VERSION 5.7 ;
BUSBITCHARS "[]" ;
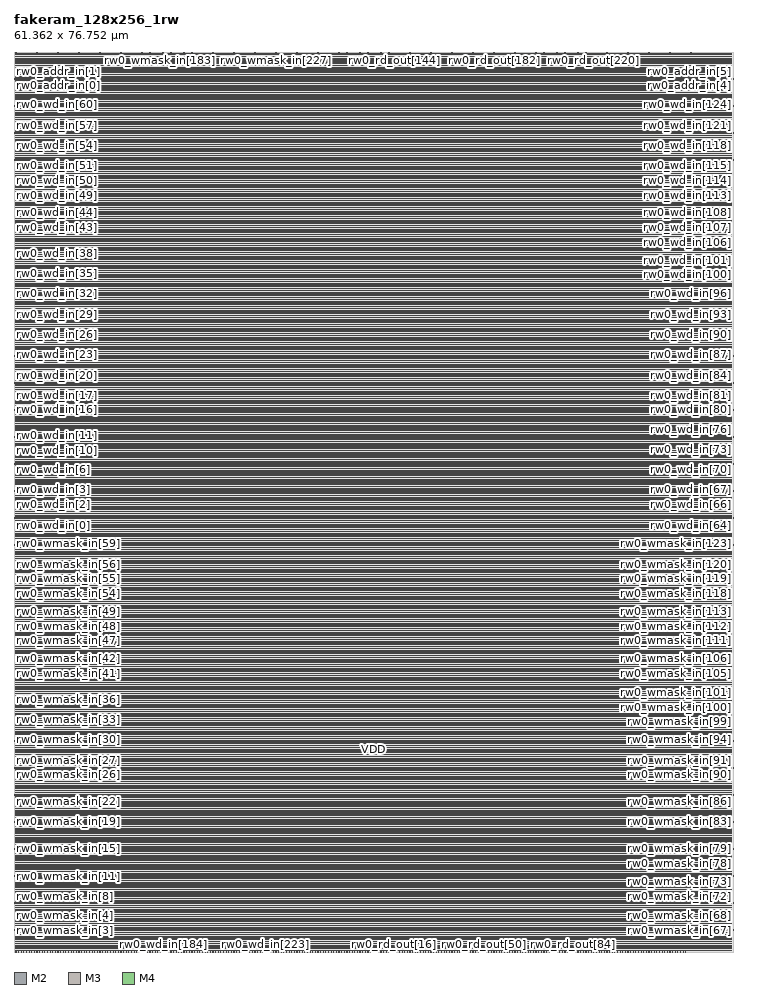
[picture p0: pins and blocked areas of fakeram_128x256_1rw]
MACRO fakeram_128x256_1rw
  FOREIGN fakeram_128x256_1rw 0 0 ;
  SYMMETRY X Y R90 ;
  SIZE 61.362 BY 76.752 ;
  CLASS BLOCK ;
  PIN rw0_wmask_in[0]
    DIRECTION INPUT ;
    USE SIGNAL ;
    SHAPE ABUTMENT ;
    PORT
      LAYER M2 ;
      RECT 0.000 0.138 0.036 0.150 ;
    END
  END rw0_wmask_in[0]
  PIN rw0_wmask_in[1]
    DIRECTION INPUT ;
    USE SIGNAL ;
    SHAPE ABUTMENT ;
    PORT
      LAYER M2 ;
      RECT 0.000 0.714 0.036 0.726 ;
    END
  END rw0_wmask_in[1]
  PIN rw0_wmask_in[2]
    DIRECTION INPUT ;
    USE SIGNAL ;
    SHAPE ABUTMENT ;
    PORT
      LAYER M2 ;
      RECT 0.000 1.290 0.036 1.302 ;
    END
  END rw0_wmask_in[2]
  PIN rw0_wmask_in[3]
    DIRECTION INPUT ;
    USE SIGNAL ;
    SHAPE ABUTMENT ;
    PORT
      LAYER M2 ;
      RECT 0.000 1.866 0.036 1.878 ;
    END
  END rw0_wmask_in[3]
  PIN rw0_wmask_in[4]
    DIRECTION INPUT ;
    USE SIGNAL ;
    SHAPE ABUTMENT ;
    PORT
      LAYER M2 ;
      RECT 0.000 2.442 0.036 2.454 ;
    END
  END rw0_wmask_in[4]
  PIN rw0_wmask_in[5]
    DIRECTION INPUT ;
    USE SIGNAL ;
    SHAPE ABUTMENT ;
    PORT
      LAYER M2 ;
      RECT 0.000 3.018 0.036 3.030 ;
    END
  END rw0_wmask_in[5]
  PIN rw0_wmask_in[6]
    DIRECTION INPUT ;
    USE SIGNAL ;
    SHAPE ABUTMENT ;
    PORT
      LAYER M2 ;
      RECT 0.000 3.594 0.036 3.606 ;
    END
  END rw0_wmask_in[6]
  PIN rw0_wmask_in[7]
    DIRECTION INPUT ;
    USE SIGNAL ;
    SHAPE ABUTMENT ;
    PORT
      LAYER M2 ;
      RECT 0.000 4.170 0.036 4.182 ;
    END
  END rw0_wmask_in[7]
  PIN rw0_wmask_in[8]
    DIRECTION INPUT ;
    USE SIGNAL ;
    SHAPE ABUTMENT ;
    PORT
      LAYER M2 ;
      RECT 0.000 4.746 0.036 4.758 ;
    END
  END rw0_wmask_in[8]
  PIN rw0_wmask_in[9]
    DIRECTION INPUT ;
    USE SIGNAL ;
    SHAPE ABUTMENT ;
    PORT
      LAYER M2 ;
      RECT 0.000 5.322 0.036 5.334 ;
    END
  END rw0_wmask_in[9]
  PIN rw0_wmask_in[10]
    DIRECTION INPUT ;
    USE SIGNAL ;
    SHAPE ABUTMENT ;
    PORT
      LAYER M2 ;
      RECT 0.000 5.898 0.036 5.910 ;
    END
  END rw0_wmask_in[10]
  PIN rw0_wmask_in[11]
    DIRECTION INPUT ;
    USE SIGNAL ;
    SHAPE ABUTMENT ;
    PORT
      LAYER M2 ;
      RECT 0.000 6.474 0.036 6.486 ;
    END
  END rw0_wmask_in[11]
  PIN rw0_wmask_in[12]
    DIRECTION INPUT ;
    USE SIGNAL ;
    SHAPE ABUTMENT ;
    PORT
      LAYER M2 ;
      RECT 0.000 7.050 0.036 7.062 ;
    END
  END rw0_wmask_in[12]
  PIN rw0_wmask_in[13]
    DIRECTION INPUT ;
    USE SIGNAL ;
    SHAPE ABUTMENT ;
    PORT
      LAYER M2 ;
      RECT 0.000 7.626 0.036 7.638 ;
    END
  END rw0_wmask_in[13]
  PIN rw0_wmask_in[14]
    DIRECTION INPUT ;
    USE SIGNAL ;
    SHAPE ABUTMENT ;
    PORT
      LAYER M2 ;
      RECT 0.000 8.202 0.036 8.214 ;
    END
  END rw0_wmask_in[14]
  PIN rw0_wmask_in[15]
    DIRECTION INPUT ;
    USE SIGNAL ;
    SHAPE ABUTMENT ;
    PORT
      LAYER M2 ;
      RECT 0.000 8.778 0.036 8.790 ;
    END
  END rw0_wmask_in[15]
  PIN rw0_wmask_in[16]
    DIRECTION INPUT ;
    USE SIGNAL ;
    SHAPE ABUTMENT ;
    PORT
      LAYER M2 ;
      RECT 0.000 9.354 0.036 9.366 ;
    END
  END rw0_wmask_in[16]
  PIN rw0_wmask_in[17]
    DIRECTION INPUT ;
    USE SIGNAL ;
    SHAPE ABUTMENT ;
    PORT
      LAYER M2 ;
      RECT 0.000 9.930 0.036 9.942 ;
    END
  END rw0_wmask_in[17]
  PIN rw0_wmask_in[18]
    DIRECTION INPUT ;
    USE SIGNAL ;
    SHAPE ABUTMENT ;
    PORT
      LAYER M2 ;
      RECT 0.000 10.506 0.036 10.518 ;
    END
  END rw0_wmask_in[18]
  PIN rw0_wmask_in[19]
    DIRECTION INPUT ;
    USE SIGNAL ;
    SHAPE ABUTMENT ;
    PORT
      LAYER M2 ;
      RECT 0.000 11.082 0.036 11.094 ;
    END
  END rw0_wmask_in[19]
  PIN rw0_wmask_in[20]
    DIRECTION INPUT ;
    USE SIGNAL ;
    SHAPE ABUTMENT ;
    PORT
      LAYER M2 ;
      RECT 0.000 11.658 0.036 11.670 ;
    END
  END rw0_wmask_in[20]
  PIN rw0_wmask_in[21]
    DIRECTION INPUT ;
    USE SIGNAL ;
    SHAPE ABUTMENT ;
    PORT
      LAYER M2 ;
      RECT 0.000 12.234 0.036 12.246 ;
    END
  END rw0_wmask_in[21]
  PIN rw0_wmask_in[22]
    DIRECTION INPUT ;
    USE SIGNAL ;
    SHAPE ABUTMENT ;
    PORT
      LAYER M2 ;
      RECT 0.000 12.810 0.036 12.822 ;
    END
  END rw0_wmask_in[22]
  PIN rw0_wmask_in[23]
    DIRECTION INPUT ;
    USE SIGNAL ;
    SHAPE ABUTMENT ;
    PORT
      LAYER M2 ;
      RECT 0.000 13.386 0.036 13.398 ;
    END
  END rw0_wmask_in[23]
  PIN rw0_wmask_in[24]
    DIRECTION INPUT ;
    USE SIGNAL ;
    SHAPE ABUTMENT ;
    PORT
      LAYER M2 ;
      RECT 0.000 13.962 0.036 13.974 ;
    END
  END rw0_wmask_in[24]
  PIN rw0_wmask_in[25]
    DIRECTION INPUT ;
    USE SIGNAL ;
    SHAPE ABUTMENT ;
    PORT
      LAYER M2 ;
      RECT 0.000 14.538 0.036 14.550 ;
    END
  END rw0_wmask_in[25]
  PIN rw0_wmask_in[26]
    DIRECTION INPUT ;
    USE SIGNAL ;
    SHAPE ABUTMENT ;
    PORT
      LAYER M2 ;
      RECT 0.000 15.114 0.036 15.126 ;
    END
  END rw0_wmask_in[26]
  PIN rw0_wmask_in[27]
    DIRECTION INPUT ;
    USE SIGNAL ;
    SHAPE ABUTMENT ;
    PORT
      LAYER M2 ;
      RECT 0.000 15.690 0.036 15.702 ;
    END
  END rw0_wmask_in[27]
  PIN rw0_wmask_in[28]
    DIRECTION INPUT ;
    USE SIGNAL ;
    SHAPE ABUTMENT ;
    PORT
      LAYER M2 ;
      RECT 0.000 16.266 0.036 16.278 ;
    END
  END rw0_wmask_in[28]
  PIN rw0_wmask_in[29]
    DIRECTION INPUT ;
    USE SIGNAL ;
    SHAPE ABUTMENT ;
    PORT
      LAYER M2 ;
      RECT 0.000 16.842 0.036 16.854 ;
    END
  END rw0_wmask_in[29]
  PIN rw0_wmask_in[30]
    DIRECTION INPUT ;
    USE SIGNAL ;
    SHAPE ABUTMENT ;
    PORT
      LAYER M2 ;
      RECT 0.000 17.418 0.036 17.430 ;
    END
  END rw0_wmask_in[30]
  PIN rw0_wmask_in[31]
    DIRECTION INPUT ;
    USE SIGNAL ;
    SHAPE ABUTMENT ;
    PORT
      LAYER M2 ;
      RECT 0.000 17.994 0.036 18.006 ;
    END
  END rw0_wmask_in[31]
  PIN rw0_wmask_in[32]
    DIRECTION INPUT ;
    USE SIGNAL ;
    SHAPE ABUTMENT ;
    PORT
      LAYER M2 ;
      RECT 0.000 18.570 0.036 18.582 ;
    END
  END rw0_wmask_in[32]
  PIN rw0_wmask_in[33]
    DIRECTION INPUT ;
    USE SIGNAL ;
    SHAPE ABUTMENT ;
    PORT
      LAYER M2 ;
      RECT 0.000 19.146 0.036 19.158 ;
    END
  END rw0_wmask_in[33]
  PIN rw0_wmask_in[34]
    DIRECTION INPUT ;
    USE SIGNAL ;
    SHAPE ABUTMENT ;
    PORT
      LAYER M2 ;
      RECT 0.000 19.722 0.036 19.734 ;
    END
  END rw0_wmask_in[34]
  PIN rw0_wmask_in[35]
    DIRECTION INPUT ;
    USE SIGNAL ;
    SHAPE ABUTMENT ;
    PORT
      LAYER M2 ;
      RECT 0.000 20.298 0.036 20.310 ;
    END
  END rw0_wmask_in[35]
  PIN rw0_wmask_in[36]
    DIRECTION INPUT ;
    USE SIGNAL ;
    SHAPE ABUTMENT ;
    PORT
      LAYER M2 ;
      RECT 0.000 20.874 0.036 20.886 ;
    END
  END rw0_wmask_in[36]
  PIN rw0_wmask_in[37]
    DIRECTION INPUT ;
    USE SIGNAL ;
    SHAPE ABUTMENT ;
    PORT
      LAYER M2 ;
      RECT 0.000 21.450 0.036 21.462 ;
    END
  END rw0_wmask_in[37]
  PIN rw0_wmask_in[38]
    DIRECTION INPUT ;
    USE SIGNAL ;
    SHAPE ABUTMENT ;
    PORT
      LAYER M2 ;
      RECT 0.000 22.026 0.036 22.038 ;
    END
  END rw0_wmask_in[38]
  PIN rw0_wmask_in[39]
    DIRECTION INPUT ;
    USE SIGNAL ;
    SHAPE ABUTMENT ;
    PORT
      LAYER M2 ;
      RECT 0.000 22.602 0.036 22.614 ;
    END
  END rw0_wmask_in[39]
  PIN rw0_wmask_in[40]
    DIRECTION INPUT ;
    USE SIGNAL ;
    SHAPE ABUTMENT ;
    PORT
      LAYER M2 ;
      RECT 0.000 23.178 0.036 23.190 ;
    END
  END rw0_wmask_in[40]
  PIN rw0_wmask_in[41]
    DIRECTION INPUT ;
    USE SIGNAL ;
    SHAPE ABUTMENT ;
    PORT
      LAYER M2 ;
      RECT 0.000 23.754 0.036 23.766 ;
    END
  END rw0_wmask_in[41]
  PIN rw0_wmask_in[42]
    DIRECTION INPUT ;
    USE SIGNAL ;
    SHAPE ABUTMENT ;
    PORT
      LAYER M2 ;
      RECT 0.000 24.330 0.036 24.342 ;
    END
  END rw0_wmask_in[42]
  PIN rw0_wmask_in[43]
    DIRECTION INPUT ;
    USE SIGNAL ;
    SHAPE ABUTMENT ;
    PORT
      LAYER M2 ;
      RECT 0.000 24.906 0.036 24.918 ;
    END
  END rw0_wmask_in[43]
  PIN rw0_wmask_in[44]
    DIRECTION INPUT ;
    USE SIGNAL ;
    SHAPE ABUTMENT ;
    PORT
      LAYER M2 ;
      RECT 0.000 25.482 0.036 25.494 ;
    END
  END rw0_wmask_in[44]
  PIN rw0_wmask_in[45]
    DIRECTION INPUT ;
    USE SIGNAL ;
    SHAPE ABUTMENT ;
    PORT
      LAYER M2 ;
      RECT 0.000 26.058 0.036 26.070 ;
    END
  END rw0_wmask_in[45]
  PIN rw0_wmask_in[46]
    DIRECTION INPUT ;
    USE SIGNAL ;
    SHAPE ABUTMENT ;
    PORT
      LAYER M2 ;
      RECT 0.000 26.634 0.036 26.646 ;
    END
  END rw0_wmask_in[46]
  PIN rw0_wmask_in[47]
    DIRECTION INPUT ;
    USE SIGNAL ;
    SHAPE ABUTMENT ;
    PORT
      LAYER M2 ;
      RECT 0.000 27.210 0.036 27.222 ;
    END
  END rw0_wmask_in[47]
  PIN rw0_wmask_in[48]
    DIRECTION INPUT ;
    USE SIGNAL ;
    SHAPE ABUTMENT ;
    PORT
      LAYER M2 ;
      RECT 0.000 27.786 0.036 27.798 ;
    END
  END rw0_wmask_in[48]
  PIN rw0_wmask_in[49]
    DIRECTION INPUT ;
    USE SIGNAL ;
    SHAPE ABUTMENT ;
    PORT
      LAYER M2 ;
      RECT 0.000 28.362 0.036 28.374 ;
    END
  END rw0_wmask_in[49]
  PIN rw0_wmask_in[50]
    DIRECTION INPUT ;
    USE SIGNAL ;
    SHAPE ABUTMENT ;
    PORT
      LAYER M2 ;
      RECT 0.000 28.938 0.036 28.950 ;
    END
  END rw0_wmask_in[50]
  PIN rw0_wmask_in[51]
    DIRECTION INPUT ;
    USE SIGNAL ;
    SHAPE ABUTMENT ;
    PORT
      LAYER M2 ;
      RECT 0.000 29.514 0.036 29.526 ;
    END
  END rw0_wmask_in[51]
  PIN rw0_wmask_in[52]
    DIRECTION INPUT ;
    USE SIGNAL ;
    SHAPE ABUTMENT ;
    PORT
      LAYER M2 ;
      RECT 0.000 30.090 0.036 30.102 ;
    END
  END rw0_wmask_in[52]
  PIN rw0_wmask_in[53]
    DIRECTION INPUT ;
    USE SIGNAL ;
    SHAPE ABUTMENT ;
    PORT
      LAYER M2 ;
      RECT 0.000 30.666 0.036 30.678 ;
    END
  END rw0_wmask_in[53]
  PIN rw0_wmask_in[54]
    DIRECTION INPUT ;
    USE SIGNAL ;
    SHAPE ABUTMENT ;
    PORT
      LAYER M2 ;
      RECT 0.000 31.242 0.036 31.254 ;
    END
  END rw0_wmask_in[54]
  PIN rw0_wmask_in[55]
    DIRECTION INPUT ;
    USE SIGNAL ;
    SHAPE ABUTMENT ;
    PORT
      LAYER M2 ;
      RECT 0.000 31.818 0.036 31.830 ;
    END
  END rw0_wmask_in[55]
  PIN rw0_wmask_in[56]
    DIRECTION INPUT ;
    USE SIGNAL ;
    SHAPE ABUTMENT ;
    PORT
      LAYER M2 ;
      RECT 0.000 32.394 0.036 32.406 ;
    END
  END rw0_wmask_in[56]
  PIN rw0_wmask_in[57]
    DIRECTION INPUT ;
    USE SIGNAL ;
    SHAPE ABUTMENT ;
    PORT
      LAYER M2 ;
      RECT 0.000 32.970 0.036 32.982 ;
    END
  END rw0_wmask_in[57]
  PIN rw0_wmask_in[58]
    DIRECTION INPUT ;
    USE SIGNAL ;
    SHAPE ABUTMENT ;
    PORT
      LAYER M2 ;
      RECT 0.000 33.546 0.036 33.558 ;
    END
  END rw0_wmask_in[58]
  PIN rw0_wmask_in[59]
    DIRECTION INPUT ;
    USE SIGNAL ;
    SHAPE ABUTMENT ;
    PORT
      LAYER M2 ;
      RECT 0.000 34.122 0.036 34.134 ;
    END
  END rw0_wmask_in[59]
  PIN rw0_wmask_in[60]
    DIRECTION INPUT ;
    USE SIGNAL ;
    SHAPE ABUTMENT ;
    PORT
      LAYER M2 ;
      RECT 0.000 34.698 0.036 34.710 ;
    END
  END rw0_wmask_in[60]
  PIN rw0_wmask_in[61]
    DIRECTION INPUT ;
    USE SIGNAL ;
    SHAPE ABUTMENT ;
    PORT
      LAYER M2 ;
      RECT 0.000 35.274 0.036 35.286 ;
    END
  END rw0_wmask_in[61]
  PIN rw0_wmask_in[62]
    DIRECTION INPUT ;
    USE SIGNAL ;
    SHAPE ABUTMENT ;
    PORT
      LAYER M2 ;
      RECT 0.000 35.850 0.036 35.862 ;
    END
  END rw0_wmask_in[62]
  PIN rw0_wmask_in[63]
    DIRECTION INPUT ;
    USE SIGNAL ;
    SHAPE ABUTMENT ;
    PORT
      LAYER M2 ;
      RECT 0.000 36.426 0.036 36.438 ;
    END
  END rw0_wmask_in[63]
  PIN rw0_wmask_in[64]
    DIRECTION INPUT ;
    USE SIGNAL ;
    SHAPE ABUTMENT ;
    PORT
      LAYER M2 ;
      RECT 61.326 0.138 61.362 0.150 ;
    END
  END rw0_wmask_in[64]
  PIN rw0_wmask_in[65]
    DIRECTION INPUT ;
    USE SIGNAL ;
    SHAPE ABUTMENT ;
    PORT
      LAYER M2 ;
      RECT 61.326 0.714 61.362 0.726 ;
    END
  END rw0_wmask_in[65]
  PIN rw0_wmask_in[66]
    DIRECTION INPUT ;
    USE SIGNAL ;
    SHAPE ABUTMENT ;
    PORT
      LAYER M2 ;
      RECT 61.326 1.290 61.362 1.302 ;
    END
  END rw0_wmask_in[66]
  PIN rw0_wmask_in[67]
    DIRECTION INPUT ;
    USE SIGNAL ;
    SHAPE ABUTMENT ;
    PORT
      LAYER M2 ;
      RECT 61.326 1.866 61.362 1.878 ;
    END
  END rw0_wmask_in[67]
  PIN rw0_wmask_in[68]
    DIRECTION INPUT ;
    USE SIGNAL ;
    SHAPE ABUTMENT ;
    PORT
      LAYER M2 ;
      RECT 61.326 2.442 61.362 2.454 ;
    END
  END rw0_wmask_in[68]
  PIN rw0_wmask_in[69]
    DIRECTION INPUT ;
    USE SIGNAL ;
    SHAPE ABUTMENT ;
    PORT
      LAYER M2 ;
      RECT 61.326 3.018 61.362 3.030 ;
    END
  END rw0_wmask_in[69]
  PIN rw0_wmask_in[70]
    DIRECTION INPUT ;
    USE SIGNAL ;
    SHAPE ABUTMENT ;
    PORT
      LAYER M2 ;
      RECT 61.326 3.594 61.362 3.606 ;
    END
  END rw0_wmask_in[70]
  PIN rw0_wmask_in[71]
    DIRECTION INPUT ;
    USE SIGNAL ;
    SHAPE ABUTMENT ;
    PORT
      LAYER M2 ;
      RECT 61.326 4.170 61.362 4.182 ;
    END
  END rw0_wmask_in[71]
  PIN rw0_wmask_in[72]
    DIRECTION INPUT ;
    USE SIGNAL ;
    SHAPE ABUTMENT ;
    PORT
      LAYER M2 ;
      RECT 61.326 4.746 61.362 4.758 ;
    END
  END rw0_wmask_in[72]
  PIN rw0_wmask_in[73]
    DIRECTION INPUT ;
    USE SIGNAL ;
    SHAPE ABUTMENT ;
    PORT
      LAYER M2 ;
      RECT 61.326 5.322 61.362 5.334 ;
    END
  END rw0_wmask_in[73]
  PIN rw0_wmask_in[74]
    DIRECTION INPUT ;
    USE SIGNAL ;
    SHAPE ABUTMENT ;
    PORT
      LAYER M2 ;
      RECT 61.326 5.898 61.362 5.910 ;
    END
  END rw0_wmask_in[74]
  PIN rw0_wmask_in[75]
    DIRECTION INPUT ;
    USE SIGNAL ;
    SHAPE ABUTMENT ;
    PORT
      LAYER M2 ;
      RECT 61.326 6.474 61.362 6.486 ;
    END
  END rw0_wmask_in[75]
  PIN rw0_wmask_in[76]
    DIRECTION INPUT ;
    USE SIGNAL ;
    SHAPE ABUTMENT ;
    PORT
      LAYER M2 ;
      RECT 61.326 7.050 61.362 7.062 ;
    END
  END rw0_wmask_in[76]
  PIN rw0_wmask_in[77]
    DIRECTION INPUT ;
    USE SIGNAL ;
    SHAPE ABUTMENT ;
    PORT
      LAYER M2 ;
      RECT 61.326 7.626 61.362 7.638 ;
    END
  END rw0_wmask_in[77]
  PIN rw0_wmask_in[78]
    DIRECTION INPUT ;
    USE SIGNAL ;
    SHAPE ABUTMENT ;
    PORT
      LAYER M2 ;
      RECT 61.326 8.202 61.362 8.214 ;
    END
  END rw0_wmask_in[78]
  PIN rw0_wmask_in[79]
    DIRECTION INPUT ;
    USE SIGNAL ;
    SHAPE ABUTMENT ;
    PORT
      LAYER M2 ;
      RECT 61.326 8.778 61.362 8.790 ;
    END
  END rw0_wmask_in[79]
  PIN rw0_wmask_in[80]
    DIRECTION INPUT ;
    USE SIGNAL ;
    SHAPE ABUTMENT ;
    PORT
      LAYER M2 ;
      RECT 61.326 9.354 61.362 9.366 ;
    END
  END rw0_wmask_in[80]
  PIN rw0_wmask_in[81]
    DIRECTION INPUT ;
    USE SIGNAL ;
    SHAPE ABUTMENT ;
    PORT
      LAYER M2 ;
      RECT 61.326 9.930 61.362 9.942 ;
    END
  END rw0_wmask_in[81]
  PIN rw0_wmask_in[82]
    DIRECTION INPUT ;
    USE SIGNAL ;
    SHAPE ABUTMENT ;
    PORT
      LAYER M2 ;
      RECT 61.326 10.506 61.362 10.518 ;
    END
  END rw0_wmask_in[82]
  PIN rw0_wmask_in[83]
    DIRECTION INPUT ;
    USE SIGNAL ;
    SHAPE ABUTMENT ;
    PORT
      LAYER M2 ;
      RECT 61.326 11.082 61.362 11.094 ;
    END
  END rw0_wmask_in[83]
  PIN rw0_wmask_in[84]
    DIRECTION INPUT ;
    USE SIGNAL ;
    SHAPE ABUTMENT ;
    PORT
      LAYER M2 ;
      RECT 61.326 11.658 61.362 11.670 ;
    END
  END rw0_wmask_in[84]
  PIN rw0_wmask_in[85]
    DIRECTION INPUT ;
    USE SIGNAL ;
    SHAPE ABUTMENT ;
    PORT
      LAYER M2 ;
      RECT 61.326 12.234 61.362 12.246 ;
    END
  END rw0_wmask_in[85]
  PIN rw0_wmask_in[86]
    DIRECTION INPUT ;
    USE SIGNAL ;
    SHAPE ABUTMENT ;
    PORT
      LAYER M2 ;
      RECT 61.326 12.810 61.362 12.822 ;
    END
  END rw0_wmask_in[86]
  PIN rw0_wmask_in[87]
    DIRECTION INPUT ;
    USE SIGNAL ;
    SHAPE ABUTMENT ;
    PORT
      LAYER M2 ;
      RECT 61.326 13.386 61.362 13.398 ;
    END
  END rw0_wmask_in[87]
  PIN rw0_wmask_in[88]
    DIRECTION INPUT ;
    USE SIGNAL ;
    SHAPE ABUTMENT ;
    PORT
      LAYER M2 ;
      RECT 61.326 13.962 61.362 13.974 ;
    END
  END rw0_wmask_in[88]
  PIN rw0_wmask_in[89]
    DIRECTION INPUT ;
    USE SIGNAL ;
    SHAPE ABUTMENT ;
    PORT
      LAYER M2 ;
      RECT 61.326 14.538 61.362 14.550 ;
    END
  END rw0_wmask_in[89]
  PIN rw0_wmask_in[90]
    DIRECTION INPUT ;
    USE SIGNAL ;
    SHAPE ABUTMENT ;
    PORT
      LAYER M2 ;
      RECT 61.326 15.114 61.362 15.126 ;
    END
  END rw0_wmask_in[90]
  PIN rw0_wmask_in[91]
    DIRECTION INPUT ;
    USE SIGNAL ;
    SHAPE ABUTMENT ;
    PORT
      LAYER M2 ;
      RECT 61.326 15.690 61.362 15.702 ;
    END
  END rw0_wmask_in[91]
  PIN rw0_wmask_in[92]
    DIRECTION INPUT ;
    USE SIGNAL ;
    SHAPE ABUTMENT ;
    PORT
      LAYER M2 ;
      RECT 61.326 16.266 61.362 16.278 ;
    END
  END rw0_wmask_in[92]
  PIN rw0_wmask_in[93]
    DIRECTION INPUT ;
    USE SIGNAL ;
    SHAPE ABUTMENT ;
    PORT
      LAYER M2 ;
      RECT 61.326 16.842 61.362 16.854 ;
    END
  END rw0_wmask_in[93]
  PIN rw0_wmask_in[94]
    DIRECTION INPUT ;
    USE SIGNAL ;
    SHAPE ABUTMENT ;
    PORT
      LAYER M2 ;
      RECT 61.326 17.418 61.362 17.430 ;
    END
  END rw0_wmask_in[94]
  PIN rw0_wmask_in[95]
    DIRECTION INPUT ;
    USE SIGNAL ;
    SHAPE ABUTMENT ;
    PORT
      LAYER M2 ;
      RECT 61.326 17.994 61.362 18.006 ;
    END
  END rw0_wmask_in[95]
  PIN rw0_wmask_in[96]
    DIRECTION INPUT ;
    USE SIGNAL ;
    SHAPE ABUTMENT ;
    PORT
      LAYER M2 ;
      RECT 61.326 18.570 61.362 18.582 ;
    END
  END rw0_wmask_in[96]
  PIN rw0_wmask_in[97]
    DIRECTION INPUT ;
    USE SIGNAL ;
    SHAPE ABUTMENT ;
    PORT
      LAYER M2 ;
      RECT 61.326 19.146 61.362 19.158 ;
    END
  END rw0_wmask_in[97]
  PIN rw0_wmask_in[98]
    DIRECTION INPUT ;
    USE SIGNAL ;
    SHAPE ABUTMENT ;
    PORT
      LAYER M2 ;
      RECT 61.326 19.722 61.362 19.734 ;
    END
  END rw0_wmask_in[98]
  PIN rw0_wmask_in[99]
    DIRECTION INPUT ;
    USE SIGNAL ;
    SHAPE ABUTMENT ;
    PORT
      LAYER M2 ;
      RECT 61.326 20.298 61.362 20.310 ;
    END
  END rw0_wmask_in[99]
  PIN rw0_wmask_in[100]
    DIRECTION INPUT ;
    USE SIGNAL ;
    SHAPE ABUTMENT ;
    PORT
      LAYER M2 ;
      RECT 61.326 20.874 61.362 20.886 ;
    END
  END rw0_wmask_in[100]
  PIN rw0_wmask_in[101]
    DIRECTION INPUT ;
    USE SIGNAL ;
    SHAPE ABUTMENT ;
    PORT
      LAYER M2 ;
      RECT 61.326 21.450 61.362 21.462 ;
    END
  END rw0_wmask_in[101]
  PIN rw0_wmask_in[102]
    DIRECTION INPUT ;
    USE SIGNAL ;
    SHAPE ABUTMENT ;
    PORT
      LAYER M2 ;
      RECT 61.326 22.026 61.362 22.038 ;
    END
  END rw0_wmask_in[102]
  PIN rw0_wmask_in[103]
    DIRECTION INPUT ;
    USE SIGNAL ;
    SHAPE ABUTMENT ;
    PORT
      LAYER M2 ;
      RECT 61.326 22.602 61.362 22.614 ;
    END
  END rw0_wmask_in[103]
  PIN rw0_wmask_in[104]
    DIRECTION INPUT ;
    USE SIGNAL ;
    SHAPE ABUTMENT ;
    PORT
      LAYER M2 ;
      RECT 61.326 23.178 61.362 23.190 ;
    END
  END rw0_wmask_in[104]
  PIN rw0_wmask_in[105]
    DIRECTION INPUT ;
    USE SIGNAL ;
    SHAPE ABUTMENT ;
    PORT
      LAYER M2 ;
      RECT 61.326 23.754 61.362 23.766 ;
    END
  END rw0_wmask_in[105]
  PIN rw0_wmask_in[106]
    DIRECTION INPUT ;
    USE SIGNAL ;
    SHAPE ABUTMENT ;
    PORT
      LAYER M2 ;
      RECT 61.326 24.330 61.362 24.342 ;
    END
  END rw0_wmask_in[106]
  PIN rw0_wmask_in[107]
    DIRECTION INPUT ;
    USE SIGNAL ;
    SHAPE ABUTMENT ;
    PORT
      LAYER M2 ;
      RECT 61.326 24.906 61.362 24.918 ;
    END
  END rw0_wmask_in[107]
  PIN rw0_wmask_in[108]
    DIRECTION INPUT ;
    USE SIGNAL ;
    SHAPE ABUTMENT ;
    PORT
      LAYER M2 ;
      RECT 61.326 25.482 61.362 25.494 ;
    END
  END rw0_wmask_in[108]
  PIN rw0_wmask_in[109]
    DIRECTION INPUT ;
    USE SIGNAL ;
    SHAPE ABUTMENT ;
    PORT
      LAYER M2 ;
      RECT 61.326 26.058 61.362 26.070 ;
    END
  END rw0_wmask_in[109]
  PIN rw0_wmask_in[110]
    DIRECTION INPUT ;
    USE SIGNAL ;
    SHAPE ABUTMENT ;
    PORT
      LAYER M2 ;
      RECT 61.326 26.634 61.362 26.646 ;
    END
  END rw0_wmask_in[110]
  PIN rw0_wmask_in[111]
    DIRECTION INPUT ;
    USE SIGNAL ;
    SHAPE ABUTMENT ;
    PORT
      LAYER M2 ;
      RECT 61.326 27.210 61.362 27.222 ;
    END
  END rw0_wmask_in[111]
  PIN rw0_wmask_in[112]
    DIRECTION INPUT ;
    USE SIGNAL ;
    SHAPE ABUTMENT ;
    PORT
      LAYER M2 ;
      RECT 61.326 27.786 61.362 27.798 ;
    END
  END rw0_wmask_in[112]
  PIN rw0_wmask_in[113]
    DIRECTION INPUT ;
    USE SIGNAL ;
    SHAPE ABUTMENT ;
    PORT
      LAYER M2 ;
      RECT 61.326 28.362 61.362 28.374 ;
    END
  END rw0_wmask_in[113]
  PIN rw0_wmask_in[114]
    DIRECTION INPUT ;
    USE SIGNAL ;
    SHAPE ABUTMENT ;
    PORT
      LAYER M2 ;
      RECT 61.326 28.938 61.362 28.950 ;
    END
  END rw0_wmask_in[114]
  PIN rw0_wmask_in[115]
    DIRECTION INPUT ;
    USE SIGNAL ;
    SHAPE ABUTMENT ;
    PORT
      LAYER M2 ;
      RECT 61.326 29.514 61.362 29.526 ;
    END
  END rw0_wmask_in[115]
  PIN rw0_wmask_in[116]
    DIRECTION INPUT ;
    USE SIGNAL ;
    SHAPE ABUTMENT ;
    PORT
      LAYER M2 ;
      RECT 61.326 30.090 61.362 30.102 ;
    END
  END rw0_wmask_in[116]
  PIN rw0_wmask_in[117]
    DIRECTION INPUT ;
    USE SIGNAL ;
    SHAPE ABUTMENT ;
    PORT
      LAYER M2 ;
      RECT 61.326 30.666 61.362 30.678 ;
    END
  END rw0_wmask_in[117]
  PIN rw0_wmask_in[118]
    DIRECTION INPUT ;
    USE SIGNAL ;
    SHAPE ABUTMENT ;
    PORT
      LAYER M2 ;
      RECT 61.326 31.242 61.362 31.254 ;
    END
  END rw0_wmask_in[118]
  PIN rw0_wmask_in[119]
    DIRECTION INPUT ;
    USE SIGNAL ;
    SHAPE ABUTMENT ;
    PORT
      LAYER M2 ;
      RECT 61.326 31.818 61.362 31.830 ;
    END
  END rw0_wmask_in[119]
  PIN rw0_wmask_in[120]
    DIRECTION INPUT ;
    USE SIGNAL ;
    SHAPE ABUTMENT ;
    PORT
      LAYER M2 ;
      RECT 61.326 32.394 61.362 32.406 ;
    END
  END rw0_wmask_in[120]
  PIN rw0_wmask_in[121]
    DIRECTION INPUT ;
    USE SIGNAL ;
    SHAPE ABUTMENT ;
    PORT
      LAYER M2 ;
      RECT 61.326 32.970 61.362 32.982 ;
    END
  END rw0_wmask_in[121]
  PIN rw0_wmask_in[122]
    DIRECTION INPUT ;
    USE SIGNAL ;
    SHAPE ABUTMENT ;
    PORT
      LAYER M2 ;
      RECT 61.326 33.546 61.362 33.558 ;
    END
  END rw0_wmask_in[122]
  PIN rw0_wmask_in[123]
    DIRECTION INPUT ;
    USE SIGNAL ;
    SHAPE ABUTMENT ;
    PORT
      LAYER M2 ;
      RECT 61.326 34.122 61.362 34.134 ;
    END
  END rw0_wmask_in[123]
  PIN rw0_wmask_in[124]
    DIRECTION INPUT ;
    USE SIGNAL ;
    SHAPE ABUTMENT ;
    PORT
      LAYER M2 ;
      RECT 61.326 34.698 61.362 34.710 ;
    END
  END rw0_wmask_in[124]
  PIN rw0_wmask_in[125]
    DIRECTION INPUT ;
    USE SIGNAL ;
    SHAPE ABUTMENT ;
    PORT
      LAYER M2 ;
      RECT 61.326 35.274 61.362 35.286 ;
    END
  END rw0_wmask_in[125]
  PIN rw0_wmask_in[126]
    DIRECTION INPUT ;
    USE SIGNAL ;
    SHAPE ABUTMENT ;
    PORT
      LAYER M2 ;
      RECT 61.326 35.850 61.362 35.862 ;
    END
  END rw0_wmask_in[126]
  PIN rw0_wmask_in[127]
    DIRECTION INPUT ;
    USE SIGNAL ;
    SHAPE ABUTMENT ;
    PORT
      LAYER M2 ;
      RECT 61.326 36.426 61.362 36.438 ;
    END
  END rw0_wmask_in[127]
  PIN rw0_wmask_in[128]
    DIRECTION INPUT ;
    USE SIGNAL ;
    SHAPE ABUTMENT ;
    PORT
      LAYER M3 ;
      RECT 0.161 76.710 0.175 76.752 ;
    END
  END rw0_wmask_in[128]
  PIN rw0_wmask_in[129]
    DIRECTION INPUT ;
    USE SIGNAL ;
    SHAPE ABUTMENT ;
    PORT
      LAYER M3 ;
      RECT 0.385 76.710 0.399 76.752 ;
    END
  END rw0_wmask_in[129]
  PIN rw0_wmask_in[130]
    DIRECTION INPUT ;
    USE SIGNAL ;
    SHAPE ABUTMENT ;
    PORT
      LAYER M3 ;
      RECT 0.609 76.710 0.623 76.752 ;
    END
  END rw0_wmask_in[130]
  PIN rw0_wmask_in[131]
    DIRECTION INPUT ;
    USE SIGNAL ;
    SHAPE ABUTMENT ;
    PORT
      LAYER M3 ;
      RECT 0.833 76.710 0.847 76.752 ;
    END
  END rw0_wmask_in[131]
  PIN rw0_wmask_in[132]
    DIRECTION INPUT ;
    USE SIGNAL ;
    SHAPE ABUTMENT ;
    PORT
      LAYER M3 ;
      RECT 1.057 76.710 1.071 76.752 ;
    END
  END rw0_wmask_in[132]
  PIN rw0_wmask_in[133]
    DIRECTION INPUT ;
    USE SIGNAL ;
    SHAPE ABUTMENT ;
    PORT
      LAYER M3 ;
      RECT 1.281 76.710 1.295 76.752 ;
    END
  END rw0_wmask_in[133]
  PIN rw0_wmask_in[134]
    DIRECTION INPUT ;
    USE SIGNAL ;
    SHAPE ABUTMENT ;
    PORT
      LAYER M3 ;
      RECT 1.505 76.710 1.519 76.752 ;
    END
  END rw0_wmask_in[134]
  PIN rw0_wmask_in[135]
    DIRECTION INPUT ;
    USE SIGNAL ;
    SHAPE ABUTMENT ;
    PORT
      LAYER M3 ;
      RECT 1.729 76.710 1.743 76.752 ;
    END
  END rw0_wmask_in[135]
  PIN rw0_wmask_in[136]
    DIRECTION INPUT ;
    USE SIGNAL ;
    SHAPE ABUTMENT ;
    PORT
      LAYER M3 ;
      RECT 1.953 76.710 1.967 76.752 ;
    END
  END rw0_wmask_in[136]
  PIN rw0_wmask_in[137]
    DIRECTION INPUT ;
    USE SIGNAL ;
    SHAPE ABUTMENT ;
    PORT
      LAYER M3 ;
      RECT 2.177 76.710 2.191 76.752 ;
    END
  END rw0_wmask_in[137]
  PIN rw0_wmask_in[138]
    DIRECTION INPUT ;
    USE SIGNAL ;
    SHAPE ABUTMENT ;
    PORT
      LAYER M3 ;
      RECT 2.401 76.710 2.415 76.752 ;
    END
  END rw0_wmask_in[138]
  PIN rw0_wmask_in[139]
    DIRECTION INPUT ;
    USE SIGNAL ;
    SHAPE ABUTMENT ;
    PORT
      LAYER M3 ;
      RECT 2.625 76.710 2.639 76.752 ;
    END
  END rw0_wmask_in[139]
  PIN rw0_wmask_in[140]
    DIRECTION INPUT ;
    USE SIGNAL ;
    SHAPE ABUTMENT ;
    PORT
      LAYER M3 ;
      RECT 2.849 76.710 2.863 76.752 ;
    END
  END rw0_wmask_in[140]
  PIN rw0_wmask_in[141]
    DIRECTION INPUT ;
    USE SIGNAL ;
    SHAPE ABUTMENT ;
    PORT
      LAYER M3 ;
      RECT 3.073 76.710 3.087 76.752 ;
    END
  END rw0_wmask_in[141]
  PIN rw0_wmask_in[142]
    DIRECTION INPUT ;
    USE SIGNAL ;
    SHAPE ABUTMENT ;
    PORT
      LAYER M3 ;
      RECT 3.297 76.710 3.311 76.752 ;
    END
  END rw0_wmask_in[142]
  PIN rw0_wmask_in[143]
    DIRECTION INPUT ;
    USE SIGNAL ;
    SHAPE ABUTMENT ;
    PORT
      LAYER M3 ;
      RECT 3.521 76.710 3.535 76.752 ;
    END
  END rw0_wmask_in[143]
  PIN rw0_wmask_in[144]
    DIRECTION INPUT ;
    USE SIGNAL ;
    SHAPE ABUTMENT ;
    PORT
      LAYER M3 ;
      RECT 3.745 76.710 3.759 76.752 ;
    END
  END rw0_wmask_in[144]
  PIN rw0_wmask_in[145]
    DIRECTION INPUT ;
    USE SIGNAL ;
    SHAPE ABUTMENT ;
    PORT
      LAYER M3 ;
      RECT 3.969 76.710 3.983 76.752 ;
    END
  END rw0_wmask_in[145]
  PIN rw0_wmask_in[146]
    DIRECTION INPUT ;
    USE SIGNAL ;
    SHAPE ABUTMENT ;
    PORT
      LAYER M3 ;
      RECT 4.193 76.710 4.207 76.752 ;
    END
  END rw0_wmask_in[146]
  PIN rw0_wmask_in[147]
    DIRECTION INPUT ;
    USE SIGNAL ;
    SHAPE ABUTMENT ;
    PORT
      LAYER M3 ;
      RECT 4.417 76.710 4.431 76.752 ;
    END
  END rw0_wmask_in[147]
  PIN rw0_wmask_in[148]
    DIRECTION INPUT ;
    USE SIGNAL ;
    SHAPE ABUTMENT ;
    PORT
      LAYER M3 ;
      RECT 4.641 76.710 4.655 76.752 ;
    END
  END rw0_wmask_in[148]
  PIN rw0_wmask_in[149]
    DIRECTION INPUT ;
    USE SIGNAL ;
    SHAPE ABUTMENT ;
    PORT
      LAYER M3 ;
      RECT 4.865 76.710 4.879 76.752 ;
    END
  END rw0_wmask_in[149]
  PIN rw0_wmask_in[150]
    DIRECTION INPUT ;
    USE SIGNAL ;
    SHAPE ABUTMENT ;
    PORT
      LAYER M3 ;
      RECT 5.089 76.710 5.103 76.752 ;
    END
  END rw0_wmask_in[150]
  PIN rw0_wmask_in[151]
    DIRECTION INPUT ;
    USE SIGNAL ;
    SHAPE ABUTMENT ;
    PORT
      LAYER M3 ;
      RECT 5.313 76.710 5.327 76.752 ;
    END
  END rw0_wmask_in[151]
  PIN rw0_wmask_in[152]
    DIRECTION INPUT ;
    USE SIGNAL ;
    SHAPE ABUTMENT ;
    PORT
      LAYER M3 ;
      RECT 5.537 76.710 5.551 76.752 ;
    END
  END rw0_wmask_in[152]
  PIN rw0_wmask_in[153]
    DIRECTION INPUT ;
    USE SIGNAL ;
    SHAPE ABUTMENT ;
    PORT
      LAYER M3 ;
      RECT 5.761 76.710 5.775 76.752 ;
    END
  END rw0_wmask_in[153]
  PIN rw0_wmask_in[154]
    DIRECTION INPUT ;
    USE SIGNAL ;
    SHAPE ABUTMENT ;
    PORT
      LAYER M3 ;
      RECT 5.985 76.710 5.999 76.752 ;
    END
  END rw0_wmask_in[154]
  PIN rw0_wmask_in[155]
    DIRECTION INPUT ;
    USE SIGNAL ;
    SHAPE ABUTMENT ;
    PORT
      LAYER M3 ;
      RECT 6.209 76.710 6.223 76.752 ;
    END
  END rw0_wmask_in[155]
  PIN rw0_wmask_in[156]
    DIRECTION INPUT ;
    USE SIGNAL ;
    SHAPE ABUTMENT ;
    PORT
      LAYER M3 ;
      RECT 6.433 76.710 6.447 76.752 ;
    END
  END rw0_wmask_in[156]
  PIN rw0_wmask_in[157]
    DIRECTION INPUT ;
    USE SIGNAL ;
    SHAPE ABUTMENT ;
    PORT
      LAYER M3 ;
      RECT 6.657 76.710 6.671 76.752 ;
    END
  END rw0_wmask_in[157]
  PIN rw0_wmask_in[158]
    DIRECTION INPUT ;
    USE SIGNAL ;
    SHAPE ABUTMENT ;
    PORT
      LAYER M3 ;
      RECT 6.881 76.710 6.895 76.752 ;
    END
  END rw0_wmask_in[158]
  PIN rw0_wmask_in[159]
    DIRECTION INPUT ;
    USE SIGNAL ;
    SHAPE ABUTMENT ;
    PORT
      LAYER M3 ;
      RECT 7.105 76.710 7.119 76.752 ;
    END
  END rw0_wmask_in[159]
  PIN rw0_wmask_in[160]
    DIRECTION INPUT ;
    USE SIGNAL ;
    SHAPE ABUTMENT ;
    PORT
      LAYER M3 ;
      RECT 7.329 76.710 7.343 76.752 ;
    END
  END rw0_wmask_in[160]
  PIN rw0_wmask_in[161]
    DIRECTION INPUT ;
    USE SIGNAL ;
    SHAPE ABUTMENT ;
    PORT
      LAYER M3 ;
      RECT 7.553 76.710 7.567 76.752 ;
    END
  END rw0_wmask_in[161]
  PIN rw0_wmask_in[162]
    DIRECTION INPUT ;
    USE SIGNAL ;
    SHAPE ABUTMENT ;
    PORT
      LAYER M3 ;
      RECT 7.777 76.710 7.791 76.752 ;
    END
  END rw0_wmask_in[162]
  PIN rw0_wmask_in[163]
    DIRECTION INPUT ;
    USE SIGNAL ;
    SHAPE ABUTMENT ;
    PORT
      LAYER M3 ;
      RECT 8.001 76.710 8.015 76.752 ;
    END
  END rw0_wmask_in[163]
  PIN rw0_wmask_in[164]
    DIRECTION INPUT ;
    USE SIGNAL ;
    SHAPE ABUTMENT ;
    PORT
      LAYER M3 ;
      RECT 8.225 76.710 8.239 76.752 ;
    END
  END rw0_wmask_in[164]
  PIN rw0_wmask_in[165]
    DIRECTION INPUT ;
    USE SIGNAL ;
    SHAPE ABUTMENT ;
    PORT
      LAYER M3 ;
      RECT 8.449 76.710 8.463 76.752 ;
    END
  END rw0_wmask_in[165]
  PIN rw0_wmask_in[166]
    DIRECTION INPUT ;
    USE SIGNAL ;
    SHAPE ABUTMENT ;
    PORT
      LAYER M3 ;
      RECT 8.673 76.710 8.687 76.752 ;
    END
  END rw0_wmask_in[166]
  PIN rw0_wmask_in[167]
    DIRECTION INPUT ;
    USE SIGNAL ;
    SHAPE ABUTMENT ;
    PORT
      LAYER M3 ;
      RECT 8.897 76.710 8.911 76.752 ;
    END
  END rw0_wmask_in[167]
  PIN rw0_wmask_in[168]
    DIRECTION INPUT ;
    USE SIGNAL ;
    SHAPE ABUTMENT ;
    PORT
      LAYER M3 ;
      RECT 9.121 76.710 9.135 76.752 ;
    END
  END rw0_wmask_in[168]
  PIN rw0_wmask_in[169]
    DIRECTION INPUT ;
    USE SIGNAL ;
    SHAPE ABUTMENT ;
    PORT
      LAYER M3 ;
      RECT 9.345 76.710 9.359 76.752 ;
    END
  END rw0_wmask_in[169]
  PIN rw0_wmask_in[170]
    DIRECTION INPUT ;
    USE SIGNAL ;
    SHAPE ABUTMENT ;
    PORT
      LAYER M3 ;
      RECT 9.569 76.710 9.583 76.752 ;
    END
  END rw0_wmask_in[170]
  PIN rw0_wmask_in[171]
    DIRECTION INPUT ;
    USE SIGNAL ;
    SHAPE ABUTMENT ;
    PORT
      LAYER M3 ;
      RECT 9.793 76.710 9.807 76.752 ;
    END
  END rw0_wmask_in[171]
  PIN rw0_wmask_in[172]
    DIRECTION INPUT ;
    USE SIGNAL ;
    SHAPE ABUTMENT ;
    PORT
      LAYER M3 ;
      RECT 10.017 76.710 10.031 76.752 ;
    END
  END rw0_wmask_in[172]
  PIN rw0_wmask_in[173]
    DIRECTION INPUT ;
    USE SIGNAL ;
    SHAPE ABUTMENT ;
    PORT
      LAYER M3 ;
      RECT 10.241 76.710 10.255 76.752 ;
    END
  END rw0_wmask_in[173]
  PIN rw0_wmask_in[174]
    DIRECTION INPUT ;
    USE SIGNAL ;
    SHAPE ABUTMENT ;
    PORT
      LAYER M3 ;
      RECT 10.465 76.710 10.479 76.752 ;
    END
  END rw0_wmask_in[174]
  PIN rw0_wmask_in[175]
    DIRECTION INPUT ;
    USE SIGNAL ;
    SHAPE ABUTMENT ;
    PORT
      LAYER M3 ;
      RECT 10.689 76.710 10.703 76.752 ;
    END
  END rw0_wmask_in[175]
  PIN rw0_wmask_in[176]
    DIRECTION INPUT ;
    USE SIGNAL ;
    SHAPE ABUTMENT ;
    PORT
      LAYER M3 ;
      RECT 10.913 76.710 10.927 76.752 ;
    END
  END rw0_wmask_in[176]
  PIN rw0_wmask_in[177]
    DIRECTION INPUT ;
    USE SIGNAL ;
    SHAPE ABUTMENT ;
    PORT
      LAYER M3 ;
      RECT 11.137 76.710 11.151 76.752 ;
    END
  END rw0_wmask_in[177]
  PIN rw0_wmask_in[178]
    DIRECTION INPUT ;
    USE SIGNAL ;
    SHAPE ABUTMENT ;
    PORT
      LAYER M3 ;
      RECT 11.361 76.710 11.375 76.752 ;
    END
  END rw0_wmask_in[178]
  PIN rw0_wmask_in[179]
    DIRECTION INPUT ;
    USE SIGNAL ;
    SHAPE ABUTMENT ;
    PORT
      LAYER M3 ;
      RECT 11.585 76.710 11.599 76.752 ;
    END
  END rw0_wmask_in[179]
  PIN rw0_wmask_in[180]
    DIRECTION INPUT ;
    USE SIGNAL ;
    SHAPE ABUTMENT ;
    PORT
      LAYER M3 ;
      RECT 11.809 76.710 11.823 76.752 ;
    END
  END rw0_wmask_in[180]
  PIN rw0_wmask_in[181]
    DIRECTION INPUT ;
    USE SIGNAL ;
    SHAPE ABUTMENT ;
    PORT
      LAYER M3 ;
      RECT 12.033 76.710 12.047 76.752 ;
    END
  END rw0_wmask_in[181]
  PIN rw0_wmask_in[182]
    DIRECTION INPUT ;
    USE SIGNAL ;
    SHAPE ABUTMENT ;
    PORT
      LAYER M3 ;
      RECT 12.257 76.710 12.271 76.752 ;
    END
  END rw0_wmask_in[182]
  PIN rw0_wmask_in[183]
    DIRECTION INPUT ;
    USE SIGNAL ;
    SHAPE ABUTMENT ;
    PORT
      LAYER M3 ;
      RECT 12.481 76.710 12.495 76.752 ;
    END
  END rw0_wmask_in[183]
  PIN rw0_wmask_in[184]
    DIRECTION INPUT ;
    USE SIGNAL ;
    SHAPE ABUTMENT ;
    PORT
      LAYER M3 ;
      RECT 12.705 76.710 12.719 76.752 ;
    END
  END rw0_wmask_in[184]
  PIN rw0_wmask_in[185]
    DIRECTION INPUT ;
    USE SIGNAL ;
    SHAPE ABUTMENT ;
    PORT
      LAYER M3 ;
      RECT 12.929 76.710 12.943 76.752 ;
    END
  END rw0_wmask_in[185]
  PIN rw0_wmask_in[186]
    DIRECTION INPUT ;
    USE SIGNAL ;
    SHAPE ABUTMENT ;
    PORT
      LAYER M3 ;
      RECT 13.153 76.710 13.167 76.752 ;
    END
  END rw0_wmask_in[186]
  PIN rw0_wmask_in[187]
    DIRECTION INPUT ;
    USE SIGNAL ;
    SHAPE ABUTMENT ;
    PORT
      LAYER M3 ;
      RECT 13.377 76.710 13.391 76.752 ;
    END
  END rw0_wmask_in[187]
  PIN rw0_wmask_in[188]
    DIRECTION INPUT ;
    USE SIGNAL ;
    SHAPE ABUTMENT ;
    PORT
      LAYER M3 ;
      RECT 13.601 76.710 13.615 76.752 ;
    END
  END rw0_wmask_in[188]
  PIN rw0_wmask_in[189]
    DIRECTION INPUT ;
    USE SIGNAL ;
    SHAPE ABUTMENT ;
    PORT
      LAYER M3 ;
      RECT 13.825 76.710 13.839 76.752 ;
    END
  END rw0_wmask_in[189]
  PIN rw0_wmask_in[190]
    DIRECTION INPUT ;
    USE SIGNAL ;
    SHAPE ABUTMENT ;
    PORT
      LAYER M3 ;
      RECT 14.049 76.710 14.063 76.752 ;
    END
  END rw0_wmask_in[190]
  PIN rw0_wmask_in[191]
    DIRECTION INPUT ;
    USE SIGNAL ;
    SHAPE ABUTMENT ;
    PORT
      LAYER M3 ;
      RECT 14.273 76.710 14.287 76.752 ;
    END
  END rw0_wmask_in[191]
  PIN rw0_wmask_in[192]
    DIRECTION INPUT ;
    USE SIGNAL ;
    SHAPE ABUTMENT ;
    PORT
      LAYER M3 ;
      RECT 14.497 76.710 14.511 76.752 ;
    END
  END rw0_wmask_in[192]
  PIN rw0_wmask_in[193]
    DIRECTION INPUT ;
    USE SIGNAL ;
    SHAPE ABUTMENT ;
    PORT
      LAYER M3 ;
      RECT 14.721 76.710 14.735 76.752 ;
    END
  END rw0_wmask_in[193]
  PIN rw0_wmask_in[194]
    DIRECTION INPUT ;
    USE SIGNAL ;
    SHAPE ABUTMENT ;
    PORT
      LAYER M3 ;
      RECT 14.945 76.710 14.959 76.752 ;
    END
  END rw0_wmask_in[194]
  PIN rw0_wmask_in[195]
    DIRECTION INPUT ;
    USE SIGNAL ;
    SHAPE ABUTMENT ;
    PORT
      LAYER M3 ;
      RECT 15.169 76.710 15.183 76.752 ;
    END
  END rw0_wmask_in[195]
  PIN rw0_wmask_in[196]
    DIRECTION INPUT ;
    USE SIGNAL ;
    SHAPE ABUTMENT ;
    PORT
      LAYER M3 ;
      RECT 15.393 76.710 15.407 76.752 ;
    END
  END rw0_wmask_in[196]
  PIN rw0_wmask_in[197]
    DIRECTION INPUT ;
    USE SIGNAL ;
    SHAPE ABUTMENT ;
    PORT
      LAYER M3 ;
      RECT 15.617 76.710 15.631 76.752 ;
    END
  END rw0_wmask_in[197]
  PIN rw0_wmask_in[198]
    DIRECTION INPUT ;
    USE SIGNAL ;
    SHAPE ABUTMENT ;
    PORT
      LAYER M3 ;
      RECT 15.841 76.710 15.855 76.752 ;
    END
  END rw0_wmask_in[198]
  PIN rw0_wmask_in[199]
    DIRECTION INPUT ;
    USE SIGNAL ;
    SHAPE ABUTMENT ;
    PORT
      LAYER M3 ;
      RECT 16.065 76.710 16.079 76.752 ;
    END
  END rw0_wmask_in[199]
  PIN rw0_wmask_in[200]
    DIRECTION INPUT ;
    USE SIGNAL ;
    SHAPE ABUTMENT ;
    PORT
      LAYER M3 ;
      RECT 16.289 76.710 16.303 76.752 ;
    END
  END rw0_wmask_in[200]
  PIN rw0_wmask_in[201]
    DIRECTION INPUT ;
    USE SIGNAL ;
    SHAPE ABUTMENT ;
    PORT
      LAYER M3 ;
      RECT 16.513 76.710 16.527 76.752 ;
    END
  END rw0_wmask_in[201]
  PIN rw0_wmask_in[202]
    DIRECTION INPUT ;
    USE SIGNAL ;
    SHAPE ABUTMENT ;
    PORT
      LAYER M3 ;
      RECT 16.737 76.710 16.751 76.752 ;
    END
  END rw0_wmask_in[202]
  PIN rw0_wmask_in[203]
    DIRECTION INPUT ;
    USE SIGNAL ;
    SHAPE ABUTMENT ;
    PORT
      LAYER M3 ;
      RECT 16.961 76.710 16.975 76.752 ;
    END
  END rw0_wmask_in[203]
  PIN rw0_wmask_in[204]
    DIRECTION INPUT ;
    USE SIGNAL ;
    SHAPE ABUTMENT ;
    PORT
      LAYER M3 ;
      RECT 17.185 76.710 17.199 76.752 ;
    END
  END rw0_wmask_in[204]
  PIN rw0_wmask_in[205]
    DIRECTION INPUT ;
    USE SIGNAL ;
    SHAPE ABUTMENT ;
    PORT
      LAYER M3 ;
      RECT 17.409 76.710 17.423 76.752 ;
    END
  END rw0_wmask_in[205]
  PIN rw0_wmask_in[206]
    DIRECTION INPUT ;
    USE SIGNAL ;
    SHAPE ABUTMENT ;
    PORT
      LAYER M3 ;
      RECT 17.633 76.710 17.647 76.752 ;
    END
  END rw0_wmask_in[206]
  PIN rw0_wmask_in[207]
    DIRECTION INPUT ;
    USE SIGNAL ;
    SHAPE ABUTMENT ;
    PORT
      LAYER M3 ;
      RECT 17.857 76.710 17.871 76.752 ;
    END
  END rw0_wmask_in[207]
  PIN rw0_wmask_in[208]
    DIRECTION INPUT ;
    USE SIGNAL ;
    SHAPE ABUTMENT ;
    PORT
      LAYER M3 ;
      RECT 18.081 76.710 18.095 76.752 ;
    END
  END rw0_wmask_in[208]
  PIN rw0_wmask_in[209]
    DIRECTION INPUT ;
    USE SIGNAL ;
    SHAPE ABUTMENT ;
    PORT
      LAYER M3 ;
      RECT 18.305 76.710 18.319 76.752 ;
    END
  END rw0_wmask_in[209]
  PIN rw0_wmask_in[210]
    DIRECTION INPUT ;
    USE SIGNAL ;
    SHAPE ABUTMENT ;
    PORT
      LAYER M3 ;
      RECT 18.529 76.710 18.543 76.752 ;
    END
  END rw0_wmask_in[210]
  PIN rw0_wmask_in[211]
    DIRECTION INPUT ;
    USE SIGNAL ;
    SHAPE ABUTMENT ;
    PORT
      LAYER M3 ;
      RECT 18.753 76.710 18.767 76.752 ;
    END
  END rw0_wmask_in[211]
  PIN rw0_wmask_in[212]
    DIRECTION INPUT ;
    USE SIGNAL ;
    SHAPE ABUTMENT ;
    PORT
      LAYER M3 ;
      RECT 18.977 76.710 18.991 76.752 ;
    END
  END rw0_wmask_in[212]
  PIN rw0_wmask_in[213]
    DIRECTION INPUT ;
    USE SIGNAL ;
    SHAPE ABUTMENT ;
    PORT
      LAYER M3 ;
      RECT 19.201 76.710 19.215 76.752 ;
    END
  END rw0_wmask_in[213]
  PIN rw0_wmask_in[214]
    DIRECTION INPUT ;
    USE SIGNAL ;
    SHAPE ABUTMENT ;
    PORT
      LAYER M3 ;
      RECT 19.425 76.710 19.439 76.752 ;
    END
  END rw0_wmask_in[214]
  PIN rw0_wmask_in[215]
    DIRECTION INPUT ;
    USE SIGNAL ;
    SHAPE ABUTMENT ;
    PORT
      LAYER M3 ;
      RECT 19.649 76.710 19.663 76.752 ;
    END
  END rw0_wmask_in[215]
  PIN rw0_wmask_in[216]
    DIRECTION INPUT ;
    USE SIGNAL ;
    SHAPE ABUTMENT ;
    PORT
      LAYER M3 ;
      RECT 19.873 76.710 19.887 76.752 ;
    END
  END rw0_wmask_in[216]
  PIN rw0_wmask_in[217]
    DIRECTION INPUT ;
    USE SIGNAL ;
    SHAPE ABUTMENT ;
    PORT
      LAYER M3 ;
      RECT 20.097 76.710 20.111 76.752 ;
    END
  END rw0_wmask_in[217]
  PIN rw0_wmask_in[218]
    DIRECTION INPUT ;
    USE SIGNAL ;
    SHAPE ABUTMENT ;
    PORT
      LAYER M3 ;
      RECT 20.321 76.710 20.335 76.752 ;
    END
  END rw0_wmask_in[218]
  PIN rw0_wmask_in[219]
    DIRECTION INPUT ;
    USE SIGNAL ;
    SHAPE ABUTMENT ;
    PORT
      LAYER M3 ;
      RECT 20.545 76.710 20.559 76.752 ;
    END
  END rw0_wmask_in[219]
  PIN rw0_wmask_in[220]
    DIRECTION INPUT ;
    USE SIGNAL ;
    SHAPE ABUTMENT ;
    PORT
      LAYER M3 ;
      RECT 20.769 76.710 20.783 76.752 ;
    END
  END rw0_wmask_in[220]
  PIN rw0_wmask_in[221]
    DIRECTION INPUT ;
    USE SIGNAL ;
    SHAPE ABUTMENT ;
    PORT
      LAYER M3 ;
      RECT 20.993 76.710 21.007 76.752 ;
    END
  END rw0_wmask_in[221]
  PIN rw0_wmask_in[222]
    DIRECTION INPUT ;
    USE SIGNAL ;
    SHAPE ABUTMENT ;
    PORT
      LAYER M3 ;
      RECT 21.217 76.710 21.231 76.752 ;
    END
  END rw0_wmask_in[222]
  PIN rw0_wmask_in[223]
    DIRECTION INPUT ;
    USE SIGNAL ;
    SHAPE ABUTMENT ;
    PORT
      LAYER M3 ;
      RECT 21.441 76.710 21.455 76.752 ;
    END
  END rw0_wmask_in[223]
  PIN rw0_wmask_in[224]
    DIRECTION INPUT ;
    USE SIGNAL ;
    SHAPE ABUTMENT ;
    PORT
      LAYER M3 ;
      RECT 21.665 76.710 21.679 76.752 ;
    END
  END rw0_wmask_in[224]
  PIN rw0_wmask_in[225]
    DIRECTION INPUT ;
    USE SIGNAL ;
    SHAPE ABUTMENT ;
    PORT
      LAYER M3 ;
      RECT 21.889 76.710 21.903 76.752 ;
    END
  END rw0_wmask_in[225]
  PIN rw0_wmask_in[226]
    DIRECTION INPUT ;
    USE SIGNAL ;
    SHAPE ABUTMENT ;
    PORT
      LAYER M3 ;
      RECT 22.113 76.710 22.127 76.752 ;
    END
  END rw0_wmask_in[226]
  PIN rw0_wmask_in[227]
    DIRECTION INPUT ;
    USE SIGNAL ;
    SHAPE ABUTMENT ;
    PORT
      LAYER M3 ;
      RECT 22.337 76.710 22.351 76.752 ;
    END
  END rw0_wmask_in[227]
  PIN rw0_wmask_in[228]
    DIRECTION INPUT ;
    USE SIGNAL ;
    SHAPE ABUTMENT ;
    PORT
      LAYER M3 ;
      RECT 22.561 76.710 22.575 76.752 ;
    END
  END rw0_wmask_in[228]
  PIN rw0_wmask_in[229]
    DIRECTION INPUT ;
    USE SIGNAL ;
    SHAPE ABUTMENT ;
    PORT
      LAYER M3 ;
      RECT 22.785 76.710 22.799 76.752 ;
    END
  END rw0_wmask_in[229]
  PIN rw0_wmask_in[230]
    DIRECTION INPUT ;
    USE SIGNAL ;
    SHAPE ABUTMENT ;
    PORT
      LAYER M3 ;
      RECT 23.009 76.710 23.023 76.752 ;
    END
  END rw0_wmask_in[230]
  PIN rw0_wmask_in[231]
    DIRECTION INPUT ;
    USE SIGNAL ;
    SHAPE ABUTMENT ;
    PORT
      LAYER M3 ;
      RECT 23.233 76.710 23.247 76.752 ;
    END
  END rw0_wmask_in[231]
  PIN rw0_wmask_in[232]
    DIRECTION INPUT ;
    USE SIGNAL ;
    SHAPE ABUTMENT ;
    PORT
      LAYER M3 ;
      RECT 23.457 76.710 23.471 76.752 ;
    END
  END rw0_wmask_in[232]
  PIN rw0_wmask_in[233]
    DIRECTION INPUT ;
    USE SIGNAL ;
    SHAPE ABUTMENT ;
    PORT
      LAYER M3 ;
      RECT 23.681 76.710 23.695 76.752 ;
    END
  END rw0_wmask_in[233]
  PIN rw0_wmask_in[234]
    DIRECTION INPUT ;
    USE SIGNAL ;
    SHAPE ABUTMENT ;
    PORT
      LAYER M3 ;
      RECT 23.905 76.710 23.919 76.752 ;
    END
  END rw0_wmask_in[234]
  PIN rw0_wmask_in[235]
    DIRECTION INPUT ;
    USE SIGNAL ;
    SHAPE ABUTMENT ;
    PORT
      LAYER M3 ;
      RECT 24.129 76.710 24.143 76.752 ;
    END
  END rw0_wmask_in[235]
  PIN rw0_wmask_in[236]
    DIRECTION INPUT ;
    USE SIGNAL ;
    SHAPE ABUTMENT ;
    PORT
      LAYER M3 ;
      RECT 24.353 76.710 24.367 76.752 ;
    END
  END rw0_wmask_in[236]
  PIN rw0_wmask_in[237]
    DIRECTION INPUT ;
    USE SIGNAL ;
    SHAPE ABUTMENT ;
    PORT
      LAYER M3 ;
      RECT 24.577 76.710 24.591 76.752 ;
    END
  END rw0_wmask_in[237]
  PIN rw0_wmask_in[238]
    DIRECTION INPUT ;
    USE SIGNAL ;
    SHAPE ABUTMENT ;
    PORT
      LAYER M3 ;
      RECT 24.801 76.710 24.815 76.752 ;
    END
  END rw0_wmask_in[238]
  PIN rw0_wmask_in[239]
    DIRECTION INPUT ;
    USE SIGNAL ;
    SHAPE ABUTMENT ;
    PORT
      LAYER M3 ;
      RECT 25.025 76.710 25.039 76.752 ;
    END
  END rw0_wmask_in[239]
  PIN rw0_wmask_in[240]
    DIRECTION INPUT ;
    USE SIGNAL ;
    SHAPE ABUTMENT ;
    PORT
      LAYER M3 ;
      RECT 25.249 76.710 25.263 76.752 ;
    END
  END rw0_wmask_in[240]
  PIN rw0_wmask_in[241]
    DIRECTION INPUT ;
    USE SIGNAL ;
    SHAPE ABUTMENT ;
    PORT
      LAYER M3 ;
      RECT 25.473 76.710 25.487 76.752 ;
    END
  END rw0_wmask_in[241]
  PIN rw0_wmask_in[242]
    DIRECTION INPUT ;
    USE SIGNAL ;
    SHAPE ABUTMENT ;
    PORT
      LAYER M3 ;
      RECT 25.697 76.710 25.711 76.752 ;
    END
  END rw0_wmask_in[242]
  PIN rw0_wmask_in[243]
    DIRECTION INPUT ;
    USE SIGNAL ;
    SHAPE ABUTMENT ;
    PORT
      LAYER M3 ;
      RECT 25.921 76.710 25.935 76.752 ;
    END
  END rw0_wmask_in[243]
  PIN rw0_wmask_in[244]
    DIRECTION INPUT ;
    USE SIGNAL ;
    SHAPE ABUTMENT ;
    PORT
      LAYER M3 ;
      RECT 26.145 76.710 26.159 76.752 ;
    END
  END rw0_wmask_in[244]
  PIN rw0_wmask_in[245]
    DIRECTION INPUT ;
    USE SIGNAL ;
    SHAPE ABUTMENT ;
    PORT
      LAYER M3 ;
      RECT 26.369 76.710 26.383 76.752 ;
    END
  END rw0_wmask_in[245]
  PIN rw0_wmask_in[246]
    DIRECTION INPUT ;
    USE SIGNAL ;
    SHAPE ABUTMENT ;
    PORT
      LAYER M3 ;
      RECT 26.593 76.710 26.607 76.752 ;
    END
  END rw0_wmask_in[246]
  PIN rw0_wmask_in[247]
    DIRECTION INPUT ;
    USE SIGNAL ;
    SHAPE ABUTMENT ;
    PORT
      LAYER M3 ;
      RECT 26.817 76.710 26.831 76.752 ;
    END
  END rw0_wmask_in[247]
  PIN rw0_wmask_in[248]
    DIRECTION INPUT ;
    USE SIGNAL ;
    SHAPE ABUTMENT ;
    PORT
      LAYER M3 ;
      RECT 27.041 76.710 27.055 76.752 ;
    END
  END rw0_wmask_in[248]
  PIN rw0_wmask_in[249]
    DIRECTION INPUT ;
    USE SIGNAL ;
    SHAPE ABUTMENT ;
    PORT
      LAYER M3 ;
      RECT 27.265 76.710 27.279 76.752 ;
    END
  END rw0_wmask_in[249]
  PIN rw0_wmask_in[250]
    DIRECTION INPUT ;
    USE SIGNAL ;
    SHAPE ABUTMENT ;
    PORT
      LAYER M3 ;
      RECT 27.489 76.710 27.503 76.752 ;
    END
  END rw0_wmask_in[250]
  PIN rw0_wmask_in[251]
    DIRECTION INPUT ;
    USE SIGNAL ;
    SHAPE ABUTMENT ;
    PORT
      LAYER M3 ;
      RECT 27.713 76.710 27.727 76.752 ;
    END
  END rw0_wmask_in[251]
  PIN rw0_wmask_in[252]
    DIRECTION INPUT ;
    USE SIGNAL ;
    SHAPE ABUTMENT ;
    PORT
      LAYER M3 ;
      RECT 27.937 76.710 27.951 76.752 ;
    END
  END rw0_wmask_in[252]
  PIN rw0_wmask_in[253]
    DIRECTION INPUT ;
    USE SIGNAL ;
    SHAPE ABUTMENT ;
    PORT
      LAYER M3 ;
      RECT 28.161 76.710 28.175 76.752 ;
    END
  END rw0_wmask_in[253]
  PIN rw0_wmask_in[254]
    DIRECTION INPUT ;
    USE SIGNAL ;
    SHAPE ABUTMENT ;
    PORT
      LAYER M3 ;
      RECT 28.385 76.710 28.399 76.752 ;
    END
  END rw0_wmask_in[254]
  PIN rw0_wmask_in[255]
    DIRECTION INPUT ;
    USE SIGNAL ;
    SHAPE ABUTMENT ;
    PORT
      LAYER M3 ;
      RECT 28.609 76.710 28.623 76.752 ;
    END
  END rw0_wmask_in[255]
  PIN rw0_wd_in[0]
    DIRECTION INPUT ;
    USE SIGNAL ;
    SHAPE ABUTMENT ;
    PORT
      LAYER M2 ;
      RECT 0.000 37.002 0.036 37.014 ;
    END
  END rw0_wd_in[0]
  PIN rw0_wd_in[1]
    DIRECTION INPUT ;
    USE SIGNAL ;
    SHAPE ABUTMENT ;
    PORT
      LAYER M2 ;
      RECT 0.000 37.578 0.036 37.590 ;
    END
  END rw0_wd_in[1]
  PIN rw0_wd_in[2]
    DIRECTION INPUT ;
    USE SIGNAL ;
    SHAPE ABUTMENT ;
    PORT
      LAYER M2 ;
      RECT 0.000 38.154 0.036 38.166 ;
    END
  END rw0_wd_in[2]
  PIN rw0_wd_in[3]
    DIRECTION INPUT ;
    USE SIGNAL ;
    SHAPE ABUTMENT ;
    PORT
      LAYER M2 ;
      RECT 0.000 38.730 0.036 38.742 ;
    END
  END rw0_wd_in[3]
  PIN rw0_wd_in[4]
    DIRECTION INPUT ;
    USE SIGNAL ;
    SHAPE ABUTMENT ;
    PORT
      LAYER M2 ;
      RECT 0.000 39.306 0.036 39.318 ;
    END
  END rw0_wd_in[4]
  PIN rw0_wd_in[5]
    DIRECTION INPUT ;
    USE SIGNAL ;
    SHAPE ABUTMENT ;
    PORT
      LAYER M2 ;
      RECT 0.000 39.882 0.036 39.894 ;
    END
  END rw0_wd_in[5]
  PIN rw0_wd_in[6]
    DIRECTION INPUT ;
    USE SIGNAL ;
    SHAPE ABUTMENT ;
    PORT
      LAYER M2 ;
      RECT 0.000 40.458 0.036 40.470 ;
    END
  END rw0_wd_in[6]
  PIN rw0_wd_in[7]
    DIRECTION INPUT ;
    USE SIGNAL ;
    SHAPE ABUTMENT ;
    PORT
      LAYER M2 ;
      RECT 0.000 41.034 0.036 41.046 ;
    END
  END rw0_wd_in[7]
  PIN rw0_wd_in[8]
    DIRECTION INPUT ;
    USE SIGNAL ;
    SHAPE ABUTMENT ;
    PORT
      LAYER M2 ;
      RECT 0.000 41.610 0.036 41.622 ;
    END
  END rw0_wd_in[8]
  PIN rw0_wd_in[9]
    DIRECTION INPUT ;
    USE SIGNAL ;
    SHAPE ABUTMENT ;
    PORT
      LAYER M2 ;
      RECT 0.000 42.186 0.036 42.198 ;
    END
  END rw0_wd_in[9]
  PIN rw0_wd_in[10]
    DIRECTION INPUT ;
    USE SIGNAL ;
    SHAPE ABUTMENT ;
    PORT
      LAYER M2 ;
      RECT 0.000 42.762 0.036 42.774 ;
    END
  END rw0_wd_in[10]
  PIN rw0_wd_in[11]
    DIRECTION INPUT ;
    USE SIGNAL ;
    SHAPE ABUTMENT ;
    PORT
      LAYER M2 ;
      RECT 0.000 43.338 0.036 43.350 ;
    END
  END rw0_wd_in[11]
  PIN rw0_wd_in[12]
    DIRECTION INPUT ;
    USE SIGNAL ;
    SHAPE ABUTMENT ;
    PORT
      LAYER M2 ;
      RECT 0.000 43.914 0.036 43.926 ;
    END
  END rw0_wd_in[12]
  PIN rw0_wd_in[13]
    DIRECTION INPUT ;
    USE SIGNAL ;
    SHAPE ABUTMENT ;
    PORT
      LAYER M2 ;
      RECT 0.000 44.490 0.036 44.502 ;
    END
  END rw0_wd_in[13]
  PIN rw0_wd_in[14]
    DIRECTION INPUT ;
    USE SIGNAL ;
    SHAPE ABUTMENT ;
    PORT
      LAYER M2 ;
      RECT 0.000 45.066 0.036 45.078 ;
    END
  END rw0_wd_in[14]
  PIN rw0_wd_in[15]
    DIRECTION INPUT ;
    USE SIGNAL ;
    SHAPE ABUTMENT ;
    PORT
      LAYER M2 ;
      RECT 0.000 45.642 0.036 45.654 ;
    END
  END rw0_wd_in[15]
  PIN rw0_wd_in[16]
    DIRECTION INPUT ;
    USE SIGNAL ;
    SHAPE ABUTMENT ;
    PORT
      LAYER M2 ;
      RECT 0.000 46.218 0.036 46.230 ;
    END
  END rw0_wd_in[16]
  PIN rw0_wd_in[17]
    DIRECTION INPUT ;
    USE SIGNAL ;
    SHAPE ABUTMENT ;
    PORT
      LAYER M2 ;
      RECT 0.000 46.794 0.036 46.806 ;
    END
  END rw0_wd_in[17]
  PIN rw0_wd_in[18]
    DIRECTION INPUT ;
    USE SIGNAL ;
    SHAPE ABUTMENT ;
    PORT
      LAYER M2 ;
      RECT 0.000 47.370 0.036 47.382 ;
    END
  END rw0_wd_in[18]
  PIN rw0_wd_in[19]
    DIRECTION INPUT ;
    USE SIGNAL ;
    SHAPE ABUTMENT ;
    PORT
      LAYER M2 ;
      RECT 0.000 47.946 0.036 47.958 ;
    END
  END rw0_wd_in[19]
  PIN rw0_wd_in[20]
    DIRECTION INPUT ;
    USE SIGNAL ;
    SHAPE ABUTMENT ;
    PORT
      LAYER M2 ;
      RECT 0.000 48.522 0.036 48.534 ;
    END
  END rw0_wd_in[20]
  PIN rw0_wd_in[21]
    DIRECTION INPUT ;
    USE SIGNAL ;
    SHAPE ABUTMENT ;
    PORT
      LAYER M2 ;
      RECT 0.000 49.098 0.036 49.110 ;
    END
  END rw0_wd_in[21]
  PIN rw0_wd_in[22]
    DIRECTION INPUT ;
    USE SIGNAL ;
    SHAPE ABUTMENT ;
    PORT
      LAYER M2 ;
      RECT 0.000 49.674 0.036 49.686 ;
    END
  END rw0_wd_in[22]
  PIN rw0_wd_in[23]
    DIRECTION INPUT ;
    USE SIGNAL ;
    SHAPE ABUTMENT ;
    PORT
      LAYER M2 ;
      RECT 0.000 50.250 0.036 50.262 ;
    END
  END rw0_wd_in[23]
  PIN rw0_wd_in[24]
    DIRECTION INPUT ;
    USE SIGNAL ;
    SHAPE ABUTMENT ;
    PORT
      LAYER M2 ;
      RECT 0.000 50.826 0.036 50.838 ;
    END
  END rw0_wd_in[24]
  PIN rw0_wd_in[25]
    DIRECTION INPUT ;
    USE SIGNAL ;
    SHAPE ABUTMENT ;
    PORT
      LAYER M2 ;
      RECT 0.000 51.402 0.036 51.414 ;
    END
  END rw0_wd_in[25]
  PIN rw0_wd_in[26]
    DIRECTION INPUT ;
    USE SIGNAL ;
    SHAPE ABUTMENT ;
    PORT
      LAYER M2 ;
      RECT 0.000 51.978 0.036 51.990 ;
    END
  END rw0_wd_in[26]
  PIN rw0_wd_in[27]
    DIRECTION INPUT ;
    USE SIGNAL ;
    SHAPE ABUTMENT ;
    PORT
      LAYER M2 ;
      RECT 0.000 52.554 0.036 52.566 ;
    END
  END rw0_wd_in[27]
  PIN rw0_wd_in[28]
    DIRECTION INPUT ;
    USE SIGNAL ;
    SHAPE ABUTMENT ;
    PORT
      LAYER M2 ;
      RECT 0.000 53.130 0.036 53.142 ;
    END
  END rw0_wd_in[28]
  PIN rw0_wd_in[29]
    DIRECTION INPUT ;
    USE SIGNAL ;
    SHAPE ABUTMENT ;
    PORT
      LAYER M2 ;
      RECT 0.000 53.706 0.036 53.718 ;
    END
  END rw0_wd_in[29]
  PIN rw0_wd_in[30]
    DIRECTION INPUT ;
    USE SIGNAL ;
    SHAPE ABUTMENT ;
    PORT
      LAYER M2 ;
      RECT 0.000 54.282 0.036 54.294 ;
    END
  END rw0_wd_in[30]
  PIN rw0_wd_in[31]
    DIRECTION INPUT ;
    USE SIGNAL ;
    SHAPE ABUTMENT ;
    PORT
      LAYER M2 ;
      RECT 0.000 54.858 0.036 54.870 ;
    END
  END rw0_wd_in[31]
  PIN rw0_wd_in[32]
    DIRECTION INPUT ;
    USE SIGNAL ;
    SHAPE ABUTMENT ;
    PORT
      LAYER M2 ;
      RECT 0.000 55.434 0.036 55.446 ;
    END
  END rw0_wd_in[32]
  PIN rw0_wd_in[33]
    DIRECTION INPUT ;
    USE SIGNAL ;
    SHAPE ABUTMENT ;
    PORT
      LAYER M2 ;
      RECT 0.000 56.010 0.036 56.022 ;
    END
  END rw0_wd_in[33]
  PIN rw0_wd_in[34]
    DIRECTION INPUT ;
    USE SIGNAL ;
    SHAPE ABUTMENT ;
    PORT
      LAYER M2 ;
      RECT 0.000 56.586 0.036 56.598 ;
    END
  END rw0_wd_in[34]
  PIN rw0_wd_in[35]
    DIRECTION INPUT ;
    USE SIGNAL ;
    SHAPE ABUTMENT ;
    PORT
      LAYER M2 ;
      RECT 0.000 57.162 0.036 57.174 ;
    END
  END rw0_wd_in[35]
  PIN rw0_wd_in[36]
    DIRECTION INPUT ;
    USE SIGNAL ;
    SHAPE ABUTMENT ;
    PORT
      LAYER M2 ;
      RECT 0.000 57.738 0.036 57.750 ;
    END
  END rw0_wd_in[36]
  PIN rw0_wd_in[37]
    DIRECTION INPUT ;
    USE SIGNAL ;
    SHAPE ABUTMENT ;
    PORT
      LAYER M2 ;
      RECT 0.000 58.314 0.036 58.326 ;
    END
  END rw0_wd_in[37]
  PIN rw0_wd_in[38]
    DIRECTION INPUT ;
    USE SIGNAL ;
    SHAPE ABUTMENT ;
    PORT
      LAYER M2 ;
      RECT 0.000 58.890 0.036 58.902 ;
    END
  END rw0_wd_in[38]
  PIN rw0_wd_in[39]
    DIRECTION INPUT ;
    USE SIGNAL ;
    SHAPE ABUTMENT ;
    PORT
      LAYER M2 ;
      RECT 0.000 59.466 0.036 59.478 ;
    END
  END rw0_wd_in[39]
  PIN rw0_wd_in[40]
    DIRECTION INPUT ;
    USE SIGNAL ;
    SHAPE ABUTMENT ;
    PORT
      LAYER M2 ;
      RECT 0.000 60.042 0.036 60.054 ;
    END
  END rw0_wd_in[40]
  PIN rw0_wd_in[41]
    DIRECTION INPUT ;
    USE SIGNAL ;
    SHAPE ABUTMENT ;
    PORT
      LAYER M2 ;
      RECT 0.000 60.618 0.036 60.630 ;
    END
  END rw0_wd_in[41]
  PIN rw0_wd_in[42]
    DIRECTION INPUT ;
    USE SIGNAL ;
    SHAPE ABUTMENT ;
    PORT
      LAYER M2 ;
      RECT 0.000 61.194 0.036 61.206 ;
    END
  END rw0_wd_in[42]
  PIN rw0_wd_in[43]
    DIRECTION INPUT ;
    USE SIGNAL ;
    SHAPE ABUTMENT ;
    PORT
      LAYER M2 ;
      RECT 0.000 61.770 0.036 61.782 ;
    END
  END rw0_wd_in[43]
  PIN rw0_wd_in[44]
    DIRECTION INPUT ;
    USE SIGNAL ;
    SHAPE ABUTMENT ;
    PORT
      LAYER M2 ;
      RECT 0.000 62.346 0.036 62.358 ;
    END
  END rw0_wd_in[44]
  PIN rw0_wd_in[45]
    DIRECTION INPUT ;
    USE SIGNAL ;
    SHAPE ABUTMENT ;
    PORT
      LAYER M2 ;
      RECT 0.000 62.922 0.036 62.934 ;
    END
  END rw0_wd_in[45]
  PIN rw0_wd_in[46]
    DIRECTION INPUT ;
    USE SIGNAL ;
    SHAPE ABUTMENT ;
    PORT
      LAYER M2 ;
      RECT 0.000 63.498 0.036 63.510 ;
    END
  END rw0_wd_in[46]
  PIN rw0_wd_in[47]
    DIRECTION INPUT ;
    USE SIGNAL ;
    SHAPE ABUTMENT ;
    PORT
      LAYER M2 ;
      RECT 0.000 64.074 0.036 64.086 ;
    END
  END rw0_wd_in[47]
  PIN rw0_wd_in[48]
    DIRECTION INPUT ;
    USE SIGNAL ;
    SHAPE ABUTMENT ;
    PORT
      LAYER M2 ;
      RECT 0.000 64.650 0.036 64.662 ;
    END
  END rw0_wd_in[48]
  PIN rw0_wd_in[49]
    DIRECTION INPUT ;
    USE SIGNAL ;
    SHAPE ABUTMENT ;
    PORT
      LAYER M2 ;
      RECT 0.000 65.226 0.036 65.238 ;
    END
  END rw0_wd_in[49]
  PIN rw0_wd_in[50]
    DIRECTION INPUT ;
    USE SIGNAL ;
    SHAPE ABUTMENT ;
    PORT
      LAYER M2 ;
      RECT 0.000 65.802 0.036 65.814 ;
    END
  END rw0_wd_in[50]
  PIN rw0_wd_in[51]
    DIRECTION INPUT ;
    USE SIGNAL ;
    SHAPE ABUTMENT ;
    PORT
      LAYER M2 ;
      RECT 0.000 66.378 0.036 66.390 ;
    END
  END rw0_wd_in[51]
  PIN rw0_wd_in[52]
    DIRECTION INPUT ;
    USE SIGNAL ;
    SHAPE ABUTMENT ;
    PORT
      LAYER M2 ;
      RECT 0.000 66.954 0.036 66.966 ;
    END
  END rw0_wd_in[52]
  PIN rw0_wd_in[53]
    DIRECTION INPUT ;
    USE SIGNAL ;
    SHAPE ABUTMENT ;
    PORT
      LAYER M2 ;
      RECT 0.000 67.530 0.036 67.542 ;
    END
  END rw0_wd_in[53]
  PIN rw0_wd_in[54]
    DIRECTION INPUT ;
    USE SIGNAL ;
    SHAPE ABUTMENT ;
    PORT
      LAYER M2 ;
      RECT 0.000 68.106 0.036 68.118 ;
    END
  END rw0_wd_in[54]
  PIN rw0_wd_in[55]
    DIRECTION INPUT ;
    USE SIGNAL ;
    SHAPE ABUTMENT ;
    PORT
      LAYER M2 ;
      RECT 0.000 68.682 0.036 68.694 ;
    END
  END rw0_wd_in[55]
  PIN rw0_wd_in[56]
    DIRECTION INPUT ;
    USE SIGNAL ;
    SHAPE ABUTMENT ;
    PORT
      LAYER M2 ;
      RECT 0.000 69.258 0.036 69.270 ;
    END
  END rw0_wd_in[56]
  PIN rw0_wd_in[57]
    DIRECTION INPUT ;
    USE SIGNAL ;
    SHAPE ABUTMENT ;
    PORT
      LAYER M2 ;
      RECT 0.000 69.834 0.036 69.846 ;
    END
  END rw0_wd_in[57]
  PIN rw0_wd_in[58]
    DIRECTION INPUT ;
    USE SIGNAL ;
    SHAPE ABUTMENT ;
    PORT
      LAYER M2 ;
      RECT 0.000 70.410 0.036 70.422 ;
    END
  END rw0_wd_in[58]
  PIN rw0_wd_in[59]
    DIRECTION INPUT ;
    USE SIGNAL ;
    SHAPE ABUTMENT ;
    PORT
      LAYER M2 ;
      RECT 0.000 70.986 0.036 70.998 ;
    END
  END rw0_wd_in[59]
  PIN rw0_wd_in[60]
    DIRECTION INPUT ;
    USE SIGNAL ;
    SHAPE ABUTMENT ;
    PORT
      LAYER M2 ;
      RECT 0.000 71.562 0.036 71.574 ;
    END
  END rw0_wd_in[60]
  PIN rw0_wd_in[61]
    DIRECTION INPUT ;
    USE SIGNAL ;
    SHAPE ABUTMENT ;
    PORT
      LAYER M2 ;
      RECT 0.000 72.138 0.036 72.150 ;
    END
  END rw0_wd_in[61]
  PIN rw0_wd_in[62]
    DIRECTION INPUT ;
    USE SIGNAL ;
    SHAPE ABUTMENT ;
    PORT
      LAYER M2 ;
      RECT 0.000 72.714 0.036 72.726 ;
    END
  END rw0_wd_in[62]
  PIN rw0_wd_in[63]
    DIRECTION INPUT ;
    USE SIGNAL ;
    SHAPE ABUTMENT ;
    PORT
      LAYER M2 ;
      RECT 0.000 73.290 0.036 73.302 ;
    END
  END rw0_wd_in[63]
  PIN rw0_wd_in[64]
    DIRECTION INPUT ;
    USE SIGNAL ;
    SHAPE ABUTMENT ;
    PORT
      LAYER M2 ;
      RECT 61.326 37.002 61.362 37.014 ;
    END
  END rw0_wd_in[64]
  PIN rw0_wd_in[65]
    DIRECTION INPUT ;
    USE SIGNAL ;
    SHAPE ABUTMENT ;
    PORT
      LAYER M2 ;
      RECT 61.326 37.578 61.362 37.590 ;
    END
  END rw0_wd_in[65]
  PIN rw0_wd_in[66]
    DIRECTION INPUT ;
    USE SIGNAL ;
    SHAPE ABUTMENT ;
    PORT
      LAYER M2 ;
      RECT 61.326 38.154 61.362 38.166 ;
    END
  END rw0_wd_in[66]
  PIN rw0_wd_in[67]
    DIRECTION INPUT ;
    USE SIGNAL ;
    SHAPE ABUTMENT ;
    PORT
      LAYER M2 ;
      RECT 61.326 38.730 61.362 38.742 ;
    END
  END rw0_wd_in[67]
  PIN rw0_wd_in[68]
    DIRECTION INPUT ;
    USE SIGNAL ;
    SHAPE ABUTMENT ;
    PORT
      LAYER M2 ;
      RECT 61.326 39.306 61.362 39.318 ;
    END
  END rw0_wd_in[68]
  PIN rw0_wd_in[69]
    DIRECTION INPUT ;
    USE SIGNAL ;
    SHAPE ABUTMENT ;
    PORT
      LAYER M2 ;
      RECT 61.326 39.882 61.362 39.894 ;
    END
  END rw0_wd_in[69]
  PIN rw0_wd_in[70]
    DIRECTION INPUT ;
    USE SIGNAL ;
    SHAPE ABUTMENT ;
    PORT
      LAYER M2 ;
      RECT 61.326 40.458 61.362 40.470 ;
    END
  END rw0_wd_in[70]
  PIN rw0_wd_in[71]
    DIRECTION INPUT ;
    USE SIGNAL ;
    SHAPE ABUTMENT ;
    PORT
      LAYER M2 ;
      RECT 61.326 41.034 61.362 41.046 ;
    END
  END rw0_wd_in[71]
  PIN rw0_wd_in[72]
    DIRECTION INPUT ;
    USE SIGNAL ;
    SHAPE ABUTMENT ;
    PORT
      LAYER M2 ;
      RECT 61.326 41.610 61.362 41.622 ;
    END
  END rw0_wd_in[72]
  PIN rw0_wd_in[73]
    DIRECTION INPUT ;
    USE SIGNAL ;
    SHAPE ABUTMENT ;
    PORT
      LAYER M2 ;
      RECT 61.326 42.186 61.362 42.198 ;
    END
  END rw0_wd_in[73]
  PIN rw0_wd_in[74]
    DIRECTION INPUT ;
    USE SIGNAL ;
    SHAPE ABUTMENT ;
    PORT
      LAYER M2 ;
      RECT 61.326 42.762 61.362 42.774 ;
    END
  END rw0_wd_in[74]
  PIN rw0_wd_in[75]
    DIRECTION INPUT ;
    USE SIGNAL ;
    SHAPE ABUTMENT ;
    PORT
      LAYER M2 ;
      RECT 61.326 43.338 61.362 43.350 ;
    END
  END rw0_wd_in[75]
  PIN rw0_wd_in[76]
    DIRECTION INPUT ;
    USE SIGNAL ;
    SHAPE ABUTMENT ;
    PORT
      LAYER M2 ;
      RECT 61.326 43.914 61.362 43.926 ;
    END
  END rw0_wd_in[76]
  PIN rw0_wd_in[77]
    DIRECTION INPUT ;
    USE SIGNAL ;
    SHAPE ABUTMENT ;
    PORT
      LAYER M2 ;
      RECT 61.326 44.490 61.362 44.502 ;
    END
  END rw0_wd_in[77]
  PIN rw0_wd_in[78]
    DIRECTION INPUT ;
    USE SIGNAL ;
    SHAPE ABUTMENT ;
    PORT
      LAYER M2 ;
      RECT 61.326 45.066 61.362 45.078 ;
    END
  END rw0_wd_in[78]
  PIN rw0_wd_in[79]
    DIRECTION INPUT ;
    USE SIGNAL ;
    SHAPE ABUTMENT ;
    PORT
      LAYER M2 ;
      RECT 61.326 45.642 61.362 45.654 ;
    END
  END rw0_wd_in[79]
  PIN rw0_wd_in[80]
    DIRECTION INPUT ;
    USE SIGNAL ;
    SHAPE ABUTMENT ;
    PORT
      LAYER M2 ;
      RECT 61.326 46.218 61.362 46.230 ;
    END
  END rw0_wd_in[80]
  PIN rw0_wd_in[81]
    DIRECTION INPUT ;
    USE SIGNAL ;
    SHAPE ABUTMENT ;
    PORT
      LAYER M2 ;
      RECT 61.326 46.794 61.362 46.806 ;
    END
  END rw0_wd_in[81]
  PIN rw0_wd_in[82]
    DIRECTION INPUT ;
    USE SIGNAL ;
    SHAPE ABUTMENT ;
    PORT
      LAYER M2 ;
      RECT 61.326 47.370 61.362 47.382 ;
    END
  END rw0_wd_in[82]
  PIN rw0_wd_in[83]
    DIRECTION INPUT ;
    USE SIGNAL ;
    SHAPE ABUTMENT ;
    PORT
      LAYER M2 ;
      RECT 61.326 47.946 61.362 47.958 ;
    END
  END rw0_wd_in[83]
  PIN rw0_wd_in[84]
    DIRECTION INPUT ;
    USE SIGNAL ;
    SHAPE ABUTMENT ;
    PORT
      LAYER M2 ;
      RECT 61.326 48.522 61.362 48.534 ;
    END
  END rw0_wd_in[84]
  PIN rw0_wd_in[85]
    DIRECTION INPUT ;
    USE SIGNAL ;
    SHAPE ABUTMENT ;
    PORT
      LAYER M2 ;
      RECT 61.326 49.098 61.362 49.110 ;
    END
  END rw0_wd_in[85]
  PIN rw0_wd_in[86]
    DIRECTION INPUT ;
    USE SIGNAL ;
    SHAPE ABUTMENT ;
    PORT
      LAYER M2 ;
      RECT 61.326 49.674 61.362 49.686 ;
    END
  END rw0_wd_in[86]
  PIN rw0_wd_in[87]
    DIRECTION INPUT ;
    USE SIGNAL ;
    SHAPE ABUTMENT ;
    PORT
      LAYER M2 ;
      RECT 61.326 50.250 61.362 50.262 ;
    END
  END rw0_wd_in[87]
  PIN rw0_wd_in[88]
    DIRECTION INPUT ;
    USE SIGNAL ;
    SHAPE ABUTMENT ;
    PORT
      LAYER M2 ;
      RECT 61.326 50.826 61.362 50.838 ;
    END
  END rw0_wd_in[88]
  PIN rw0_wd_in[89]
    DIRECTION INPUT ;
    USE SIGNAL ;
    SHAPE ABUTMENT ;
    PORT
      LAYER M2 ;
      RECT 61.326 51.402 61.362 51.414 ;
    END
  END rw0_wd_in[89]
  PIN rw0_wd_in[90]
    DIRECTION INPUT ;
    USE SIGNAL ;
    SHAPE ABUTMENT ;
    PORT
      LAYER M2 ;
      RECT 61.326 51.978 61.362 51.990 ;
    END
  END rw0_wd_in[90]
  PIN rw0_wd_in[91]
    DIRECTION INPUT ;
    USE SIGNAL ;
    SHAPE ABUTMENT ;
    PORT
      LAYER M2 ;
      RECT 61.326 52.554 61.362 52.566 ;
    END
  END rw0_wd_in[91]
  PIN rw0_wd_in[92]
    DIRECTION INPUT ;
    USE SIGNAL ;
    SHAPE ABUTMENT ;
    PORT
      LAYER M2 ;
      RECT 61.326 53.130 61.362 53.142 ;
    END
  END rw0_wd_in[92]
  PIN rw0_wd_in[93]
    DIRECTION INPUT ;
    USE SIGNAL ;
    SHAPE ABUTMENT ;
    PORT
      LAYER M2 ;
      RECT 61.326 53.706 61.362 53.718 ;
    END
  END rw0_wd_in[93]
  PIN rw0_wd_in[94]
    DIRECTION INPUT ;
    USE SIGNAL ;
    SHAPE ABUTMENT ;
    PORT
      LAYER M2 ;
      RECT 61.326 54.282 61.362 54.294 ;
    END
  END rw0_wd_in[94]
  PIN rw0_wd_in[95]
    DIRECTION INPUT ;
    USE SIGNAL ;
    SHAPE ABUTMENT ;
    PORT
      LAYER M2 ;
      RECT 61.326 54.858 61.362 54.870 ;
    END
  END rw0_wd_in[95]
  PIN rw0_wd_in[96]
    DIRECTION INPUT ;
    USE SIGNAL ;
    SHAPE ABUTMENT ;
    PORT
      LAYER M2 ;
      RECT 61.326 55.434 61.362 55.446 ;
    END
  END rw0_wd_in[96]
  PIN rw0_wd_in[97]
    DIRECTION INPUT ;
    USE SIGNAL ;
    SHAPE ABUTMENT ;
    PORT
      LAYER M2 ;
      RECT 61.326 56.010 61.362 56.022 ;
    END
  END rw0_wd_in[97]
  PIN rw0_wd_in[98]
    DIRECTION INPUT ;
    USE SIGNAL ;
    SHAPE ABUTMENT ;
    PORT
      LAYER M2 ;
      RECT 61.326 56.586 61.362 56.598 ;
    END
  END rw0_wd_in[98]
  PIN rw0_wd_in[99]
    DIRECTION INPUT ;
    USE SIGNAL ;
    SHAPE ABUTMENT ;
    PORT
      LAYER M2 ;
      RECT 61.326 57.162 61.362 57.174 ;
    END
  END rw0_wd_in[99]
  PIN rw0_wd_in[100]
    DIRECTION INPUT ;
    USE SIGNAL ;
    SHAPE ABUTMENT ;
    PORT
      LAYER M2 ;
      RECT 61.326 57.738 61.362 57.750 ;
    END
  END rw0_wd_in[100]
  PIN rw0_wd_in[101]
    DIRECTION INPUT ;
    USE SIGNAL ;
    SHAPE ABUTMENT ;
    PORT
      LAYER M2 ;
      RECT 61.326 58.314 61.362 58.326 ;
    END
  END rw0_wd_in[101]
  PIN rw0_wd_in[102]
    DIRECTION INPUT ;
    USE SIGNAL ;
    SHAPE ABUTMENT ;
    PORT
      LAYER M2 ;
      RECT 61.326 58.890 61.362 58.902 ;
    END
  END rw0_wd_in[102]
  PIN rw0_wd_in[103]
    DIRECTION INPUT ;
    USE SIGNAL ;
    SHAPE ABUTMENT ;
    PORT
      LAYER M2 ;
      RECT 61.326 59.466 61.362 59.478 ;
    END
  END rw0_wd_in[103]
  PIN rw0_wd_in[104]
    DIRECTION INPUT ;
    USE SIGNAL ;
    SHAPE ABUTMENT ;
    PORT
      LAYER M2 ;
      RECT 61.326 60.042 61.362 60.054 ;
    END
  END rw0_wd_in[104]
  PIN rw0_wd_in[105]
    DIRECTION INPUT ;
    USE SIGNAL ;
    SHAPE ABUTMENT ;
    PORT
      LAYER M2 ;
      RECT 61.326 60.618 61.362 60.630 ;
    END
  END rw0_wd_in[105]
  PIN rw0_wd_in[106]
    DIRECTION INPUT ;
    USE SIGNAL ;
    SHAPE ABUTMENT ;
    PORT
      LAYER M2 ;
      RECT 61.326 61.194 61.362 61.206 ;
    END
  END rw0_wd_in[106]
  PIN rw0_wd_in[107]
    DIRECTION INPUT ;
    USE SIGNAL ;
    SHAPE ABUTMENT ;
    PORT
      LAYER M2 ;
      RECT 61.326 61.770 61.362 61.782 ;
    END
  END rw0_wd_in[107]
  PIN rw0_wd_in[108]
    DIRECTION INPUT ;
    USE SIGNAL ;
    SHAPE ABUTMENT ;
    PORT
      LAYER M2 ;
      RECT 61.326 62.346 61.362 62.358 ;
    END
  END rw0_wd_in[108]
  PIN rw0_wd_in[109]
    DIRECTION INPUT ;
    USE SIGNAL ;
    SHAPE ABUTMENT ;
    PORT
      LAYER M2 ;
      RECT 61.326 62.922 61.362 62.934 ;
    END
  END rw0_wd_in[109]
  PIN rw0_wd_in[110]
    DIRECTION INPUT ;
    USE SIGNAL ;
    SHAPE ABUTMENT ;
    PORT
      LAYER M2 ;
      RECT 61.326 63.498 61.362 63.510 ;
    END
  END rw0_wd_in[110]
  PIN rw0_wd_in[111]
    DIRECTION INPUT ;
    USE SIGNAL ;
    SHAPE ABUTMENT ;
    PORT
      LAYER M2 ;
      RECT 61.326 64.074 61.362 64.086 ;
    END
  END rw0_wd_in[111]
  PIN rw0_wd_in[112]
    DIRECTION INPUT ;
    USE SIGNAL ;
    SHAPE ABUTMENT ;
    PORT
      LAYER M2 ;
      RECT 61.326 64.650 61.362 64.662 ;
    END
  END rw0_wd_in[112]
  PIN rw0_wd_in[113]
    DIRECTION INPUT ;
    USE SIGNAL ;
    SHAPE ABUTMENT ;
    PORT
      LAYER M2 ;
      RECT 61.326 65.226 61.362 65.238 ;
    END
  END rw0_wd_in[113]
  PIN rw0_wd_in[114]
    DIRECTION INPUT ;
    USE SIGNAL ;
    SHAPE ABUTMENT ;
    PORT
      LAYER M2 ;
      RECT 61.326 65.802 61.362 65.814 ;
    END
  END rw0_wd_in[114]
  PIN rw0_wd_in[115]
    DIRECTION INPUT ;
    USE SIGNAL ;
    SHAPE ABUTMENT ;
    PORT
      LAYER M2 ;
      RECT 61.326 66.378 61.362 66.390 ;
    END
  END rw0_wd_in[115]
  PIN rw0_wd_in[116]
    DIRECTION INPUT ;
    USE SIGNAL ;
    SHAPE ABUTMENT ;
    PORT
      LAYER M2 ;
      RECT 61.326 66.954 61.362 66.966 ;
    END
  END rw0_wd_in[116]
  PIN rw0_wd_in[117]
    DIRECTION INPUT ;
    USE SIGNAL ;
    SHAPE ABUTMENT ;
    PORT
      LAYER M2 ;
      RECT 61.326 67.530 61.362 67.542 ;
    END
  END rw0_wd_in[117]
  PIN rw0_wd_in[118]
    DIRECTION INPUT ;
    USE SIGNAL ;
    SHAPE ABUTMENT ;
    PORT
      LAYER M2 ;
      RECT 61.326 68.106 61.362 68.118 ;
    END
  END rw0_wd_in[118]
  PIN rw0_wd_in[119]
    DIRECTION INPUT ;
    USE SIGNAL ;
    SHAPE ABUTMENT ;
    PORT
      LAYER M2 ;
      RECT 61.326 68.682 61.362 68.694 ;
    END
  END rw0_wd_in[119]
  PIN rw0_wd_in[120]
    DIRECTION INPUT ;
    USE SIGNAL ;
    SHAPE ABUTMENT ;
    PORT
      LAYER M2 ;
      RECT 61.326 69.258 61.362 69.270 ;
    END
  END rw0_wd_in[120]
  PIN rw0_wd_in[121]
    DIRECTION INPUT ;
    USE SIGNAL ;
    SHAPE ABUTMENT ;
    PORT
      LAYER M2 ;
      RECT 61.326 69.834 61.362 69.846 ;
    END
  END rw0_wd_in[121]
  PIN rw0_wd_in[122]
    DIRECTION INPUT ;
    USE SIGNAL ;
    SHAPE ABUTMENT ;
    PORT
      LAYER M2 ;
      RECT 61.326 70.410 61.362 70.422 ;
    END
  END rw0_wd_in[122]
  PIN rw0_wd_in[123]
    DIRECTION INPUT ;
    USE SIGNAL ;
    SHAPE ABUTMENT ;
    PORT
      LAYER M2 ;
      RECT 61.326 70.986 61.362 70.998 ;
    END
  END rw0_wd_in[123]
  PIN rw0_wd_in[124]
    DIRECTION INPUT ;
    USE SIGNAL ;
    SHAPE ABUTMENT ;
    PORT
      LAYER M2 ;
      RECT 61.326 71.562 61.362 71.574 ;
    END
  END rw0_wd_in[124]
  PIN rw0_wd_in[125]
    DIRECTION INPUT ;
    USE SIGNAL ;
    SHAPE ABUTMENT ;
    PORT
      LAYER M2 ;
      RECT 61.326 72.138 61.362 72.150 ;
    END
  END rw0_wd_in[125]
  PIN rw0_wd_in[126]
    DIRECTION INPUT ;
    USE SIGNAL ;
    SHAPE ABUTMENT ;
    PORT
      LAYER M2 ;
      RECT 61.326 72.714 61.362 72.726 ;
    END
  END rw0_wd_in[126]
  PIN rw0_wd_in[127]
    DIRECTION INPUT ;
    USE SIGNAL ;
    SHAPE ABUTMENT ;
    PORT
      LAYER M2 ;
      RECT 61.326 73.290 61.362 73.302 ;
    END
  END rw0_wd_in[127]
  PIN rw0_wd_in[128]
    DIRECTION INPUT ;
    USE SIGNAL ;
    SHAPE ABUTMENT ;
    PORT
      LAYER M3 ;
      RECT 0.161 0.000 0.175 0.042 ;
    END
  END rw0_wd_in[128]
  PIN rw0_wd_in[129]
    DIRECTION INPUT ;
    USE SIGNAL ;
    SHAPE ABUTMENT ;
    PORT
      LAYER M3 ;
      RECT 0.385 0.000 0.399 0.042 ;
    END
  END rw0_wd_in[129]
  PIN rw0_wd_in[130]
    DIRECTION INPUT ;
    USE SIGNAL ;
    SHAPE ABUTMENT ;
    PORT
      LAYER M3 ;
      RECT 0.609 0.000 0.623 0.042 ;
    END
  END rw0_wd_in[130]
  PIN rw0_wd_in[131]
    DIRECTION INPUT ;
    USE SIGNAL ;
    SHAPE ABUTMENT ;
    PORT
      LAYER M3 ;
      RECT 0.833 0.000 0.847 0.042 ;
    END
  END rw0_wd_in[131]
  PIN rw0_wd_in[132]
    DIRECTION INPUT ;
    USE SIGNAL ;
    SHAPE ABUTMENT ;
    PORT
      LAYER M3 ;
      RECT 1.057 0.000 1.071 0.042 ;
    END
  END rw0_wd_in[132]
  PIN rw0_wd_in[133]
    DIRECTION INPUT ;
    USE SIGNAL ;
    SHAPE ABUTMENT ;
    PORT
      LAYER M3 ;
      RECT 1.281 0.000 1.295 0.042 ;
    END
  END rw0_wd_in[133]
  PIN rw0_wd_in[134]
    DIRECTION INPUT ;
    USE SIGNAL ;
    SHAPE ABUTMENT ;
    PORT
      LAYER M3 ;
      RECT 1.505 0.000 1.519 0.042 ;
    END
  END rw0_wd_in[134]
  PIN rw0_wd_in[135]
    DIRECTION INPUT ;
    USE SIGNAL ;
    SHAPE ABUTMENT ;
    PORT
      LAYER M3 ;
      RECT 1.729 0.000 1.743 0.042 ;
    END
  END rw0_wd_in[135]
  PIN rw0_wd_in[136]
    DIRECTION INPUT ;
    USE SIGNAL ;
    SHAPE ABUTMENT ;
    PORT
      LAYER M3 ;
      RECT 1.953 0.000 1.967 0.042 ;
    END
  END rw0_wd_in[136]
  PIN rw0_wd_in[137]
    DIRECTION INPUT ;
    USE SIGNAL ;
    SHAPE ABUTMENT ;
    PORT
      LAYER M3 ;
      RECT 2.177 0.000 2.191 0.042 ;
    END
  END rw0_wd_in[137]
  PIN rw0_wd_in[138]
    DIRECTION INPUT ;
    USE SIGNAL ;
    SHAPE ABUTMENT ;
    PORT
      LAYER M3 ;
      RECT 2.401 0.000 2.415 0.042 ;
    END
  END rw0_wd_in[138]
  PIN rw0_wd_in[139]
    DIRECTION INPUT ;
    USE SIGNAL ;
    SHAPE ABUTMENT ;
    PORT
      LAYER M3 ;
      RECT 2.625 0.000 2.639 0.042 ;
    END
  END rw0_wd_in[139]
  PIN rw0_wd_in[140]
    DIRECTION INPUT ;
    USE SIGNAL ;
    SHAPE ABUTMENT ;
    PORT
      LAYER M3 ;
      RECT 2.849 0.000 2.863 0.042 ;
    END
  END rw0_wd_in[140]
  PIN rw0_wd_in[141]
    DIRECTION INPUT ;
    USE SIGNAL ;
    SHAPE ABUTMENT ;
    PORT
      LAYER M3 ;
      RECT 3.073 0.000 3.087 0.042 ;
    END
  END rw0_wd_in[141]
  PIN rw0_wd_in[142]
    DIRECTION INPUT ;
    USE SIGNAL ;
    SHAPE ABUTMENT ;
    PORT
      LAYER M3 ;
      RECT 3.297 0.000 3.311 0.042 ;
    END
  END rw0_wd_in[142]
  PIN rw0_wd_in[143]
    DIRECTION INPUT ;
    USE SIGNAL ;
    SHAPE ABUTMENT ;
    PORT
      LAYER M3 ;
      RECT 3.521 0.000 3.535 0.042 ;
    END
  END rw0_wd_in[143]
  PIN rw0_wd_in[144]
    DIRECTION INPUT ;
    USE SIGNAL ;
    SHAPE ABUTMENT ;
    PORT
      LAYER M3 ;
      RECT 3.745 0.000 3.759 0.042 ;
    END
  END rw0_wd_in[144]
  PIN rw0_wd_in[145]
    DIRECTION INPUT ;
    USE SIGNAL ;
    SHAPE ABUTMENT ;
    PORT
      LAYER M3 ;
      RECT 3.969 0.000 3.983 0.042 ;
    END
  END rw0_wd_in[145]
  PIN rw0_wd_in[146]
    DIRECTION INPUT ;
    USE SIGNAL ;
    SHAPE ABUTMENT ;
    PORT
      LAYER M3 ;
      RECT 4.193 0.000 4.207 0.042 ;
    END
  END rw0_wd_in[146]
  PIN rw0_wd_in[147]
    DIRECTION INPUT ;
    USE SIGNAL ;
    SHAPE ABUTMENT ;
    PORT
      LAYER M3 ;
      RECT 4.417 0.000 4.431 0.042 ;
    END
  END rw0_wd_in[147]
  PIN rw0_wd_in[148]
    DIRECTION INPUT ;
    USE SIGNAL ;
    SHAPE ABUTMENT ;
    PORT
      LAYER M3 ;
      RECT 4.641 0.000 4.655 0.042 ;
    END
  END rw0_wd_in[148]
  PIN rw0_wd_in[149]
    DIRECTION INPUT ;
    USE SIGNAL ;
    SHAPE ABUTMENT ;
    PORT
      LAYER M3 ;
      RECT 4.865 0.000 4.879 0.042 ;
    END
  END rw0_wd_in[149]
  PIN rw0_wd_in[150]
    DIRECTION INPUT ;
    USE SIGNAL ;
    SHAPE ABUTMENT ;
    PORT
      LAYER M3 ;
      RECT 5.089 0.000 5.103 0.042 ;
    END
  END rw0_wd_in[150]
  PIN rw0_wd_in[151]
    DIRECTION INPUT ;
    USE SIGNAL ;
    SHAPE ABUTMENT ;
    PORT
      LAYER M3 ;
      RECT 5.313 0.000 5.327 0.042 ;
    END
  END rw0_wd_in[151]
  PIN rw0_wd_in[152]
    DIRECTION INPUT ;
    USE SIGNAL ;
    SHAPE ABUTMENT ;
    PORT
      LAYER M3 ;
      RECT 5.537 0.000 5.551 0.042 ;
    END
  END rw0_wd_in[152]
  PIN rw0_wd_in[153]
    DIRECTION INPUT ;
    USE SIGNAL ;
    SHAPE ABUTMENT ;
    PORT
      LAYER M3 ;
      RECT 5.761 0.000 5.775 0.042 ;
    END
  END rw0_wd_in[153]
  PIN rw0_wd_in[154]
    DIRECTION INPUT ;
    USE SIGNAL ;
    SHAPE ABUTMENT ;
    PORT
      LAYER M3 ;
      RECT 5.985 0.000 5.999 0.042 ;
    END
  END rw0_wd_in[154]
  PIN rw0_wd_in[155]
    DIRECTION INPUT ;
    USE SIGNAL ;
    SHAPE ABUTMENT ;
    PORT
      LAYER M3 ;
      RECT 6.209 0.000 6.223 0.042 ;
    END
  END rw0_wd_in[155]
  PIN rw0_wd_in[156]
    DIRECTION INPUT ;
    USE SIGNAL ;
    SHAPE ABUTMENT ;
    PORT
      LAYER M3 ;
      RECT 6.433 0.000 6.447 0.042 ;
    END
  END rw0_wd_in[156]
  PIN rw0_wd_in[157]
    DIRECTION INPUT ;
    USE SIGNAL ;
    SHAPE ABUTMENT ;
    PORT
      LAYER M3 ;
      RECT 6.657 0.000 6.671 0.042 ;
    END
  END rw0_wd_in[157]
  PIN rw0_wd_in[158]
    DIRECTION INPUT ;
    USE SIGNAL ;
    SHAPE ABUTMENT ;
    PORT
      LAYER M3 ;
      RECT 6.881 0.000 6.895 0.042 ;
    END
  END rw0_wd_in[158]
  PIN rw0_wd_in[159]
    DIRECTION INPUT ;
    USE SIGNAL ;
    SHAPE ABUTMENT ;
    PORT
      LAYER M3 ;
      RECT 7.105 0.000 7.119 0.042 ;
    END
  END rw0_wd_in[159]
  PIN rw0_wd_in[160]
    DIRECTION INPUT ;
    USE SIGNAL ;
    SHAPE ABUTMENT ;
    PORT
      LAYER M3 ;
      RECT 7.329 0.000 7.343 0.042 ;
    END
  END rw0_wd_in[160]
  PIN rw0_wd_in[161]
    DIRECTION INPUT ;
    USE SIGNAL ;
    SHAPE ABUTMENT ;
    PORT
      LAYER M3 ;
      RECT 7.553 0.000 7.567 0.042 ;
    END
  END rw0_wd_in[161]
  PIN rw0_wd_in[162]
    DIRECTION INPUT ;
    USE SIGNAL ;
    SHAPE ABUTMENT ;
    PORT
      LAYER M3 ;
      RECT 7.777 0.000 7.791 0.042 ;
    END
  END rw0_wd_in[162]
  PIN rw0_wd_in[163]
    DIRECTION INPUT ;
    USE SIGNAL ;
    SHAPE ABUTMENT ;
    PORT
      LAYER M3 ;
      RECT 8.001 0.000 8.015 0.042 ;
    END
  END rw0_wd_in[163]
  PIN rw0_wd_in[164]
    DIRECTION INPUT ;
    USE SIGNAL ;
    SHAPE ABUTMENT ;
    PORT
      LAYER M3 ;
      RECT 8.225 0.000 8.239 0.042 ;
    END
  END rw0_wd_in[164]
  PIN rw0_wd_in[165]
    DIRECTION INPUT ;
    USE SIGNAL ;
    SHAPE ABUTMENT ;
    PORT
      LAYER M3 ;
      RECT 8.449 0.000 8.463 0.042 ;
    END
  END rw0_wd_in[165]
  PIN rw0_wd_in[166]
    DIRECTION INPUT ;
    USE SIGNAL ;
    SHAPE ABUTMENT ;
    PORT
      LAYER M3 ;
      RECT 8.673 0.000 8.687 0.042 ;
    END
  END rw0_wd_in[166]
  PIN rw0_wd_in[167]
    DIRECTION INPUT ;
    USE SIGNAL ;
    SHAPE ABUTMENT ;
    PORT
      LAYER M3 ;
      RECT 8.897 0.000 8.911 0.042 ;
    END
  END rw0_wd_in[167]
  PIN rw0_wd_in[168]
    DIRECTION INPUT ;
    USE SIGNAL ;
    SHAPE ABUTMENT ;
    PORT
      LAYER M3 ;
      RECT 9.121 0.000 9.135 0.042 ;
    END
  END rw0_wd_in[168]
  PIN rw0_wd_in[169]
    DIRECTION INPUT ;
    USE SIGNAL ;
    SHAPE ABUTMENT ;
    PORT
      LAYER M3 ;
      RECT 9.345 0.000 9.359 0.042 ;
    END
  END rw0_wd_in[169]
  PIN rw0_wd_in[170]
    DIRECTION INPUT ;
    USE SIGNAL ;
    SHAPE ABUTMENT ;
    PORT
      LAYER M3 ;
      RECT 9.569 0.000 9.583 0.042 ;
    END
  END rw0_wd_in[170]
  PIN rw0_wd_in[171]
    DIRECTION INPUT ;
    USE SIGNAL ;
    SHAPE ABUTMENT ;
    PORT
      LAYER M3 ;
      RECT 9.793 0.000 9.807 0.042 ;
    END
  END rw0_wd_in[171]
  PIN rw0_wd_in[172]
    DIRECTION INPUT ;
    USE SIGNAL ;
    SHAPE ABUTMENT ;
    PORT
      LAYER M3 ;
      RECT 10.017 0.000 10.031 0.042 ;
    END
  END rw0_wd_in[172]
  PIN rw0_wd_in[173]
    DIRECTION INPUT ;
    USE SIGNAL ;
    SHAPE ABUTMENT ;
    PORT
      LAYER M3 ;
      RECT 10.241 0.000 10.255 0.042 ;
    END
  END rw0_wd_in[173]
  PIN rw0_wd_in[174]
    DIRECTION INPUT ;
    USE SIGNAL ;
    SHAPE ABUTMENT ;
    PORT
      LAYER M3 ;
      RECT 10.465 0.000 10.479 0.042 ;
    END
  END rw0_wd_in[174]
  PIN rw0_wd_in[175]
    DIRECTION INPUT ;
    USE SIGNAL ;
    SHAPE ABUTMENT ;
    PORT
      LAYER M3 ;
      RECT 10.689 0.000 10.703 0.042 ;
    END
  END rw0_wd_in[175]
  PIN rw0_wd_in[176]
    DIRECTION INPUT ;
    USE SIGNAL ;
    SHAPE ABUTMENT ;
    PORT
      LAYER M3 ;
      RECT 10.913 0.000 10.927 0.042 ;
    END
  END rw0_wd_in[176]
  PIN rw0_wd_in[177]
    DIRECTION INPUT ;
    USE SIGNAL ;
    SHAPE ABUTMENT ;
    PORT
      LAYER M3 ;
      RECT 11.137 0.000 11.151 0.042 ;
    END
  END rw0_wd_in[177]
  PIN rw0_wd_in[178]
    DIRECTION INPUT ;
    USE SIGNAL ;
    SHAPE ABUTMENT ;
    PORT
      LAYER M3 ;
      RECT 11.361 0.000 11.375 0.042 ;
    END
  END rw0_wd_in[178]
  PIN rw0_wd_in[179]
    DIRECTION INPUT ;
    USE SIGNAL ;
    SHAPE ABUTMENT ;
    PORT
      LAYER M3 ;
      RECT 11.585 0.000 11.599 0.042 ;
    END
  END rw0_wd_in[179]
  PIN rw0_wd_in[180]
    DIRECTION INPUT ;
    USE SIGNAL ;
    SHAPE ABUTMENT ;
    PORT
      LAYER M3 ;
      RECT 11.809 0.000 11.823 0.042 ;
    END
  END rw0_wd_in[180]
  PIN rw0_wd_in[181]
    DIRECTION INPUT ;
    USE SIGNAL ;
    SHAPE ABUTMENT ;
    PORT
      LAYER M3 ;
      RECT 12.033 0.000 12.047 0.042 ;
    END
  END rw0_wd_in[181]
  PIN rw0_wd_in[182]
    DIRECTION INPUT ;
    USE SIGNAL ;
    SHAPE ABUTMENT ;
    PORT
      LAYER M3 ;
      RECT 12.257 0.000 12.271 0.042 ;
    END
  END rw0_wd_in[182]
  PIN rw0_wd_in[183]
    DIRECTION INPUT ;
    USE SIGNAL ;
    SHAPE ABUTMENT ;
    PORT
      LAYER M3 ;
      RECT 12.481 0.000 12.495 0.042 ;
    END
  END rw0_wd_in[183]
  PIN rw0_wd_in[184]
    DIRECTION INPUT ;
    USE SIGNAL ;
    SHAPE ABUTMENT ;
    PORT
      LAYER M3 ;
      RECT 12.705 0.000 12.719 0.042 ;
    END
  END rw0_wd_in[184]
  PIN rw0_wd_in[185]
    DIRECTION INPUT ;
    USE SIGNAL ;
    SHAPE ABUTMENT ;
    PORT
      LAYER M3 ;
      RECT 12.929 0.000 12.943 0.042 ;
    END
  END rw0_wd_in[185]
  PIN rw0_wd_in[186]
    DIRECTION INPUT ;
    USE SIGNAL ;
    SHAPE ABUTMENT ;
    PORT
      LAYER M3 ;
      RECT 13.153 0.000 13.167 0.042 ;
    END
  END rw0_wd_in[186]
  PIN rw0_wd_in[187]
    DIRECTION INPUT ;
    USE SIGNAL ;
    SHAPE ABUTMENT ;
    PORT
      LAYER M3 ;
      RECT 13.377 0.000 13.391 0.042 ;
    END
  END rw0_wd_in[187]
  PIN rw0_wd_in[188]
    DIRECTION INPUT ;
    USE SIGNAL ;
    SHAPE ABUTMENT ;
    PORT
      LAYER M3 ;
      RECT 13.601 0.000 13.615 0.042 ;
    END
  END rw0_wd_in[188]
  PIN rw0_wd_in[189]
    DIRECTION INPUT ;
    USE SIGNAL ;
    SHAPE ABUTMENT ;
    PORT
      LAYER M3 ;
      RECT 13.825 0.000 13.839 0.042 ;
    END
  END rw0_wd_in[189]
  PIN rw0_wd_in[190]
    DIRECTION INPUT ;
    USE SIGNAL ;
    SHAPE ABUTMENT ;
    PORT
      LAYER M3 ;
      RECT 14.049 0.000 14.063 0.042 ;
    END
  END rw0_wd_in[190]
  PIN rw0_wd_in[191]
    DIRECTION INPUT ;
    USE SIGNAL ;
    SHAPE ABUTMENT ;
    PORT
      LAYER M3 ;
      RECT 14.273 0.000 14.287 0.042 ;
    END
  END rw0_wd_in[191]
  PIN rw0_wd_in[192]
    DIRECTION INPUT ;
    USE SIGNAL ;
    SHAPE ABUTMENT ;
    PORT
      LAYER M3 ;
      RECT 14.497 0.000 14.511 0.042 ;
    END
  END rw0_wd_in[192]
  PIN rw0_wd_in[193]
    DIRECTION INPUT ;
    USE SIGNAL ;
    SHAPE ABUTMENT ;
    PORT
      LAYER M3 ;
      RECT 14.721 0.000 14.735 0.042 ;
    END
  END rw0_wd_in[193]
  PIN rw0_wd_in[194]
    DIRECTION INPUT ;
    USE SIGNAL ;
    SHAPE ABUTMENT ;
    PORT
      LAYER M3 ;
      RECT 14.945 0.000 14.959 0.042 ;
    END
  END rw0_wd_in[194]
  PIN rw0_wd_in[195]
    DIRECTION INPUT ;
    USE SIGNAL ;
    SHAPE ABUTMENT ;
    PORT
      LAYER M3 ;
      RECT 15.169 0.000 15.183 0.042 ;
    END
  END rw0_wd_in[195]
  PIN rw0_wd_in[196]
    DIRECTION INPUT ;
    USE SIGNAL ;
    SHAPE ABUTMENT ;
    PORT
      LAYER M3 ;
      RECT 15.393 0.000 15.407 0.042 ;
    END
  END rw0_wd_in[196]
  PIN rw0_wd_in[197]
    DIRECTION INPUT ;
    USE SIGNAL ;
    SHAPE ABUTMENT ;
    PORT
      LAYER M3 ;
      RECT 15.617 0.000 15.631 0.042 ;
    END
  END rw0_wd_in[197]
  PIN rw0_wd_in[198]
    DIRECTION INPUT ;
    USE SIGNAL ;
    SHAPE ABUTMENT ;
    PORT
      LAYER M3 ;
      RECT 15.841 0.000 15.855 0.042 ;
    END
  END rw0_wd_in[198]
  PIN rw0_wd_in[199]
    DIRECTION INPUT ;
    USE SIGNAL ;
    SHAPE ABUTMENT ;
    PORT
      LAYER M3 ;
      RECT 16.065 0.000 16.079 0.042 ;
    END
  END rw0_wd_in[199]
  PIN rw0_wd_in[200]
    DIRECTION INPUT ;
    USE SIGNAL ;
    SHAPE ABUTMENT ;
    PORT
      LAYER M3 ;
      RECT 16.289 0.000 16.303 0.042 ;
    END
  END rw0_wd_in[200]
  PIN rw0_wd_in[201]
    DIRECTION INPUT ;
    USE SIGNAL ;
    SHAPE ABUTMENT ;
    PORT
      LAYER M3 ;
      RECT 16.513 0.000 16.527 0.042 ;
    END
  END rw0_wd_in[201]
  PIN rw0_wd_in[202]
    DIRECTION INPUT ;
    USE SIGNAL ;
    SHAPE ABUTMENT ;
    PORT
      LAYER M3 ;
      RECT 16.737 0.000 16.751 0.042 ;
    END
  END rw0_wd_in[202]
  PIN rw0_wd_in[203]
    DIRECTION INPUT ;
    USE SIGNAL ;
    SHAPE ABUTMENT ;
    PORT
      LAYER M3 ;
      RECT 16.961 0.000 16.975 0.042 ;
    END
  END rw0_wd_in[203]
  PIN rw0_wd_in[204]
    DIRECTION INPUT ;
    USE SIGNAL ;
    SHAPE ABUTMENT ;
    PORT
      LAYER M3 ;
      RECT 17.185 0.000 17.199 0.042 ;
    END
  END rw0_wd_in[204]
  PIN rw0_wd_in[205]
    DIRECTION INPUT ;
    USE SIGNAL ;
    SHAPE ABUTMENT ;
    PORT
      LAYER M3 ;
      RECT 17.409 0.000 17.423 0.042 ;
    END
  END rw0_wd_in[205]
  PIN rw0_wd_in[206]
    DIRECTION INPUT ;
    USE SIGNAL ;
    SHAPE ABUTMENT ;
    PORT
      LAYER M3 ;
      RECT 17.633 0.000 17.647 0.042 ;
    END
  END rw0_wd_in[206]
  PIN rw0_wd_in[207]
    DIRECTION INPUT ;
    USE SIGNAL ;
    SHAPE ABUTMENT ;
    PORT
      LAYER M3 ;
      RECT 17.857 0.000 17.871 0.042 ;
    END
  END rw0_wd_in[207]
  PIN rw0_wd_in[208]
    DIRECTION INPUT ;
    USE SIGNAL ;
    SHAPE ABUTMENT ;
    PORT
      LAYER M3 ;
      RECT 18.081 0.000 18.095 0.042 ;
    END
  END rw0_wd_in[208]
  PIN rw0_wd_in[209]
    DIRECTION INPUT ;
    USE SIGNAL ;
    SHAPE ABUTMENT ;
    PORT
      LAYER M3 ;
      RECT 18.305 0.000 18.319 0.042 ;
    END
  END rw0_wd_in[209]
  PIN rw0_wd_in[210]
    DIRECTION INPUT ;
    USE SIGNAL ;
    SHAPE ABUTMENT ;
    PORT
      LAYER M3 ;
      RECT 18.529 0.000 18.543 0.042 ;
    END
  END rw0_wd_in[210]
  PIN rw0_wd_in[211]
    DIRECTION INPUT ;
    USE SIGNAL ;
    SHAPE ABUTMENT ;
    PORT
      LAYER M3 ;
      RECT 18.753 0.000 18.767 0.042 ;
    END
  END rw0_wd_in[211]
  PIN rw0_wd_in[212]
    DIRECTION INPUT ;
    USE SIGNAL ;
    SHAPE ABUTMENT ;
    PORT
      LAYER M3 ;
      RECT 18.977 0.000 18.991 0.042 ;
    END
  END rw0_wd_in[212]
  PIN rw0_wd_in[213]
    DIRECTION INPUT ;
    USE SIGNAL ;
    SHAPE ABUTMENT ;
    PORT
      LAYER M3 ;
      RECT 19.201 0.000 19.215 0.042 ;
    END
  END rw0_wd_in[213]
  PIN rw0_wd_in[214]
    DIRECTION INPUT ;
    USE SIGNAL ;
    SHAPE ABUTMENT ;
    PORT
      LAYER M3 ;
      RECT 19.425 0.000 19.439 0.042 ;
    END
  END rw0_wd_in[214]
  PIN rw0_wd_in[215]
    DIRECTION INPUT ;
    USE SIGNAL ;
    SHAPE ABUTMENT ;
    PORT
      LAYER M3 ;
      RECT 19.649 0.000 19.663 0.042 ;
    END
  END rw0_wd_in[215]
  PIN rw0_wd_in[216]
    DIRECTION INPUT ;
    USE SIGNAL ;
    SHAPE ABUTMENT ;
    PORT
      LAYER M3 ;
      RECT 19.873 0.000 19.887 0.042 ;
    END
  END rw0_wd_in[216]
  PIN rw0_wd_in[217]
    DIRECTION INPUT ;
    USE SIGNAL ;
    SHAPE ABUTMENT ;
    PORT
      LAYER M3 ;
      RECT 20.097 0.000 20.111 0.042 ;
    END
  END rw0_wd_in[217]
  PIN rw0_wd_in[218]
    DIRECTION INPUT ;
    USE SIGNAL ;
    SHAPE ABUTMENT ;
    PORT
      LAYER M3 ;
      RECT 20.321 0.000 20.335 0.042 ;
    END
  END rw0_wd_in[218]
  PIN rw0_wd_in[219]
    DIRECTION INPUT ;
    USE SIGNAL ;
    SHAPE ABUTMENT ;
    PORT
      LAYER M3 ;
      RECT 20.545 0.000 20.559 0.042 ;
    END
  END rw0_wd_in[219]
  PIN rw0_wd_in[220]
    DIRECTION INPUT ;
    USE SIGNAL ;
    SHAPE ABUTMENT ;
    PORT
      LAYER M3 ;
      RECT 20.769 0.000 20.783 0.042 ;
    END
  END rw0_wd_in[220]
  PIN rw0_wd_in[221]
    DIRECTION INPUT ;
    USE SIGNAL ;
    SHAPE ABUTMENT ;
    PORT
      LAYER M3 ;
      RECT 20.993 0.000 21.007 0.042 ;
    END
  END rw0_wd_in[221]
  PIN rw0_wd_in[222]
    DIRECTION INPUT ;
    USE SIGNAL ;
    SHAPE ABUTMENT ;
    PORT
      LAYER M3 ;
      RECT 21.217 0.000 21.231 0.042 ;
    END
  END rw0_wd_in[222]
  PIN rw0_wd_in[223]
    DIRECTION INPUT ;
    USE SIGNAL ;
    SHAPE ABUTMENT ;
    PORT
      LAYER M3 ;
      RECT 21.441 0.000 21.455 0.042 ;
    END
  END rw0_wd_in[223]
  PIN rw0_wd_in[224]
    DIRECTION INPUT ;
    USE SIGNAL ;
    SHAPE ABUTMENT ;
    PORT
      LAYER M3 ;
      RECT 21.665 0.000 21.679 0.042 ;
    END
  END rw0_wd_in[224]
  PIN rw0_wd_in[225]
    DIRECTION INPUT ;
    USE SIGNAL ;
    SHAPE ABUTMENT ;
    PORT
      LAYER M3 ;
      RECT 21.889 0.000 21.903 0.042 ;
    END
  END rw0_wd_in[225]
  PIN rw0_wd_in[226]
    DIRECTION INPUT ;
    USE SIGNAL ;
    SHAPE ABUTMENT ;
    PORT
      LAYER M3 ;
      RECT 22.113 0.000 22.127 0.042 ;
    END
  END rw0_wd_in[226]
  PIN rw0_wd_in[227]
    DIRECTION INPUT ;
    USE SIGNAL ;
    SHAPE ABUTMENT ;
    PORT
      LAYER M3 ;
      RECT 22.337 0.000 22.351 0.042 ;
    END
  END rw0_wd_in[227]
  PIN rw0_wd_in[228]
    DIRECTION INPUT ;
    USE SIGNAL ;
    SHAPE ABUTMENT ;
    PORT
      LAYER M3 ;
      RECT 22.561 0.000 22.575 0.042 ;
    END
  END rw0_wd_in[228]
  PIN rw0_wd_in[229]
    DIRECTION INPUT ;
    USE SIGNAL ;
    SHAPE ABUTMENT ;
    PORT
      LAYER M3 ;
      RECT 22.785 0.000 22.799 0.042 ;
    END
  END rw0_wd_in[229]
  PIN rw0_wd_in[230]
    DIRECTION INPUT ;
    USE SIGNAL ;
    SHAPE ABUTMENT ;
    PORT
      LAYER M3 ;
      RECT 23.009 0.000 23.023 0.042 ;
    END
  END rw0_wd_in[230]
  PIN rw0_wd_in[231]
    DIRECTION INPUT ;
    USE SIGNAL ;
    SHAPE ABUTMENT ;
    PORT
      LAYER M3 ;
      RECT 23.233 0.000 23.247 0.042 ;
    END
  END rw0_wd_in[231]
  PIN rw0_wd_in[232]
    DIRECTION INPUT ;
    USE SIGNAL ;
    SHAPE ABUTMENT ;
    PORT
      LAYER M3 ;
      RECT 23.457 0.000 23.471 0.042 ;
    END
  END rw0_wd_in[232]
  PIN rw0_wd_in[233]
    DIRECTION INPUT ;
    USE SIGNAL ;
    SHAPE ABUTMENT ;
    PORT
      LAYER M3 ;
      RECT 23.681 0.000 23.695 0.042 ;
    END
  END rw0_wd_in[233]
  PIN rw0_wd_in[234]
    DIRECTION INPUT ;
    USE SIGNAL ;
    SHAPE ABUTMENT ;
    PORT
      LAYER M3 ;
      RECT 23.905 0.000 23.919 0.042 ;
    END
  END rw0_wd_in[234]
  PIN rw0_wd_in[235]
    DIRECTION INPUT ;
    USE SIGNAL ;
    SHAPE ABUTMENT ;
    PORT
      LAYER M3 ;
      RECT 24.129 0.000 24.143 0.042 ;
    END
  END rw0_wd_in[235]
  PIN rw0_wd_in[236]
    DIRECTION INPUT ;
    USE SIGNAL ;
    SHAPE ABUTMENT ;
    PORT
      LAYER M3 ;
      RECT 24.353 0.000 24.367 0.042 ;
    END
  END rw0_wd_in[236]
  PIN rw0_wd_in[237]
    DIRECTION INPUT ;
    USE SIGNAL ;
    SHAPE ABUTMENT ;
    PORT
      LAYER M3 ;
      RECT 24.577 0.000 24.591 0.042 ;
    END
  END rw0_wd_in[237]
  PIN rw0_wd_in[238]
    DIRECTION INPUT ;
    USE SIGNAL ;
    SHAPE ABUTMENT ;
    PORT
      LAYER M3 ;
      RECT 24.801 0.000 24.815 0.042 ;
    END
  END rw0_wd_in[238]
  PIN rw0_wd_in[239]
    DIRECTION INPUT ;
    USE SIGNAL ;
    SHAPE ABUTMENT ;
    PORT
      LAYER M3 ;
      RECT 25.025 0.000 25.039 0.042 ;
    END
  END rw0_wd_in[239]
  PIN rw0_wd_in[240]
    DIRECTION INPUT ;
    USE SIGNAL ;
    SHAPE ABUTMENT ;
    PORT
      LAYER M3 ;
      RECT 25.249 0.000 25.263 0.042 ;
    END
  END rw0_wd_in[240]
  PIN rw0_wd_in[241]
    DIRECTION INPUT ;
    USE SIGNAL ;
    SHAPE ABUTMENT ;
    PORT
      LAYER M3 ;
      RECT 25.473 0.000 25.487 0.042 ;
    END
  END rw0_wd_in[241]
  PIN rw0_wd_in[242]
    DIRECTION INPUT ;
    USE SIGNAL ;
    SHAPE ABUTMENT ;
    PORT
      LAYER M3 ;
      RECT 25.697 0.000 25.711 0.042 ;
    END
  END rw0_wd_in[242]
  PIN rw0_wd_in[243]
    DIRECTION INPUT ;
    USE SIGNAL ;
    SHAPE ABUTMENT ;
    PORT
      LAYER M3 ;
      RECT 25.921 0.000 25.935 0.042 ;
    END
  END rw0_wd_in[243]
  PIN rw0_wd_in[244]
    DIRECTION INPUT ;
    USE SIGNAL ;
    SHAPE ABUTMENT ;
    PORT
      LAYER M3 ;
      RECT 26.145 0.000 26.159 0.042 ;
    END
  END rw0_wd_in[244]
  PIN rw0_wd_in[245]
    DIRECTION INPUT ;
    USE SIGNAL ;
    SHAPE ABUTMENT ;
    PORT
      LAYER M3 ;
      RECT 26.369 0.000 26.383 0.042 ;
    END
  END rw0_wd_in[245]
  PIN rw0_wd_in[246]
    DIRECTION INPUT ;
    USE SIGNAL ;
    SHAPE ABUTMENT ;
    PORT
      LAYER M3 ;
      RECT 26.593 0.000 26.607 0.042 ;
    END
  END rw0_wd_in[246]
  PIN rw0_wd_in[247]
    DIRECTION INPUT ;
    USE SIGNAL ;
    SHAPE ABUTMENT ;
    PORT
      LAYER M3 ;
      RECT 26.817 0.000 26.831 0.042 ;
    END
  END rw0_wd_in[247]
  PIN rw0_wd_in[248]
    DIRECTION INPUT ;
    USE SIGNAL ;
    SHAPE ABUTMENT ;
    PORT
      LAYER M3 ;
      RECT 27.041 0.000 27.055 0.042 ;
    END
  END rw0_wd_in[248]
  PIN rw0_wd_in[249]
    DIRECTION INPUT ;
    USE SIGNAL ;
    SHAPE ABUTMENT ;
    PORT
      LAYER M3 ;
      RECT 27.265 0.000 27.279 0.042 ;
    END
  END rw0_wd_in[249]
  PIN rw0_wd_in[250]
    DIRECTION INPUT ;
    USE SIGNAL ;
    SHAPE ABUTMENT ;
    PORT
      LAYER M3 ;
      RECT 27.489 0.000 27.503 0.042 ;
    END
  END rw0_wd_in[250]
  PIN rw0_wd_in[251]
    DIRECTION INPUT ;
    USE SIGNAL ;
    SHAPE ABUTMENT ;
    PORT
      LAYER M3 ;
      RECT 27.713 0.000 27.727 0.042 ;
    END
  END rw0_wd_in[251]
  PIN rw0_wd_in[252]
    DIRECTION INPUT ;
    USE SIGNAL ;
    SHAPE ABUTMENT ;
    PORT
      LAYER M3 ;
      RECT 27.937 0.000 27.951 0.042 ;
    END
  END rw0_wd_in[252]
  PIN rw0_wd_in[253]
    DIRECTION INPUT ;
    USE SIGNAL ;
    SHAPE ABUTMENT ;
    PORT
      LAYER M3 ;
      RECT 28.161 0.000 28.175 0.042 ;
    END
  END rw0_wd_in[253]
  PIN rw0_wd_in[254]
    DIRECTION INPUT ;
    USE SIGNAL ;
    SHAPE ABUTMENT ;
    PORT
      LAYER M3 ;
      RECT 28.385 0.000 28.399 0.042 ;
    END
  END rw0_wd_in[254]
  PIN rw0_wd_in[255]
    DIRECTION INPUT ;
    USE SIGNAL ;
    SHAPE ABUTMENT ;
    PORT
      LAYER M3 ;
      RECT 28.609 0.000 28.623 0.042 ;
    END
  END rw0_wd_in[255]
  PIN rw0_rd_out[0]
    DIRECTION OUTPUT ;
    USE SIGNAL ;
    SHAPE ABUTMENT ;
    PORT
      LAYER M3 ;
      RECT 28.833 0.000 28.847 0.042 ;
    END
  END rw0_rd_out[0]
  PIN rw0_rd_out[1]
    DIRECTION OUTPUT ;
    USE SIGNAL ;
    SHAPE ABUTMENT ;
    PORT
      LAYER M3 ;
      RECT 29.057 0.000 29.071 0.042 ;
    END
  END rw0_rd_out[1]
  PIN rw0_rd_out[2]
    DIRECTION OUTPUT ;
    USE SIGNAL ;
    SHAPE ABUTMENT ;
    PORT
      LAYER M3 ;
      RECT 29.281 0.000 29.295 0.042 ;
    END
  END rw0_rd_out[2]
  PIN rw0_rd_out[3]
    DIRECTION OUTPUT ;
    USE SIGNAL ;
    SHAPE ABUTMENT ;
    PORT
      LAYER M3 ;
      RECT 29.505 0.000 29.519 0.042 ;
    END
  END rw0_rd_out[3]
  PIN rw0_rd_out[4]
    DIRECTION OUTPUT ;
    USE SIGNAL ;
    SHAPE ABUTMENT ;
    PORT
      LAYER M3 ;
      RECT 29.729 0.000 29.743 0.042 ;
    END
  END rw0_rd_out[4]
  PIN rw0_rd_out[5]
    DIRECTION OUTPUT ;
    USE SIGNAL ;
    SHAPE ABUTMENT ;
    PORT
      LAYER M3 ;
      RECT 29.953 0.000 29.967 0.042 ;
    END
  END rw0_rd_out[5]
  PIN rw0_rd_out[6]
    DIRECTION OUTPUT ;
    USE SIGNAL ;
    SHAPE ABUTMENT ;
    PORT
      LAYER M3 ;
      RECT 30.177 0.000 30.191 0.042 ;
    END
  END rw0_rd_out[6]
  PIN rw0_rd_out[7]
    DIRECTION OUTPUT ;
    USE SIGNAL ;
    SHAPE ABUTMENT ;
    PORT
      LAYER M3 ;
      RECT 30.401 0.000 30.415 0.042 ;
    END
  END rw0_rd_out[7]
  PIN rw0_rd_out[8]
    DIRECTION OUTPUT ;
    USE SIGNAL ;
    SHAPE ABUTMENT ;
    PORT
      LAYER M3 ;
      RECT 30.625 0.000 30.639 0.042 ;
    END
  END rw0_rd_out[8]
  PIN rw0_rd_out[9]
    DIRECTION OUTPUT ;
    USE SIGNAL ;
    SHAPE ABUTMENT ;
    PORT
      LAYER M3 ;
      RECT 30.849 0.000 30.863 0.042 ;
    END
  END rw0_rd_out[9]
  PIN rw0_rd_out[10]
    DIRECTION OUTPUT ;
    USE SIGNAL ;
    SHAPE ABUTMENT ;
    PORT
      LAYER M3 ;
      RECT 31.073 0.000 31.087 0.042 ;
    END
  END rw0_rd_out[10]
  PIN rw0_rd_out[11]
    DIRECTION OUTPUT ;
    USE SIGNAL ;
    SHAPE ABUTMENT ;
    PORT
      LAYER M3 ;
      RECT 31.297 0.000 31.311 0.042 ;
    END
  END rw0_rd_out[11]
  PIN rw0_rd_out[12]
    DIRECTION OUTPUT ;
    USE SIGNAL ;
    SHAPE ABUTMENT ;
    PORT
      LAYER M3 ;
      RECT 31.521 0.000 31.535 0.042 ;
    END
  END rw0_rd_out[12]
  PIN rw0_rd_out[13]
    DIRECTION OUTPUT ;
    USE SIGNAL ;
    SHAPE ABUTMENT ;
    PORT
      LAYER M3 ;
      RECT 31.745 0.000 31.759 0.042 ;
    END
  END rw0_rd_out[13]
  PIN rw0_rd_out[14]
    DIRECTION OUTPUT ;
    USE SIGNAL ;
    SHAPE ABUTMENT ;
    PORT
      LAYER M3 ;
      RECT 31.969 0.000 31.983 0.042 ;
    END
  END rw0_rd_out[14]
  PIN rw0_rd_out[15]
    DIRECTION OUTPUT ;
    USE SIGNAL ;
    SHAPE ABUTMENT ;
    PORT
      LAYER M3 ;
      RECT 32.193 0.000 32.207 0.042 ;
    END
  END rw0_rd_out[15]
  PIN rw0_rd_out[16]
    DIRECTION OUTPUT ;
    USE SIGNAL ;
    SHAPE ABUTMENT ;
    PORT
      LAYER M3 ;
      RECT 32.417 0.000 32.431 0.042 ;
    END
  END rw0_rd_out[16]
  PIN rw0_rd_out[17]
    DIRECTION OUTPUT ;
    USE SIGNAL ;
    SHAPE ABUTMENT ;
    PORT
      LAYER M3 ;
      RECT 32.641 0.000 32.655 0.042 ;
    END
  END rw0_rd_out[17]
  PIN rw0_rd_out[18]
    DIRECTION OUTPUT ;
    USE SIGNAL ;
    SHAPE ABUTMENT ;
    PORT
      LAYER M3 ;
      RECT 32.865 0.000 32.879 0.042 ;
    END
  END rw0_rd_out[18]
  PIN rw0_rd_out[19]
    DIRECTION OUTPUT ;
    USE SIGNAL ;
    SHAPE ABUTMENT ;
    PORT
      LAYER M3 ;
      RECT 33.089 0.000 33.103 0.042 ;
    END
  END rw0_rd_out[19]
  PIN rw0_rd_out[20]
    DIRECTION OUTPUT ;
    USE SIGNAL ;
    SHAPE ABUTMENT ;
    PORT
      LAYER M3 ;
      RECT 33.313 0.000 33.327 0.042 ;
    END
  END rw0_rd_out[20]
  PIN rw0_rd_out[21]
    DIRECTION OUTPUT ;
    USE SIGNAL ;
    SHAPE ABUTMENT ;
    PORT
      LAYER M3 ;
      RECT 33.537 0.000 33.551 0.042 ;
    END
  END rw0_rd_out[21]
  PIN rw0_rd_out[22]
    DIRECTION OUTPUT ;
    USE SIGNAL ;
    SHAPE ABUTMENT ;
    PORT
      LAYER M3 ;
      RECT 33.761 0.000 33.775 0.042 ;
    END
  END rw0_rd_out[22]
  PIN rw0_rd_out[23]
    DIRECTION OUTPUT ;
    USE SIGNAL ;
    SHAPE ABUTMENT ;
    PORT
      LAYER M3 ;
      RECT 33.985 0.000 33.999 0.042 ;
    END
  END rw0_rd_out[23]
  PIN rw0_rd_out[24]
    DIRECTION OUTPUT ;
    USE SIGNAL ;
    SHAPE ABUTMENT ;
    PORT
      LAYER M3 ;
      RECT 34.209 0.000 34.223 0.042 ;
    END
  END rw0_rd_out[24]
  PIN rw0_rd_out[25]
    DIRECTION OUTPUT ;
    USE SIGNAL ;
    SHAPE ABUTMENT ;
    PORT
      LAYER M3 ;
      RECT 34.433 0.000 34.447 0.042 ;
    END
  END rw0_rd_out[25]
  PIN rw0_rd_out[26]
    DIRECTION OUTPUT ;
    USE SIGNAL ;
    SHAPE ABUTMENT ;
    PORT
      LAYER M3 ;
      RECT 34.657 0.000 34.671 0.042 ;
    END
  END rw0_rd_out[26]
  PIN rw0_rd_out[27]
    DIRECTION OUTPUT ;
    USE SIGNAL ;
    SHAPE ABUTMENT ;
    PORT
      LAYER M3 ;
      RECT 34.881 0.000 34.895 0.042 ;
    END
  END rw0_rd_out[27]
  PIN rw0_rd_out[28]
    DIRECTION OUTPUT ;
    USE SIGNAL ;
    SHAPE ABUTMENT ;
    PORT
      LAYER M3 ;
      RECT 35.105 0.000 35.119 0.042 ;
    END
  END rw0_rd_out[28]
  PIN rw0_rd_out[29]
    DIRECTION OUTPUT ;
    USE SIGNAL ;
    SHAPE ABUTMENT ;
    PORT
      LAYER M3 ;
      RECT 35.329 0.000 35.343 0.042 ;
    END
  END rw0_rd_out[29]
  PIN rw0_rd_out[30]
    DIRECTION OUTPUT ;
    USE SIGNAL ;
    SHAPE ABUTMENT ;
    PORT
      LAYER M3 ;
      RECT 35.553 0.000 35.567 0.042 ;
    END
  END rw0_rd_out[30]
  PIN rw0_rd_out[31]
    DIRECTION OUTPUT ;
    USE SIGNAL ;
    SHAPE ABUTMENT ;
    PORT
      LAYER M3 ;
      RECT 35.777 0.000 35.791 0.042 ;
    END
  END rw0_rd_out[31]
  PIN rw0_rd_out[32]
    DIRECTION OUTPUT ;
    USE SIGNAL ;
    SHAPE ABUTMENT ;
    PORT
      LAYER M3 ;
      RECT 36.001 0.000 36.015 0.042 ;
    END
  END rw0_rd_out[32]
  PIN rw0_rd_out[33]
    DIRECTION OUTPUT ;
    USE SIGNAL ;
    SHAPE ABUTMENT ;
    PORT
      LAYER M3 ;
      RECT 36.225 0.000 36.239 0.042 ;
    END
  END rw0_rd_out[33]
  PIN rw0_rd_out[34]
    DIRECTION OUTPUT ;
    USE SIGNAL ;
    SHAPE ABUTMENT ;
    PORT
      LAYER M3 ;
      RECT 36.449 0.000 36.463 0.042 ;
    END
  END rw0_rd_out[34]
  PIN rw0_rd_out[35]
    DIRECTION OUTPUT ;
    USE SIGNAL ;
    SHAPE ABUTMENT ;
    PORT
      LAYER M3 ;
      RECT 36.673 0.000 36.687 0.042 ;
    END
  END rw0_rd_out[35]
  PIN rw0_rd_out[36]
    DIRECTION OUTPUT ;
    USE SIGNAL ;
    SHAPE ABUTMENT ;
    PORT
      LAYER M3 ;
      RECT 36.897 0.000 36.911 0.042 ;
    END
  END rw0_rd_out[36]
  PIN rw0_rd_out[37]
    DIRECTION OUTPUT ;
    USE SIGNAL ;
    SHAPE ABUTMENT ;
    PORT
      LAYER M3 ;
      RECT 37.121 0.000 37.135 0.042 ;
    END
  END rw0_rd_out[37]
  PIN rw0_rd_out[38]
    DIRECTION OUTPUT ;
    USE SIGNAL ;
    SHAPE ABUTMENT ;
    PORT
      LAYER M3 ;
      RECT 37.345 0.000 37.359 0.042 ;
    END
  END rw0_rd_out[38]
  PIN rw0_rd_out[39]
    DIRECTION OUTPUT ;
    USE SIGNAL ;
    SHAPE ABUTMENT ;
    PORT
      LAYER M3 ;
      RECT 37.569 0.000 37.583 0.042 ;
    END
  END rw0_rd_out[39]
  PIN rw0_rd_out[40]
    DIRECTION OUTPUT ;
    USE SIGNAL ;
    SHAPE ABUTMENT ;
    PORT
      LAYER M3 ;
      RECT 37.793 0.000 37.807 0.042 ;
    END
  END rw0_rd_out[40]
  PIN rw0_rd_out[41]
    DIRECTION OUTPUT ;
    USE SIGNAL ;
    SHAPE ABUTMENT ;
    PORT
      LAYER M3 ;
      RECT 38.017 0.000 38.031 0.042 ;
    END
  END rw0_rd_out[41]
  PIN rw0_rd_out[42]
    DIRECTION OUTPUT ;
    USE SIGNAL ;
    SHAPE ABUTMENT ;
    PORT
      LAYER M3 ;
      RECT 38.241 0.000 38.255 0.042 ;
    END
  END rw0_rd_out[42]
  PIN rw0_rd_out[43]
    DIRECTION OUTPUT ;
    USE SIGNAL ;
    SHAPE ABUTMENT ;
    PORT
      LAYER M3 ;
      RECT 38.465 0.000 38.479 0.042 ;
    END
  END rw0_rd_out[43]
  PIN rw0_rd_out[44]
    DIRECTION OUTPUT ;
    USE SIGNAL ;
    SHAPE ABUTMENT ;
    PORT
      LAYER M3 ;
      RECT 38.689 0.000 38.703 0.042 ;
    END
  END rw0_rd_out[44]
  PIN rw0_rd_out[45]
    DIRECTION OUTPUT ;
    USE SIGNAL ;
    SHAPE ABUTMENT ;
    PORT
      LAYER M3 ;
      RECT 38.913 0.000 38.927 0.042 ;
    END
  END rw0_rd_out[45]
  PIN rw0_rd_out[46]
    DIRECTION OUTPUT ;
    USE SIGNAL ;
    SHAPE ABUTMENT ;
    PORT
      LAYER M3 ;
      RECT 39.137 0.000 39.151 0.042 ;
    END
  END rw0_rd_out[46]
  PIN rw0_rd_out[47]
    DIRECTION OUTPUT ;
    USE SIGNAL ;
    SHAPE ABUTMENT ;
    PORT
      LAYER M3 ;
      RECT 39.361 0.000 39.375 0.042 ;
    END
  END rw0_rd_out[47]
  PIN rw0_rd_out[48]
    DIRECTION OUTPUT ;
    USE SIGNAL ;
    SHAPE ABUTMENT ;
    PORT
      LAYER M3 ;
      RECT 39.585 0.000 39.599 0.042 ;
    END
  END rw0_rd_out[48]
  PIN rw0_rd_out[49]
    DIRECTION OUTPUT ;
    USE SIGNAL ;
    SHAPE ABUTMENT ;
    PORT
      LAYER M3 ;
      RECT 39.809 0.000 39.823 0.042 ;
    END
  END rw0_rd_out[49]
  PIN rw0_rd_out[50]
    DIRECTION OUTPUT ;
    USE SIGNAL ;
    SHAPE ABUTMENT ;
    PORT
      LAYER M3 ;
      RECT 40.033 0.000 40.047 0.042 ;
    END
  END rw0_rd_out[50]
  PIN rw0_rd_out[51]
    DIRECTION OUTPUT ;
    USE SIGNAL ;
    SHAPE ABUTMENT ;
    PORT
      LAYER M3 ;
      RECT 40.257 0.000 40.271 0.042 ;
    END
  END rw0_rd_out[51]
  PIN rw0_rd_out[52]
    DIRECTION OUTPUT ;
    USE SIGNAL ;
    SHAPE ABUTMENT ;
    PORT
      LAYER M3 ;
      RECT 40.481 0.000 40.495 0.042 ;
    END
  END rw0_rd_out[52]
  PIN rw0_rd_out[53]
    DIRECTION OUTPUT ;
    USE SIGNAL ;
    SHAPE ABUTMENT ;
    PORT
      LAYER M3 ;
      RECT 40.705 0.000 40.719 0.042 ;
    END
  END rw0_rd_out[53]
  PIN rw0_rd_out[54]
    DIRECTION OUTPUT ;
    USE SIGNAL ;
    SHAPE ABUTMENT ;
    PORT
      LAYER M3 ;
      RECT 40.929 0.000 40.943 0.042 ;
    END
  END rw0_rd_out[54]
  PIN rw0_rd_out[55]
    DIRECTION OUTPUT ;
    USE SIGNAL ;
    SHAPE ABUTMENT ;
    PORT
      LAYER M3 ;
      RECT 41.153 0.000 41.167 0.042 ;
    END
  END rw0_rd_out[55]
  PIN rw0_rd_out[56]
    DIRECTION OUTPUT ;
    USE SIGNAL ;
    SHAPE ABUTMENT ;
    PORT
      LAYER M3 ;
      RECT 41.377 0.000 41.391 0.042 ;
    END
  END rw0_rd_out[56]
  PIN rw0_rd_out[57]
    DIRECTION OUTPUT ;
    USE SIGNAL ;
    SHAPE ABUTMENT ;
    PORT
      LAYER M3 ;
      RECT 41.601 0.000 41.615 0.042 ;
    END
  END rw0_rd_out[57]
  PIN rw0_rd_out[58]
    DIRECTION OUTPUT ;
    USE SIGNAL ;
    SHAPE ABUTMENT ;
    PORT
      LAYER M3 ;
      RECT 41.825 0.000 41.839 0.042 ;
    END
  END rw0_rd_out[58]
  PIN rw0_rd_out[59]
    DIRECTION OUTPUT ;
    USE SIGNAL ;
    SHAPE ABUTMENT ;
    PORT
      LAYER M3 ;
      RECT 42.049 0.000 42.063 0.042 ;
    END
  END rw0_rd_out[59]
  PIN rw0_rd_out[60]
    DIRECTION OUTPUT ;
    USE SIGNAL ;
    SHAPE ABUTMENT ;
    PORT
      LAYER M3 ;
      RECT 42.273 0.000 42.287 0.042 ;
    END
  END rw0_rd_out[60]
  PIN rw0_rd_out[61]
    DIRECTION OUTPUT ;
    USE SIGNAL ;
    SHAPE ABUTMENT ;
    PORT
      LAYER M3 ;
      RECT 42.497 0.000 42.511 0.042 ;
    END
  END rw0_rd_out[61]
  PIN rw0_rd_out[62]
    DIRECTION OUTPUT ;
    USE SIGNAL ;
    SHAPE ABUTMENT ;
    PORT
      LAYER M3 ;
      RECT 42.721 0.000 42.735 0.042 ;
    END
  END rw0_rd_out[62]
  PIN rw0_rd_out[63]
    DIRECTION OUTPUT ;
    USE SIGNAL ;
    SHAPE ABUTMENT ;
    PORT
      LAYER M3 ;
      RECT 42.945 0.000 42.959 0.042 ;
    END
  END rw0_rd_out[63]
  PIN rw0_rd_out[64]
    DIRECTION OUTPUT ;
    USE SIGNAL ;
    SHAPE ABUTMENT ;
    PORT
      LAYER M3 ;
      RECT 43.169 0.000 43.183 0.042 ;
    END
  END rw0_rd_out[64]
  PIN rw0_rd_out[65]
    DIRECTION OUTPUT ;
    USE SIGNAL ;
    SHAPE ABUTMENT ;
    PORT
      LAYER M3 ;
      RECT 43.393 0.000 43.407 0.042 ;
    END
  END rw0_rd_out[65]
  PIN rw0_rd_out[66]
    DIRECTION OUTPUT ;
    USE SIGNAL ;
    SHAPE ABUTMENT ;
    PORT
      LAYER M3 ;
      RECT 43.617 0.000 43.631 0.042 ;
    END
  END rw0_rd_out[66]
  PIN rw0_rd_out[67]
    DIRECTION OUTPUT ;
    USE SIGNAL ;
    SHAPE ABUTMENT ;
    PORT
      LAYER M3 ;
      RECT 43.841 0.000 43.855 0.042 ;
    END
  END rw0_rd_out[67]
  PIN rw0_rd_out[68]
    DIRECTION OUTPUT ;
    USE SIGNAL ;
    SHAPE ABUTMENT ;
    PORT
      LAYER M3 ;
      RECT 44.065 0.000 44.079 0.042 ;
    END
  END rw0_rd_out[68]
  PIN rw0_rd_out[69]
    DIRECTION OUTPUT ;
    USE SIGNAL ;
    SHAPE ABUTMENT ;
    PORT
      LAYER M3 ;
      RECT 44.289 0.000 44.303 0.042 ;
    END
  END rw0_rd_out[69]
  PIN rw0_rd_out[70]
    DIRECTION OUTPUT ;
    USE SIGNAL ;
    SHAPE ABUTMENT ;
    PORT
      LAYER M3 ;
      RECT 44.513 0.000 44.527 0.042 ;
    END
  END rw0_rd_out[70]
  PIN rw0_rd_out[71]
    DIRECTION OUTPUT ;
    USE SIGNAL ;
    SHAPE ABUTMENT ;
    PORT
      LAYER M3 ;
      RECT 44.737 0.000 44.751 0.042 ;
    END
  END rw0_rd_out[71]
  PIN rw0_rd_out[72]
    DIRECTION OUTPUT ;
    USE SIGNAL ;
    SHAPE ABUTMENT ;
    PORT
      LAYER M3 ;
      RECT 44.961 0.000 44.975 0.042 ;
    END
  END rw0_rd_out[72]
  PIN rw0_rd_out[73]
    DIRECTION OUTPUT ;
    USE SIGNAL ;
    SHAPE ABUTMENT ;
    PORT
      LAYER M3 ;
      RECT 45.185 0.000 45.199 0.042 ;
    END
  END rw0_rd_out[73]
  PIN rw0_rd_out[74]
    DIRECTION OUTPUT ;
    USE SIGNAL ;
    SHAPE ABUTMENT ;
    PORT
      LAYER M3 ;
      RECT 45.409 0.000 45.423 0.042 ;
    END
  END rw0_rd_out[74]
  PIN rw0_rd_out[75]
    DIRECTION OUTPUT ;
    USE SIGNAL ;
    SHAPE ABUTMENT ;
    PORT
      LAYER M3 ;
      RECT 45.633 0.000 45.647 0.042 ;
    END
  END rw0_rd_out[75]
  PIN rw0_rd_out[76]
    DIRECTION OUTPUT ;
    USE SIGNAL ;
    SHAPE ABUTMENT ;
    PORT
      LAYER M3 ;
      RECT 45.857 0.000 45.871 0.042 ;
    END
  END rw0_rd_out[76]
  PIN rw0_rd_out[77]
    DIRECTION OUTPUT ;
    USE SIGNAL ;
    SHAPE ABUTMENT ;
    PORT
      LAYER M3 ;
      RECT 46.081 0.000 46.095 0.042 ;
    END
  END rw0_rd_out[77]
  PIN rw0_rd_out[78]
    DIRECTION OUTPUT ;
    USE SIGNAL ;
    SHAPE ABUTMENT ;
    PORT
      LAYER M3 ;
      RECT 46.305 0.000 46.319 0.042 ;
    END
  END rw0_rd_out[78]
  PIN rw0_rd_out[79]
    DIRECTION OUTPUT ;
    USE SIGNAL ;
    SHAPE ABUTMENT ;
    PORT
      LAYER M3 ;
      RECT 46.529 0.000 46.543 0.042 ;
    END
  END rw0_rd_out[79]
  PIN rw0_rd_out[80]
    DIRECTION OUTPUT ;
    USE SIGNAL ;
    SHAPE ABUTMENT ;
    PORT
      LAYER M3 ;
      RECT 46.753 0.000 46.767 0.042 ;
    END
  END rw0_rd_out[80]
  PIN rw0_rd_out[81]
    DIRECTION OUTPUT ;
    USE SIGNAL ;
    SHAPE ABUTMENT ;
    PORT
      LAYER M3 ;
      RECT 46.977 0.000 46.991 0.042 ;
    END
  END rw0_rd_out[81]
  PIN rw0_rd_out[82]
    DIRECTION OUTPUT ;
    USE SIGNAL ;
    SHAPE ABUTMENT ;
    PORT
      LAYER M3 ;
      RECT 47.201 0.000 47.215 0.042 ;
    END
  END rw0_rd_out[82]
  PIN rw0_rd_out[83]
    DIRECTION OUTPUT ;
    USE SIGNAL ;
    SHAPE ABUTMENT ;
    PORT
      LAYER M3 ;
      RECT 47.425 0.000 47.439 0.042 ;
    END
  END rw0_rd_out[83]
  PIN rw0_rd_out[84]
    DIRECTION OUTPUT ;
    USE SIGNAL ;
    SHAPE ABUTMENT ;
    PORT
      LAYER M3 ;
      RECT 47.649 0.000 47.663 0.042 ;
    END
  END rw0_rd_out[84]
  PIN rw0_rd_out[85]
    DIRECTION OUTPUT ;
    USE SIGNAL ;
    SHAPE ABUTMENT ;
    PORT
      LAYER M3 ;
      RECT 47.873 0.000 47.887 0.042 ;
    END
  END rw0_rd_out[85]
  PIN rw0_rd_out[86]
    DIRECTION OUTPUT ;
    USE SIGNAL ;
    SHAPE ABUTMENT ;
    PORT
      LAYER M3 ;
      RECT 48.097 0.000 48.111 0.042 ;
    END
  END rw0_rd_out[86]
  PIN rw0_rd_out[87]
    DIRECTION OUTPUT ;
    USE SIGNAL ;
    SHAPE ABUTMENT ;
    PORT
      LAYER M3 ;
      RECT 48.321 0.000 48.335 0.042 ;
    END
  END rw0_rd_out[87]
  PIN rw0_rd_out[88]
    DIRECTION OUTPUT ;
    USE SIGNAL ;
    SHAPE ABUTMENT ;
    PORT
      LAYER M3 ;
      RECT 48.545 0.000 48.559 0.042 ;
    END
  END rw0_rd_out[88]
  PIN rw0_rd_out[89]
    DIRECTION OUTPUT ;
    USE SIGNAL ;
    SHAPE ABUTMENT ;
    PORT
      LAYER M3 ;
      RECT 48.769 0.000 48.783 0.042 ;
    END
  END rw0_rd_out[89]
  PIN rw0_rd_out[90]
    DIRECTION OUTPUT ;
    USE SIGNAL ;
    SHAPE ABUTMENT ;
    PORT
      LAYER M3 ;
      RECT 48.993 0.000 49.007 0.042 ;
    END
  END rw0_rd_out[90]
  PIN rw0_rd_out[91]
    DIRECTION OUTPUT ;
    USE SIGNAL ;
    SHAPE ABUTMENT ;
    PORT
      LAYER M3 ;
      RECT 49.217 0.000 49.231 0.042 ;
    END
  END rw0_rd_out[91]
  PIN rw0_rd_out[92]
    DIRECTION OUTPUT ;
    USE SIGNAL ;
    SHAPE ABUTMENT ;
    PORT
      LAYER M3 ;
      RECT 49.441 0.000 49.455 0.042 ;
    END
  END rw0_rd_out[92]
  PIN rw0_rd_out[93]
    DIRECTION OUTPUT ;
    USE SIGNAL ;
    SHAPE ABUTMENT ;
    PORT
      LAYER M3 ;
      RECT 49.665 0.000 49.679 0.042 ;
    END
  END rw0_rd_out[93]
  PIN rw0_rd_out[94]
    DIRECTION OUTPUT ;
    USE SIGNAL ;
    SHAPE ABUTMENT ;
    PORT
      LAYER M3 ;
      RECT 49.889 0.000 49.903 0.042 ;
    END
  END rw0_rd_out[94]
  PIN rw0_rd_out[95]
    DIRECTION OUTPUT ;
    USE SIGNAL ;
    SHAPE ABUTMENT ;
    PORT
      LAYER M3 ;
      RECT 50.113 0.000 50.127 0.042 ;
    END
  END rw0_rd_out[95]
  PIN rw0_rd_out[96]
    DIRECTION OUTPUT ;
    USE SIGNAL ;
    SHAPE ABUTMENT ;
    PORT
      LAYER M3 ;
      RECT 50.337 0.000 50.351 0.042 ;
    END
  END rw0_rd_out[96]
  PIN rw0_rd_out[97]
    DIRECTION OUTPUT ;
    USE SIGNAL ;
    SHAPE ABUTMENT ;
    PORT
      LAYER M3 ;
      RECT 50.561 0.000 50.575 0.042 ;
    END
  END rw0_rd_out[97]
  PIN rw0_rd_out[98]
    DIRECTION OUTPUT ;
    USE SIGNAL ;
    SHAPE ABUTMENT ;
    PORT
      LAYER M3 ;
      RECT 50.785 0.000 50.799 0.042 ;
    END
  END rw0_rd_out[98]
  PIN rw0_rd_out[99]
    DIRECTION OUTPUT ;
    USE SIGNAL ;
    SHAPE ABUTMENT ;
    PORT
      LAYER M3 ;
      RECT 51.009 0.000 51.023 0.042 ;
    END
  END rw0_rd_out[99]
  PIN rw0_rd_out[100]
    DIRECTION OUTPUT ;
    USE SIGNAL ;
    SHAPE ABUTMENT ;
    PORT
      LAYER M3 ;
      RECT 51.233 0.000 51.247 0.042 ;
    END
  END rw0_rd_out[100]
  PIN rw0_rd_out[101]
    DIRECTION OUTPUT ;
    USE SIGNAL ;
    SHAPE ABUTMENT ;
    PORT
      LAYER M3 ;
      RECT 51.457 0.000 51.471 0.042 ;
    END
  END rw0_rd_out[101]
  PIN rw0_rd_out[102]
    DIRECTION OUTPUT ;
    USE SIGNAL ;
    SHAPE ABUTMENT ;
    PORT
      LAYER M3 ;
      RECT 51.681 0.000 51.695 0.042 ;
    END
  END rw0_rd_out[102]
  PIN rw0_rd_out[103]
    DIRECTION OUTPUT ;
    USE SIGNAL ;
    SHAPE ABUTMENT ;
    PORT
      LAYER M3 ;
      RECT 51.905 0.000 51.919 0.042 ;
    END
  END rw0_rd_out[103]
  PIN rw0_rd_out[104]
    DIRECTION OUTPUT ;
    USE SIGNAL ;
    SHAPE ABUTMENT ;
    PORT
      LAYER M3 ;
      RECT 52.129 0.000 52.143 0.042 ;
    END
  END rw0_rd_out[104]
  PIN rw0_rd_out[105]
    DIRECTION OUTPUT ;
    USE SIGNAL ;
    SHAPE ABUTMENT ;
    PORT
      LAYER M3 ;
      RECT 52.353 0.000 52.367 0.042 ;
    END
  END rw0_rd_out[105]
  PIN rw0_rd_out[106]
    DIRECTION OUTPUT ;
    USE SIGNAL ;
    SHAPE ABUTMENT ;
    PORT
      LAYER M3 ;
      RECT 52.577 0.000 52.591 0.042 ;
    END
  END rw0_rd_out[106]
  PIN rw0_rd_out[107]
    DIRECTION OUTPUT ;
    USE SIGNAL ;
    SHAPE ABUTMENT ;
    PORT
      LAYER M3 ;
      RECT 52.801 0.000 52.815 0.042 ;
    END
  END rw0_rd_out[107]
  PIN rw0_rd_out[108]
    DIRECTION OUTPUT ;
    USE SIGNAL ;
    SHAPE ABUTMENT ;
    PORT
      LAYER M3 ;
      RECT 53.025 0.000 53.039 0.042 ;
    END
  END rw0_rd_out[108]
  PIN rw0_rd_out[109]
    DIRECTION OUTPUT ;
    USE SIGNAL ;
    SHAPE ABUTMENT ;
    PORT
      LAYER M3 ;
      RECT 53.249 0.000 53.263 0.042 ;
    END
  END rw0_rd_out[109]
  PIN rw0_rd_out[110]
    DIRECTION OUTPUT ;
    USE SIGNAL ;
    SHAPE ABUTMENT ;
    PORT
      LAYER M3 ;
      RECT 53.473 0.000 53.487 0.042 ;
    END
  END rw0_rd_out[110]
  PIN rw0_rd_out[111]
    DIRECTION OUTPUT ;
    USE SIGNAL ;
    SHAPE ABUTMENT ;
    PORT
      LAYER M3 ;
      RECT 53.697 0.000 53.711 0.042 ;
    END
  END rw0_rd_out[111]
  PIN rw0_rd_out[112]
    DIRECTION OUTPUT ;
    USE SIGNAL ;
    SHAPE ABUTMENT ;
    PORT
      LAYER M3 ;
      RECT 53.921 0.000 53.935 0.042 ;
    END
  END rw0_rd_out[112]
  PIN rw0_rd_out[113]
    DIRECTION OUTPUT ;
    USE SIGNAL ;
    SHAPE ABUTMENT ;
    PORT
      LAYER M3 ;
      RECT 54.145 0.000 54.159 0.042 ;
    END
  END rw0_rd_out[113]
  PIN rw0_rd_out[114]
    DIRECTION OUTPUT ;
    USE SIGNAL ;
    SHAPE ABUTMENT ;
    PORT
      LAYER M3 ;
      RECT 54.369 0.000 54.383 0.042 ;
    END
  END rw0_rd_out[114]
  PIN rw0_rd_out[115]
    DIRECTION OUTPUT ;
    USE SIGNAL ;
    SHAPE ABUTMENT ;
    PORT
      LAYER M3 ;
      RECT 54.593 0.000 54.607 0.042 ;
    END
  END rw0_rd_out[115]
  PIN rw0_rd_out[116]
    DIRECTION OUTPUT ;
    USE SIGNAL ;
    SHAPE ABUTMENT ;
    PORT
      LAYER M3 ;
      RECT 54.817 0.000 54.831 0.042 ;
    END
  END rw0_rd_out[116]
  PIN rw0_rd_out[117]
    DIRECTION OUTPUT ;
    USE SIGNAL ;
    SHAPE ABUTMENT ;
    PORT
      LAYER M3 ;
      RECT 55.041 0.000 55.055 0.042 ;
    END
  END rw0_rd_out[117]
  PIN rw0_rd_out[118]
    DIRECTION OUTPUT ;
    USE SIGNAL ;
    SHAPE ABUTMENT ;
    PORT
      LAYER M3 ;
      RECT 55.265 0.000 55.279 0.042 ;
    END
  END rw0_rd_out[118]
  PIN rw0_rd_out[119]
    DIRECTION OUTPUT ;
    USE SIGNAL ;
    SHAPE ABUTMENT ;
    PORT
      LAYER M3 ;
      RECT 55.489 0.000 55.503 0.042 ;
    END
  END rw0_rd_out[119]
  PIN rw0_rd_out[120]
    DIRECTION OUTPUT ;
    USE SIGNAL ;
    SHAPE ABUTMENT ;
    PORT
      LAYER M3 ;
      RECT 55.713 0.000 55.727 0.042 ;
    END
  END rw0_rd_out[120]
  PIN rw0_rd_out[121]
    DIRECTION OUTPUT ;
    USE SIGNAL ;
    SHAPE ABUTMENT ;
    PORT
      LAYER M3 ;
      RECT 55.937 0.000 55.951 0.042 ;
    END
  END rw0_rd_out[121]
  PIN rw0_rd_out[122]
    DIRECTION OUTPUT ;
    USE SIGNAL ;
    SHAPE ABUTMENT ;
    PORT
      LAYER M3 ;
      RECT 56.161 0.000 56.175 0.042 ;
    END
  END rw0_rd_out[122]
  PIN rw0_rd_out[123]
    DIRECTION OUTPUT ;
    USE SIGNAL ;
    SHAPE ABUTMENT ;
    PORT
      LAYER M3 ;
      RECT 56.385 0.000 56.399 0.042 ;
    END
  END rw0_rd_out[123]
  PIN rw0_rd_out[124]
    DIRECTION OUTPUT ;
    USE SIGNAL ;
    SHAPE ABUTMENT ;
    PORT
      LAYER M3 ;
      RECT 56.609 0.000 56.623 0.042 ;
    END
  END rw0_rd_out[124]
  PIN rw0_rd_out[125]
    DIRECTION OUTPUT ;
    USE SIGNAL ;
    SHAPE ABUTMENT ;
    PORT
      LAYER M3 ;
      RECT 56.833 0.000 56.847 0.042 ;
    END
  END rw0_rd_out[125]
  PIN rw0_rd_out[126]
    DIRECTION OUTPUT ;
    USE SIGNAL ;
    SHAPE ABUTMENT ;
    PORT
      LAYER M3 ;
      RECT 57.057 0.000 57.071 0.042 ;
    END
  END rw0_rd_out[126]
  PIN rw0_rd_out[127]
    DIRECTION OUTPUT ;
    USE SIGNAL ;
    SHAPE ABUTMENT ;
    PORT
      LAYER M3 ;
      RECT 57.281 0.000 57.295 0.042 ;
    END
  END rw0_rd_out[127]
  PIN rw0_rd_out[128]
    DIRECTION OUTPUT ;
    USE SIGNAL ;
    SHAPE ABUTMENT ;
    PORT
      LAYER M3 ;
      RECT 28.833 76.710 28.847 76.752 ;
    END
  END rw0_rd_out[128]
  PIN rw0_rd_out[129]
    DIRECTION OUTPUT ;
    USE SIGNAL ;
    SHAPE ABUTMENT ;
    PORT
      LAYER M3 ;
      RECT 29.057 76.710 29.071 76.752 ;
    END
  END rw0_rd_out[129]
  PIN rw0_rd_out[130]
    DIRECTION OUTPUT ;
    USE SIGNAL ;
    SHAPE ABUTMENT ;
    PORT
      LAYER M3 ;
      RECT 29.281 76.710 29.295 76.752 ;
    END
  END rw0_rd_out[130]
  PIN rw0_rd_out[131]
    DIRECTION OUTPUT ;
    USE SIGNAL ;
    SHAPE ABUTMENT ;
    PORT
      LAYER M3 ;
      RECT 29.505 76.710 29.519 76.752 ;
    END
  END rw0_rd_out[131]
  PIN rw0_rd_out[132]
    DIRECTION OUTPUT ;
    USE SIGNAL ;
    SHAPE ABUTMENT ;
    PORT
      LAYER M3 ;
      RECT 29.729 76.710 29.743 76.752 ;
    END
  END rw0_rd_out[132]
  PIN rw0_rd_out[133]
    DIRECTION OUTPUT ;
    USE SIGNAL ;
    SHAPE ABUTMENT ;
    PORT
      LAYER M3 ;
      RECT 29.953 76.710 29.967 76.752 ;
    END
  END rw0_rd_out[133]
  PIN rw0_rd_out[134]
    DIRECTION OUTPUT ;
    USE SIGNAL ;
    SHAPE ABUTMENT ;
    PORT
      LAYER M3 ;
      RECT 30.177 76.710 30.191 76.752 ;
    END
  END rw0_rd_out[134]
  PIN rw0_rd_out[135]
    DIRECTION OUTPUT ;
    USE SIGNAL ;
    SHAPE ABUTMENT ;
    PORT
      LAYER M3 ;
      RECT 30.401 76.710 30.415 76.752 ;
    END
  END rw0_rd_out[135]
  PIN rw0_rd_out[136]
    DIRECTION OUTPUT ;
    USE SIGNAL ;
    SHAPE ABUTMENT ;
    PORT
      LAYER M3 ;
      RECT 30.625 76.710 30.639 76.752 ;
    END
  END rw0_rd_out[136]
  PIN rw0_rd_out[137]
    DIRECTION OUTPUT ;
    USE SIGNAL ;
    SHAPE ABUTMENT ;
    PORT
      LAYER M3 ;
      RECT 30.849 76.710 30.863 76.752 ;
    END
  END rw0_rd_out[137]
  PIN rw0_rd_out[138]
    DIRECTION OUTPUT ;
    USE SIGNAL ;
    SHAPE ABUTMENT ;
    PORT
      LAYER M3 ;
      RECT 31.073 76.710 31.087 76.752 ;
    END
  END rw0_rd_out[138]
  PIN rw0_rd_out[139]
    DIRECTION OUTPUT ;
    USE SIGNAL ;
    SHAPE ABUTMENT ;
    PORT
      LAYER M3 ;
      RECT 31.297 76.710 31.311 76.752 ;
    END
  END rw0_rd_out[139]
  PIN rw0_rd_out[140]
    DIRECTION OUTPUT ;
    USE SIGNAL ;
    SHAPE ABUTMENT ;
    PORT
      LAYER M3 ;
      RECT 31.521 76.710 31.535 76.752 ;
    END
  END rw0_rd_out[140]
  PIN rw0_rd_out[141]
    DIRECTION OUTPUT ;
    USE SIGNAL ;
    SHAPE ABUTMENT ;
    PORT
      LAYER M3 ;
      RECT 31.745 76.710 31.759 76.752 ;
    END
  END rw0_rd_out[141]
  PIN rw0_rd_out[142]
    DIRECTION OUTPUT ;
    USE SIGNAL ;
    SHAPE ABUTMENT ;
    PORT
      LAYER M3 ;
      RECT 31.969 76.710 31.983 76.752 ;
    END
  END rw0_rd_out[142]
  PIN rw0_rd_out[143]
    DIRECTION OUTPUT ;
    USE SIGNAL ;
    SHAPE ABUTMENT ;
    PORT
      LAYER M3 ;
      RECT 32.193 76.710 32.207 76.752 ;
    END
  END rw0_rd_out[143]
  PIN rw0_rd_out[144]
    DIRECTION OUTPUT ;
    USE SIGNAL ;
    SHAPE ABUTMENT ;
    PORT
      LAYER M3 ;
      RECT 32.417 76.710 32.431 76.752 ;
    END
  END rw0_rd_out[144]
  PIN rw0_rd_out[145]
    DIRECTION OUTPUT ;
    USE SIGNAL ;
    SHAPE ABUTMENT ;
    PORT
      LAYER M3 ;
      RECT 32.641 76.710 32.655 76.752 ;
    END
  END rw0_rd_out[145]
  PIN rw0_rd_out[146]
    DIRECTION OUTPUT ;
    USE SIGNAL ;
    SHAPE ABUTMENT ;
    PORT
      LAYER M3 ;
      RECT 32.865 76.710 32.879 76.752 ;
    END
  END rw0_rd_out[146]
  PIN rw0_rd_out[147]
    DIRECTION OUTPUT ;
    USE SIGNAL ;
    SHAPE ABUTMENT ;
    PORT
      LAYER M3 ;
      RECT 33.089 76.710 33.103 76.752 ;
    END
  END rw0_rd_out[147]
  PIN rw0_rd_out[148]
    DIRECTION OUTPUT ;
    USE SIGNAL ;
    SHAPE ABUTMENT ;
    PORT
      LAYER M3 ;
      RECT 33.313 76.710 33.327 76.752 ;
    END
  END rw0_rd_out[148]
  PIN rw0_rd_out[149]
    DIRECTION OUTPUT ;
    USE SIGNAL ;
    SHAPE ABUTMENT ;
    PORT
      LAYER M3 ;
      RECT 33.537 76.710 33.551 76.752 ;
    END
  END rw0_rd_out[149]
  PIN rw0_rd_out[150]
    DIRECTION OUTPUT ;
    USE SIGNAL ;
    SHAPE ABUTMENT ;
    PORT
      LAYER M3 ;
      RECT 33.761 76.710 33.775 76.752 ;
    END
  END rw0_rd_out[150]
  PIN rw0_rd_out[151]
    DIRECTION OUTPUT ;
    USE SIGNAL ;
    SHAPE ABUTMENT ;
    PORT
      LAYER M3 ;
      RECT 33.985 76.710 33.999 76.752 ;
    END
  END rw0_rd_out[151]
  PIN rw0_rd_out[152]
    DIRECTION OUTPUT ;
    USE SIGNAL ;
    SHAPE ABUTMENT ;
    PORT
      LAYER M3 ;
      RECT 34.209 76.710 34.223 76.752 ;
    END
  END rw0_rd_out[152]
  PIN rw0_rd_out[153]
    DIRECTION OUTPUT ;
    USE SIGNAL ;
    SHAPE ABUTMENT ;
    PORT
      LAYER M3 ;
      RECT 34.433 76.710 34.447 76.752 ;
    END
  END rw0_rd_out[153]
  PIN rw0_rd_out[154]
    DIRECTION OUTPUT ;
    USE SIGNAL ;
    SHAPE ABUTMENT ;
    PORT
      LAYER M3 ;
      RECT 34.657 76.710 34.671 76.752 ;
    END
  END rw0_rd_out[154]
  PIN rw0_rd_out[155]
    DIRECTION OUTPUT ;
    USE SIGNAL ;
    SHAPE ABUTMENT ;
    PORT
      LAYER M3 ;
      RECT 34.881 76.710 34.895 76.752 ;
    END
  END rw0_rd_out[155]
  PIN rw0_rd_out[156]
    DIRECTION OUTPUT ;
    USE SIGNAL ;
    SHAPE ABUTMENT ;
    PORT
      LAYER M3 ;
      RECT 35.105 76.710 35.119 76.752 ;
    END
  END rw0_rd_out[156]
  PIN rw0_rd_out[157]
    DIRECTION OUTPUT ;
    USE SIGNAL ;
    SHAPE ABUTMENT ;
    PORT
      LAYER M3 ;
      RECT 35.329 76.710 35.343 76.752 ;
    END
  END rw0_rd_out[157]
  PIN rw0_rd_out[158]
    DIRECTION OUTPUT ;
    USE SIGNAL ;
    SHAPE ABUTMENT ;
    PORT
      LAYER M3 ;
      RECT 35.553 76.710 35.567 76.752 ;
    END
  END rw0_rd_out[158]
  PIN rw0_rd_out[159]
    DIRECTION OUTPUT ;
    USE SIGNAL ;
    SHAPE ABUTMENT ;
    PORT
      LAYER M3 ;
      RECT 35.777 76.710 35.791 76.752 ;
    END
  END rw0_rd_out[159]
  PIN rw0_rd_out[160]
    DIRECTION OUTPUT ;
    USE SIGNAL ;
    SHAPE ABUTMENT ;
    PORT
      LAYER M3 ;
      RECT 36.001 76.710 36.015 76.752 ;
    END
  END rw0_rd_out[160]
  PIN rw0_rd_out[161]
    DIRECTION OUTPUT ;
    USE SIGNAL ;
    SHAPE ABUTMENT ;
    PORT
      LAYER M3 ;
      RECT 36.225 76.710 36.239 76.752 ;
    END
  END rw0_rd_out[161]
  PIN rw0_rd_out[162]
    DIRECTION OUTPUT ;
    USE SIGNAL ;
    SHAPE ABUTMENT ;
    PORT
      LAYER M3 ;
      RECT 36.449 76.710 36.463 76.752 ;
    END
  END rw0_rd_out[162]
  PIN rw0_rd_out[163]
    DIRECTION OUTPUT ;
    USE SIGNAL ;
    SHAPE ABUTMENT ;
    PORT
      LAYER M3 ;
      RECT 36.673 76.710 36.687 76.752 ;
    END
  END rw0_rd_out[163]
  PIN rw0_rd_out[164]
    DIRECTION OUTPUT ;
    USE SIGNAL ;
    SHAPE ABUTMENT ;
    PORT
      LAYER M3 ;
      RECT 36.897 76.710 36.911 76.752 ;
    END
  END rw0_rd_out[164]
  PIN rw0_rd_out[165]
    DIRECTION OUTPUT ;
    USE SIGNAL ;
    SHAPE ABUTMENT ;
    PORT
      LAYER M3 ;
      RECT 37.121 76.710 37.135 76.752 ;
    END
  END rw0_rd_out[165]
  PIN rw0_rd_out[166]
    DIRECTION OUTPUT ;
    USE SIGNAL ;
    SHAPE ABUTMENT ;
    PORT
      LAYER M3 ;
      RECT 37.345 76.710 37.359 76.752 ;
    END
  END rw0_rd_out[166]
  PIN rw0_rd_out[167]
    DIRECTION OUTPUT ;
    USE SIGNAL ;
    SHAPE ABUTMENT ;
    PORT
      LAYER M3 ;
      RECT 37.569 76.710 37.583 76.752 ;
    END
  END rw0_rd_out[167]
  PIN rw0_rd_out[168]
    DIRECTION OUTPUT ;
    USE SIGNAL ;
    SHAPE ABUTMENT ;
    PORT
      LAYER M3 ;
      RECT 37.793 76.710 37.807 76.752 ;
    END
  END rw0_rd_out[168]
  PIN rw0_rd_out[169]
    DIRECTION OUTPUT ;
    USE SIGNAL ;
    SHAPE ABUTMENT ;
    PORT
      LAYER M3 ;
      RECT 38.017 76.710 38.031 76.752 ;
    END
  END rw0_rd_out[169]
  PIN rw0_rd_out[170]
    DIRECTION OUTPUT ;
    USE SIGNAL ;
    SHAPE ABUTMENT ;
    PORT
      LAYER M3 ;
      RECT 38.241 76.710 38.255 76.752 ;
    END
  END rw0_rd_out[170]
  PIN rw0_rd_out[171]
    DIRECTION OUTPUT ;
    USE SIGNAL ;
    SHAPE ABUTMENT ;
    PORT
      LAYER M3 ;
      RECT 38.465 76.710 38.479 76.752 ;
    END
  END rw0_rd_out[171]
  PIN rw0_rd_out[172]
    DIRECTION OUTPUT ;
    USE SIGNAL ;
    SHAPE ABUTMENT ;
    PORT
      LAYER M3 ;
      RECT 38.689 76.710 38.703 76.752 ;
    END
  END rw0_rd_out[172]
  PIN rw0_rd_out[173]
    DIRECTION OUTPUT ;
    USE SIGNAL ;
    SHAPE ABUTMENT ;
    PORT
      LAYER M3 ;
      RECT 38.913 76.710 38.927 76.752 ;
    END
  END rw0_rd_out[173]
  PIN rw0_rd_out[174]
    DIRECTION OUTPUT ;
    USE SIGNAL ;
    SHAPE ABUTMENT ;
    PORT
      LAYER M3 ;
      RECT 39.137 76.710 39.151 76.752 ;
    END
  END rw0_rd_out[174]
  PIN rw0_rd_out[175]
    DIRECTION OUTPUT ;
    USE SIGNAL ;
    SHAPE ABUTMENT ;
    PORT
      LAYER M3 ;
      RECT 39.361 76.710 39.375 76.752 ;
    END
  END rw0_rd_out[175]
  PIN rw0_rd_out[176]
    DIRECTION OUTPUT ;
    USE SIGNAL ;
    SHAPE ABUTMENT ;
    PORT
      LAYER M3 ;
      RECT 39.585 76.710 39.599 76.752 ;
    END
  END rw0_rd_out[176]
  PIN rw0_rd_out[177]
    DIRECTION OUTPUT ;
    USE SIGNAL ;
    SHAPE ABUTMENT ;
    PORT
      LAYER M3 ;
      RECT 39.809 76.710 39.823 76.752 ;
    END
  END rw0_rd_out[177]
  PIN rw0_rd_out[178]
    DIRECTION OUTPUT ;
    USE SIGNAL ;
    SHAPE ABUTMENT ;
    PORT
      LAYER M3 ;
      RECT 40.033 76.710 40.047 76.752 ;
    END
  END rw0_rd_out[178]
  PIN rw0_rd_out[179]
    DIRECTION OUTPUT ;
    USE SIGNAL ;
    SHAPE ABUTMENT ;
    PORT
      LAYER M3 ;
      RECT 40.257 76.710 40.271 76.752 ;
    END
  END rw0_rd_out[179]
  PIN rw0_rd_out[180]
    DIRECTION OUTPUT ;
    USE SIGNAL ;
    SHAPE ABUTMENT ;
    PORT
      LAYER M3 ;
      RECT 40.481 76.710 40.495 76.752 ;
    END
  END rw0_rd_out[180]
  PIN rw0_rd_out[181]
    DIRECTION OUTPUT ;
    USE SIGNAL ;
    SHAPE ABUTMENT ;
    PORT
      LAYER M3 ;
      RECT 40.705 76.710 40.719 76.752 ;
    END
  END rw0_rd_out[181]
  PIN rw0_rd_out[182]
    DIRECTION OUTPUT ;
    USE SIGNAL ;
    SHAPE ABUTMENT ;
    PORT
      LAYER M3 ;
      RECT 40.929 76.710 40.943 76.752 ;
    END
  END rw0_rd_out[182]
  PIN rw0_rd_out[183]
    DIRECTION OUTPUT ;
    USE SIGNAL ;
    SHAPE ABUTMENT ;
    PORT
      LAYER M3 ;
      RECT 41.153 76.710 41.167 76.752 ;
    END
  END rw0_rd_out[183]
  PIN rw0_rd_out[184]
    DIRECTION OUTPUT ;
    USE SIGNAL ;
    SHAPE ABUTMENT ;
    PORT
      LAYER M3 ;
      RECT 41.377 76.710 41.391 76.752 ;
    END
  END rw0_rd_out[184]
  PIN rw0_rd_out[185]
    DIRECTION OUTPUT ;
    USE SIGNAL ;
    SHAPE ABUTMENT ;
    PORT
      LAYER M3 ;
      RECT 41.601 76.710 41.615 76.752 ;
    END
  END rw0_rd_out[185]
  PIN rw0_rd_out[186]
    DIRECTION OUTPUT ;
    USE SIGNAL ;
    SHAPE ABUTMENT ;
    PORT
      LAYER M3 ;
      RECT 41.825 76.710 41.839 76.752 ;
    END
  END rw0_rd_out[186]
  PIN rw0_rd_out[187]
    DIRECTION OUTPUT ;
    USE SIGNAL ;
    SHAPE ABUTMENT ;
    PORT
      LAYER M3 ;
      RECT 42.049 76.710 42.063 76.752 ;
    END
  END rw0_rd_out[187]
  PIN rw0_rd_out[188]
    DIRECTION OUTPUT ;
    USE SIGNAL ;
    SHAPE ABUTMENT ;
    PORT
      LAYER M3 ;
      RECT 42.273 76.710 42.287 76.752 ;
    END
  END rw0_rd_out[188]
  PIN rw0_rd_out[189]
    DIRECTION OUTPUT ;
    USE SIGNAL ;
    SHAPE ABUTMENT ;
    PORT
      LAYER M3 ;
      RECT 42.497 76.710 42.511 76.752 ;
    END
  END rw0_rd_out[189]
  PIN rw0_rd_out[190]
    DIRECTION OUTPUT ;
    USE SIGNAL ;
    SHAPE ABUTMENT ;
    PORT
      LAYER M3 ;
      RECT 42.721 76.710 42.735 76.752 ;
    END
  END rw0_rd_out[190]
  PIN rw0_rd_out[191]
    DIRECTION OUTPUT ;
    USE SIGNAL ;
    SHAPE ABUTMENT ;
    PORT
      LAYER M3 ;
      RECT 42.945 76.710 42.959 76.752 ;
    END
  END rw0_rd_out[191]
  PIN rw0_rd_out[192]
    DIRECTION OUTPUT ;
    USE SIGNAL ;
    SHAPE ABUTMENT ;
    PORT
      LAYER M3 ;
      RECT 43.169 76.710 43.183 76.752 ;
    END
  END rw0_rd_out[192]
  PIN rw0_rd_out[193]
    DIRECTION OUTPUT ;
    USE SIGNAL ;
    SHAPE ABUTMENT ;
    PORT
      LAYER M3 ;
      RECT 43.393 76.710 43.407 76.752 ;
    END
  END rw0_rd_out[193]
  PIN rw0_rd_out[194]
    DIRECTION OUTPUT ;
    USE SIGNAL ;
    SHAPE ABUTMENT ;
    PORT
      LAYER M3 ;
      RECT 43.617 76.710 43.631 76.752 ;
    END
  END rw0_rd_out[194]
  PIN rw0_rd_out[195]
    DIRECTION OUTPUT ;
    USE SIGNAL ;
    SHAPE ABUTMENT ;
    PORT
      LAYER M3 ;
      RECT 43.841 76.710 43.855 76.752 ;
    END
  END rw0_rd_out[195]
  PIN rw0_rd_out[196]
    DIRECTION OUTPUT ;
    USE SIGNAL ;
    SHAPE ABUTMENT ;
    PORT
      LAYER M3 ;
      RECT 44.065 76.710 44.079 76.752 ;
    END
  END rw0_rd_out[196]
  PIN rw0_rd_out[197]
    DIRECTION OUTPUT ;
    USE SIGNAL ;
    SHAPE ABUTMENT ;
    PORT
      LAYER M3 ;
      RECT 44.289 76.710 44.303 76.752 ;
    END
  END rw0_rd_out[197]
  PIN rw0_rd_out[198]
    DIRECTION OUTPUT ;
    USE SIGNAL ;
    SHAPE ABUTMENT ;
    PORT
      LAYER M3 ;
      RECT 44.513 76.710 44.527 76.752 ;
    END
  END rw0_rd_out[198]
  PIN rw0_rd_out[199]
    DIRECTION OUTPUT ;
    USE SIGNAL ;
    SHAPE ABUTMENT ;
    PORT
      LAYER M3 ;
      RECT 44.737 76.710 44.751 76.752 ;
    END
  END rw0_rd_out[199]
  PIN rw0_rd_out[200]
    DIRECTION OUTPUT ;
    USE SIGNAL ;
    SHAPE ABUTMENT ;
    PORT
      LAYER M3 ;
      RECT 44.961 76.710 44.975 76.752 ;
    END
  END rw0_rd_out[200]
  PIN rw0_rd_out[201]
    DIRECTION OUTPUT ;
    USE SIGNAL ;
    SHAPE ABUTMENT ;
    PORT
      LAYER M3 ;
      RECT 45.185 76.710 45.199 76.752 ;
    END
  END rw0_rd_out[201]
  PIN rw0_rd_out[202]
    DIRECTION OUTPUT ;
    USE SIGNAL ;
    SHAPE ABUTMENT ;
    PORT
      LAYER M3 ;
      RECT 45.409 76.710 45.423 76.752 ;
    END
  END rw0_rd_out[202]
  PIN rw0_rd_out[203]
    DIRECTION OUTPUT ;
    USE SIGNAL ;
    SHAPE ABUTMENT ;
    PORT
      LAYER M3 ;
      RECT 45.633 76.710 45.647 76.752 ;
    END
  END rw0_rd_out[203]
  PIN rw0_rd_out[204]
    DIRECTION OUTPUT ;
    USE SIGNAL ;
    SHAPE ABUTMENT ;
    PORT
      LAYER M3 ;
      RECT 45.857 76.710 45.871 76.752 ;
    END
  END rw0_rd_out[204]
  PIN rw0_rd_out[205]
    DIRECTION OUTPUT ;
    USE SIGNAL ;
    SHAPE ABUTMENT ;
    PORT
      LAYER M3 ;
      RECT 46.081 76.710 46.095 76.752 ;
    END
  END rw0_rd_out[205]
  PIN rw0_rd_out[206]
    DIRECTION OUTPUT ;
    USE SIGNAL ;
    SHAPE ABUTMENT ;
    PORT
      LAYER M3 ;
      RECT 46.305 76.710 46.319 76.752 ;
    END
  END rw0_rd_out[206]
  PIN rw0_rd_out[207]
    DIRECTION OUTPUT ;
    USE SIGNAL ;
    SHAPE ABUTMENT ;
    PORT
      LAYER M3 ;
      RECT 46.529 76.710 46.543 76.752 ;
    END
  END rw0_rd_out[207]
  PIN rw0_rd_out[208]
    DIRECTION OUTPUT ;
    USE SIGNAL ;
    SHAPE ABUTMENT ;
    PORT
      LAYER M3 ;
      RECT 46.753 76.710 46.767 76.752 ;
    END
  END rw0_rd_out[208]
  PIN rw0_rd_out[209]
    DIRECTION OUTPUT ;
    USE SIGNAL ;
    SHAPE ABUTMENT ;
    PORT
      LAYER M3 ;
      RECT 46.977 76.710 46.991 76.752 ;
    END
  END rw0_rd_out[209]
  PIN rw0_rd_out[210]
    DIRECTION OUTPUT ;
    USE SIGNAL ;
    SHAPE ABUTMENT ;
    PORT
      LAYER M3 ;
      RECT 47.201 76.710 47.215 76.752 ;
    END
  END rw0_rd_out[210]
  PIN rw0_rd_out[211]
    DIRECTION OUTPUT ;
    USE SIGNAL ;
    SHAPE ABUTMENT ;
    PORT
      LAYER M3 ;
      RECT 47.425 76.710 47.439 76.752 ;
    END
  END rw0_rd_out[211]
  PIN rw0_rd_out[212]
    DIRECTION OUTPUT ;
    USE SIGNAL ;
    SHAPE ABUTMENT ;
    PORT
      LAYER M3 ;
      RECT 47.649 76.710 47.663 76.752 ;
    END
  END rw0_rd_out[212]
  PIN rw0_rd_out[213]
    DIRECTION OUTPUT ;
    USE SIGNAL ;
    SHAPE ABUTMENT ;
    PORT
      LAYER M3 ;
      RECT 47.873 76.710 47.887 76.752 ;
    END
  END rw0_rd_out[213]
  PIN rw0_rd_out[214]
    DIRECTION OUTPUT ;
    USE SIGNAL ;
    SHAPE ABUTMENT ;
    PORT
      LAYER M3 ;
      RECT 48.097 76.710 48.111 76.752 ;
    END
  END rw0_rd_out[214]
  PIN rw0_rd_out[215]
    DIRECTION OUTPUT ;
    USE SIGNAL ;
    SHAPE ABUTMENT ;
    PORT
      LAYER M3 ;
      RECT 48.321 76.710 48.335 76.752 ;
    END
  END rw0_rd_out[215]
  PIN rw0_rd_out[216]
    DIRECTION OUTPUT ;
    USE SIGNAL ;
    SHAPE ABUTMENT ;
    PORT
      LAYER M3 ;
      RECT 48.545 76.710 48.559 76.752 ;
    END
  END rw0_rd_out[216]
  PIN rw0_rd_out[217]
    DIRECTION OUTPUT ;
    USE SIGNAL ;
    SHAPE ABUTMENT ;
    PORT
      LAYER M3 ;
      RECT 48.769 76.710 48.783 76.752 ;
    END
  END rw0_rd_out[217]
  PIN rw0_rd_out[218]
    DIRECTION OUTPUT ;
    USE SIGNAL ;
    SHAPE ABUTMENT ;
    PORT
      LAYER M3 ;
      RECT 48.993 76.710 49.007 76.752 ;
    END
  END rw0_rd_out[218]
  PIN rw0_rd_out[219]
    DIRECTION OUTPUT ;
    USE SIGNAL ;
    SHAPE ABUTMENT ;
    PORT
      LAYER M3 ;
      RECT 49.217 76.710 49.231 76.752 ;
    END
  END rw0_rd_out[219]
  PIN rw0_rd_out[220]
    DIRECTION OUTPUT ;
    USE SIGNAL ;
    SHAPE ABUTMENT ;
    PORT
      LAYER M3 ;
      RECT 49.441 76.710 49.455 76.752 ;
    END
  END rw0_rd_out[220]
  PIN rw0_rd_out[221]
    DIRECTION OUTPUT ;
    USE SIGNAL ;
    SHAPE ABUTMENT ;
    PORT
      LAYER M3 ;
      RECT 49.665 76.710 49.679 76.752 ;
    END
  END rw0_rd_out[221]
  PIN rw0_rd_out[222]
    DIRECTION OUTPUT ;
    USE SIGNAL ;
    SHAPE ABUTMENT ;
    PORT
      LAYER M3 ;
      RECT 49.889 76.710 49.903 76.752 ;
    END
  END rw0_rd_out[222]
  PIN rw0_rd_out[223]
    DIRECTION OUTPUT ;
    USE SIGNAL ;
    SHAPE ABUTMENT ;
    PORT
      LAYER M3 ;
      RECT 50.113 76.710 50.127 76.752 ;
    END
  END rw0_rd_out[223]
  PIN rw0_rd_out[224]
    DIRECTION OUTPUT ;
    USE SIGNAL ;
    SHAPE ABUTMENT ;
    PORT
      LAYER M3 ;
      RECT 50.337 76.710 50.351 76.752 ;
    END
  END rw0_rd_out[224]
  PIN rw0_rd_out[225]
    DIRECTION OUTPUT ;
    USE SIGNAL ;
    SHAPE ABUTMENT ;
    PORT
      LAYER M3 ;
      RECT 50.561 76.710 50.575 76.752 ;
    END
  END rw0_rd_out[225]
  PIN rw0_rd_out[226]
    DIRECTION OUTPUT ;
    USE SIGNAL ;
    SHAPE ABUTMENT ;
    PORT
      LAYER M3 ;
      RECT 50.785 76.710 50.799 76.752 ;
    END
  END rw0_rd_out[226]
  PIN rw0_rd_out[227]
    DIRECTION OUTPUT ;
    USE SIGNAL ;
    SHAPE ABUTMENT ;
    PORT
      LAYER M3 ;
      RECT 51.009 76.710 51.023 76.752 ;
    END
  END rw0_rd_out[227]
  PIN rw0_rd_out[228]
    DIRECTION OUTPUT ;
    USE SIGNAL ;
    SHAPE ABUTMENT ;
    PORT
      LAYER M3 ;
      RECT 51.233 76.710 51.247 76.752 ;
    END
  END rw0_rd_out[228]
  PIN rw0_rd_out[229]
    DIRECTION OUTPUT ;
    USE SIGNAL ;
    SHAPE ABUTMENT ;
    PORT
      LAYER M3 ;
      RECT 51.457 76.710 51.471 76.752 ;
    END
  END rw0_rd_out[229]
  PIN rw0_rd_out[230]
    DIRECTION OUTPUT ;
    USE SIGNAL ;
    SHAPE ABUTMENT ;
    PORT
      LAYER M3 ;
      RECT 51.681 76.710 51.695 76.752 ;
    END
  END rw0_rd_out[230]
  PIN rw0_rd_out[231]
    DIRECTION OUTPUT ;
    USE SIGNAL ;
    SHAPE ABUTMENT ;
    PORT
      LAYER M3 ;
      RECT 51.905 76.710 51.919 76.752 ;
    END
  END rw0_rd_out[231]
  PIN rw0_rd_out[232]
    DIRECTION OUTPUT ;
    USE SIGNAL ;
    SHAPE ABUTMENT ;
    PORT
      LAYER M3 ;
      RECT 52.129 76.710 52.143 76.752 ;
    END
  END rw0_rd_out[232]
  PIN rw0_rd_out[233]
    DIRECTION OUTPUT ;
    USE SIGNAL ;
    SHAPE ABUTMENT ;
    PORT
      LAYER M3 ;
      RECT 52.353 76.710 52.367 76.752 ;
    END
  END rw0_rd_out[233]
  PIN rw0_rd_out[234]
    DIRECTION OUTPUT ;
    USE SIGNAL ;
    SHAPE ABUTMENT ;
    PORT
      LAYER M3 ;
      RECT 52.577 76.710 52.591 76.752 ;
    END
  END rw0_rd_out[234]
  PIN rw0_rd_out[235]
    DIRECTION OUTPUT ;
    USE SIGNAL ;
    SHAPE ABUTMENT ;
    PORT
      LAYER M3 ;
      RECT 52.801 76.710 52.815 76.752 ;
    END
  END rw0_rd_out[235]
  PIN rw0_rd_out[236]
    DIRECTION OUTPUT ;
    USE SIGNAL ;
    SHAPE ABUTMENT ;
    PORT
      LAYER M3 ;
      RECT 53.025 76.710 53.039 76.752 ;
    END
  END rw0_rd_out[236]
  PIN rw0_rd_out[237]
    DIRECTION OUTPUT ;
    USE SIGNAL ;
    SHAPE ABUTMENT ;
    PORT
      LAYER M3 ;
      RECT 53.249 76.710 53.263 76.752 ;
    END
  END rw0_rd_out[237]
  PIN rw0_rd_out[238]
    DIRECTION OUTPUT ;
    USE SIGNAL ;
    SHAPE ABUTMENT ;
    PORT
      LAYER M3 ;
      RECT 53.473 76.710 53.487 76.752 ;
    END
  END rw0_rd_out[238]
  PIN rw0_rd_out[239]
    DIRECTION OUTPUT ;
    USE SIGNAL ;
    SHAPE ABUTMENT ;
    PORT
      LAYER M3 ;
      RECT 53.697 76.710 53.711 76.752 ;
    END
  END rw0_rd_out[239]
  PIN rw0_rd_out[240]
    DIRECTION OUTPUT ;
    USE SIGNAL ;
    SHAPE ABUTMENT ;
    PORT
      LAYER M3 ;
      RECT 53.921 76.710 53.935 76.752 ;
    END
  END rw0_rd_out[240]
  PIN rw0_rd_out[241]
    DIRECTION OUTPUT ;
    USE SIGNAL ;
    SHAPE ABUTMENT ;
    PORT
      LAYER M3 ;
      RECT 54.145 76.710 54.159 76.752 ;
    END
  END rw0_rd_out[241]
  PIN rw0_rd_out[242]
    DIRECTION OUTPUT ;
    USE SIGNAL ;
    SHAPE ABUTMENT ;
    PORT
      LAYER M3 ;
      RECT 54.369 76.710 54.383 76.752 ;
    END
  END rw0_rd_out[242]
  PIN rw0_rd_out[243]
    DIRECTION OUTPUT ;
    USE SIGNAL ;
    SHAPE ABUTMENT ;
    PORT
      LAYER M3 ;
      RECT 54.593 76.710 54.607 76.752 ;
    END
  END rw0_rd_out[243]
  PIN rw0_rd_out[244]
    DIRECTION OUTPUT ;
    USE SIGNAL ;
    SHAPE ABUTMENT ;
    PORT
      LAYER M3 ;
      RECT 54.817 76.710 54.831 76.752 ;
    END
  END rw0_rd_out[244]
  PIN rw0_rd_out[245]
    DIRECTION OUTPUT ;
    USE SIGNAL ;
    SHAPE ABUTMENT ;
    PORT
      LAYER M3 ;
      RECT 55.041 76.710 55.055 76.752 ;
    END
  END rw0_rd_out[245]
  PIN rw0_rd_out[246]
    DIRECTION OUTPUT ;
    USE SIGNAL ;
    SHAPE ABUTMENT ;
    PORT
      LAYER M3 ;
      RECT 55.265 76.710 55.279 76.752 ;
    END
  END rw0_rd_out[246]
  PIN rw0_rd_out[247]
    DIRECTION OUTPUT ;
    USE SIGNAL ;
    SHAPE ABUTMENT ;
    PORT
      LAYER M3 ;
      RECT 55.489 76.710 55.503 76.752 ;
    END
  END rw0_rd_out[247]
  PIN rw0_rd_out[248]
    DIRECTION OUTPUT ;
    USE SIGNAL ;
    SHAPE ABUTMENT ;
    PORT
      LAYER M3 ;
      RECT 55.713 76.710 55.727 76.752 ;
    END
  END rw0_rd_out[248]
  PIN rw0_rd_out[249]
    DIRECTION OUTPUT ;
    USE SIGNAL ;
    SHAPE ABUTMENT ;
    PORT
      LAYER M3 ;
      RECT 55.937 76.710 55.951 76.752 ;
    END
  END rw0_rd_out[249]
  PIN rw0_rd_out[250]
    DIRECTION OUTPUT ;
    USE SIGNAL ;
    SHAPE ABUTMENT ;
    PORT
      LAYER M3 ;
      RECT 56.161 76.710 56.175 76.752 ;
    END
  END rw0_rd_out[250]
  PIN rw0_rd_out[251]
    DIRECTION OUTPUT ;
    USE SIGNAL ;
    SHAPE ABUTMENT ;
    PORT
      LAYER M3 ;
      RECT 56.385 76.710 56.399 76.752 ;
    END
  END rw0_rd_out[251]
  PIN rw0_rd_out[252]
    DIRECTION OUTPUT ;
    USE SIGNAL ;
    SHAPE ABUTMENT ;
    PORT
      LAYER M3 ;
      RECT 56.609 76.710 56.623 76.752 ;
    END
  END rw0_rd_out[252]
  PIN rw0_rd_out[253]
    DIRECTION OUTPUT ;
    USE SIGNAL ;
    SHAPE ABUTMENT ;
    PORT
      LAYER M3 ;
      RECT 56.833 76.710 56.847 76.752 ;
    END
  END rw0_rd_out[253]
  PIN rw0_rd_out[254]
    DIRECTION OUTPUT ;
    USE SIGNAL ;
    SHAPE ABUTMENT ;
    PORT
      LAYER M3 ;
      RECT 57.057 76.710 57.071 76.752 ;
    END
  END rw0_rd_out[254]
  PIN rw0_rd_out[255]
    DIRECTION OUTPUT ;
    USE SIGNAL ;
    SHAPE ABUTMENT ;
    PORT
      LAYER M3 ;
      RECT 57.281 76.710 57.295 76.752 ;
    END
  END rw0_rd_out[255]
  PIN rw0_addr_in[0]
    DIRECTION INPUT ;
    USE SIGNAL ;
    SHAPE ABUTMENT ;
    PORT
      LAYER M2 ;
      RECT 0.000 73.866 0.036 73.878 ;
    END
  END rw0_addr_in[0]
  PIN rw0_addr_in[1]
    DIRECTION INPUT ;
    USE SIGNAL ;
    SHAPE ABUTMENT ;
    PORT
      LAYER M2 ;
      RECT 0.000 74.442 0.036 74.454 ;
    END
  END rw0_addr_in[1]
  PIN rw0_addr_in[2]
    DIRECTION INPUT ;
    USE SIGNAL ;
    SHAPE ABUTMENT ;
    PORT
      LAYER M2 ;
      RECT 0.000 75.018 0.036 75.030 ;
    END
  END rw0_addr_in[2]
  PIN rw0_addr_in[3]
    DIRECTION INPUT ;
    USE SIGNAL ;
    SHAPE ABUTMENT ;
    PORT
      LAYER M2 ;
      RECT 0.000 75.594 0.036 75.606 ;
    END
  END rw0_addr_in[3]
  PIN rw0_addr_in[4]
    DIRECTION INPUT ;
    USE SIGNAL ;
    SHAPE ABUTMENT ;
    PORT
      LAYER M2 ;
      RECT 61.326 73.866 61.362 73.878 ;
    END
  END rw0_addr_in[4]
  PIN rw0_addr_in[5]
    DIRECTION INPUT ;
    USE SIGNAL ;
    SHAPE ABUTMENT ;
    PORT
      LAYER M2 ;
      RECT 61.326 74.442 61.362 74.454 ;
    END
  END rw0_addr_in[5]
  PIN rw0_addr_in[6]
    DIRECTION INPUT ;
    USE SIGNAL ;
    SHAPE ABUTMENT ;
    PORT
      LAYER M2 ;
      RECT 61.326 75.018 61.362 75.030 ;
    END
  END rw0_addr_in[6]
  PIN rw0_we_in
    DIRECTION INPUT ;
    USE SIGNAL ;
    SHAPE ABUTMENT ;
    PORT
      LAYER M3 ;
      RECT 57.505 76.710 57.519 76.752 ;
    END
  END rw0_we_in
  PIN rw0_ce_in
    DIRECTION INPUT ;
    USE SIGNAL ;
    SHAPE ABUTMENT ;
    PORT
      LAYER M3 ;
      RECT 57.729 76.710 57.743 76.752 ;
    END
  END rw0_ce_in
  PIN rw0_clk
    DIRECTION INPUT ;
    USE SIGNAL ;
    SHAPE ABUTMENT ;
    PORT
      LAYER M3 ;
      RECT 57.953 76.710 57.967 76.752 ;
    END
  END rw0_clk
  PIN VSS
    DIRECTION INOUT ;
    USE GROUND ;
    PORT
      LAYER M4 ;
      RECT 0.168 0.120 61.194 0.168 ;
      RECT 0.168 0.504 61.194 0.552 ;
      RECT 0.168 0.888 61.194 0.936 ;
      RECT 0.168 1.272 61.194 1.320 ;
      RECT 0.168 1.656 61.194 1.704 ;
      RECT 0.168 2.040 61.194 2.088 ;
      RECT 0.168 2.424 61.194 2.472 ;
      RECT 0.168 2.808 61.194 2.856 ;
      RECT 0.168 3.192 61.194 3.240 ;
      RECT 0.168 3.576 61.194 3.624 ;
      RECT 0.168 3.960 61.194 4.008 ;
      RECT 0.168 4.344 61.194 4.392 ;
      RECT 0.168 4.728 61.194 4.776 ;
      RECT 0.168 5.112 61.194 5.160 ;
      RECT 0.168 5.496 61.194 5.544 ;
      RECT 0.168 5.880 61.194 5.928 ;
      RECT 0.168 6.264 61.194 6.312 ;
      RECT 0.168 6.648 61.194 6.696 ;
      RECT 0.168 7.032 61.194 7.080 ;
      RECT 0.168 7.416 61.194 7.464 ;
      RECT 0.168 7.800 61.194 7.848 ;
      RECT 0.168 8.184 61.194 8.232 ;
      RECT 0.168 8.568 61.194 8.616 ;
      RECT 0.168 8.952 61.194 9.000 ;
      RECT 0.168 9.336 61.194 9.384 ;
      RECT 0.168 9.720 61.194 9.768 ;
      RECT 0.168 10.104 61.194 10.152 ;
      RECT 0.168 10.488 61.194 10.536 ;
      RECT 0.168 10.872 61.194 10.920 ;
      RECT 0.168 11.256 61.194 11.304 ;
      RECT 0.168 11.640 61.194 11.688 ;
      RECT 0.168 12.024 61.194 12.072 ;
      RECT 0.168 12.408 61.194 12.456 ;
      RECT 0.168 12.792 61.194 12.840 ;
      RECT 0.168 13.176 61.194 13.224 ;
      RECT 0.168 13.560 61.194 13.608 ;
      RECT 0.168 13.944 61.194 13.992 ;
      RECT 0.168 14.328 61.194 14.376 ;
      RECT 0.168 14.712 61.194 14.760 ;
      RECT 0.168 15.096 61.194 15.144 ;
      RECT 0.168 15.480 61.194 15.528 ;
      RECT 0.168 15.864 61.194 15.912 ;
      RECT 0.168 16.248 61.194 16.296 ;
      RECT 0.168 16.632 61.194 16.680 ;
      RECT 0.168 17.016 61.194 17.064 ;
      RECT 0.168 17.400 61.194 17.448 ;
      RECT 0.168 17.784 61.194 17.832 ;
      RECT 0.168 18.168 61.194 18.216 ;
      RECT 0.168 18.552 61.194 18.600 ;
      RECT 0.168 18.936 61.194 18.984 ;
      RECT 0.168 19.320 61.194 19.368 ;
      RECT 0.168 19.704 61.194 19.752 ;
      RECT 0.168 20.088 61.194 20.136 ;
      RECT 0.168 20.472 61.194 20.520 ;
      RECT 0.168 20.856 61.194 20.904 ;
      RECT 0.168 21.240 61.194 21.288 ;
      RECT 0.168 21.624 61.194 21.672 ;
      RECT 0.168 22.008 61.194 22.056 ;
      RECT 0.168 22.392 61.194 22.440 ;
      RECT 0.168 22.776 61.194 22.824 ;
      RECT 0.168 23.160 61.194 23.208 ;
      RECT 0.168 23.544 61.194 23.592 ;
      RECT 0.168 23.928 61.194 23.976 ;
      RECT 0.168 24.312 61.194 24.360 ;
      RECT 0.168 24.696 61.194 24.744 ;
      RECT 0.168 25.080 61.194 25.128 ;
      RECT 0.168 25.464 61.194 25.512 ;
      RECT 0.168 25.848 61.194 25.896 ;
      RECT 0.168 26.232 61.194 26.280 ;
      RECT 0.168 26.616 61.194 26.664 ;
      RECT 0.168 27.000 61.194 27.048 ;
      RECT 0.168 27.384 61.194 27.432 ;
      RECT 0.168 27.768 61.194 27.816 ;
      RECT 0.168 28.152 61.194 28.200 ;
      RECT 0.168 28.536 61.194 28.584 ;
      RECT 0.168 28.920 61.194 28.968 ;
      RECT 0.168 29.304 61.194 29.352 ;
      RECT 0.168 29.688 61.194 29.736 ;
      RECT 0.168 30.072 61.194 30.120 ;
      RECT 0.168 30.456 61.194 30.504 ;
      RECT 0.168 30.840 61.194 30.888 ;
      RECT 0.168 31.224 61.194 31.272 ;
      RECT 0.168 31.608 61.194 31.656 ;
      RECT 0.168 31.992 61.194 32.040 ;
      RECT 0.168 32.376 61.194 32.424 ;
      RECT 0.168 32.760 61.194 32.808 ;
      RECT 0.168 33.144 61.194 33.192 ;
      RECT 0.168 33.528 61.194 33.576 ;
      RECT 0.168 33.912 61.194 33.960 ;
      RECT 0.168 34.296 61.194 34.344 ;
      RECT 0.168 34.680 61.194 34.728 ;
      RECT 0.168 35.064 61.194 35.112 ;
      RECT 0.168 35.448 61.194 35.496 ;
      RECT 0.168 35.832 61.194 35.880 ;
      RECT 0.168 36.216 61.194 36.264 ;
      RECT 0.168 36.600 61.194 36.648 ;
      RECT 0.168 36.984 61.194 37.032 ;
      RECT 0.168 37.368 61.194 37.416 ;
      RECT 0.168 37.752 61.194 37.800 ;
      RECT 0.168 38.136 61.194 38.184 ;
      RECT 0.168 38.520 61.194 38.568 ;
      RECT 0.168 38.904 61.194 38.952 ;
      RECT 0.168 39.288 61.194 39.336 ;
      RECT 0.168 39.672 61.194 39.720 ;
      RECT 0.168 40.056 61.194 40.104 ;
      RECT 0.168 40.440 61.194 40.488 ;
      RECT 0.168 40.824 61.194 40.872 ;
      RECT 0.168 41.208 61.194 41.256 ;
      RECT 0.168 41.592 61.194 41.640 ;
      RECT 0.168 41.976 61.194 42.024 ;
      RECT 0.168 42.360 61.194 42.408 ;
      RECT 0.168 42.744 61.194 42.792 ;
      RECT 0.168 43.128 61.194 43.176 ;
      RECT 0.168 43.512 61.194 43.560 ;
      RECT 0.168 43.896 61.194 43.944 ;
      RECT 0.168 44.280 61.194 44.328 ;
      RECT 0.168 44.664 61.194 44.712 ;
      RECT 0.168 45.048 61.194 45.096 ;
      RECT 0.168 45.432 61.194 45.480 ;
      RECT 0.168 45.816 61.194 45.864 ;
      RECT 0.168 46.200 61.194 46.248 ;
      RECT 0.168 46.584 61.194 46.632 ;
      RECT 0.168 46.968 61.194 47.016 ;
      RECT 0.168 47.352 61.194 47.400 ;
      RECT 0.168 47.736 61.194 47.784 ;
      RECT 0.168 48.120 61.194 48.168 ;
      RECT 0.168 48.504 61.194 48.552 ;
      RECT 0.168 48.888 61.194 48.936 ;
      RECT 0.168 49.272 61.194 49.320 ;
      RECT 0.168 49.656 61.194 49.704 ;
      RECT 0.168 50.040 61.194 50.088 ;
      RECT 0.168 50.424 61.194 50.472 ;
      RECT 0.168 50.808 61.194 50.856 ;
      RECT 0.168 51.192 61.194 51.240 ;
      RECT 0.168 51.576 61.194 51.624 ;
      RECT 0.168 51.960 61.194 52.008 ;
      RECT 0.168 52.344 61.194 52.392 ;
      RECT 0.168 52.728 61.194 52.776 ;
      RECT 0.168 53.112 61.194 53.160 ;
      RECT 0.168 53.496 61.194 53.544 ;
      RECT 0.168 53.880 61.194 53.928 ;
      RECT 0.168 54.264 61.194 54.312 ;
      RECT 0.168 54.648 61.194 54.696 ;
      RECT 0.168 55.032 61.194 55.080 ;
      RECT 0.168 55.416 61.194 55.464 ;
      RECT 0.168 55.800 61.194 55.848 ;
      RECT 0.168 56.184 61.194 56.232 ;
      RECT 0.168 56.568 61.194 56.616 ;
      RECT 0.168 56.952 61.194 57.000 ;
      RECT 0.168 57.336 61.194 57.384 ;
      RECT 0.168 57.720 61.194 57.768 ;
      RECT 0.168 58.104 61.194 58.152 ;
      RECT 0.168 58.488 61.194 58.536 ;
      RECT 0.168 58.872 61.194 58.920 ;
      RECT 0.168 59.256 61.194 59.304 ;
      RECT 0.168 59.640 61.194 59.688 ;
      RECT 0.168 60.024 61.194 60.072 ;
      RECT 0.168 60.408 61.194 60.456 ;
      RECT 0.168 60.792 61.194 60.840 ;
      RECT 0.168 61.176 61.194 61.224 ;
      RECT 0.168 61.560 61.194 61.608 ;
      RECT 0.168 61.944 61.194 61.992 ;
      RECT 0.168 62.328 61.194 62.376 ;
      RECT 0.168 62.712 61.194 62.760 ;
      RECT 0.168 63.096 61.194 63.144 ;
      RECT 0.168 63.480 61.194 63.528 ;
      RECT 0.168 63.864 61.194 63.912 ;
      RECT 0.168 64.248 61.194 64.296 ;
      RECT 0.168 64.632 61.194 64.680 ;
      RECT 0.168 65.016 61.194 65.064 ;
      RECT 0.168 65.400 61.194 65.448 ;
      RECT 0.168 65.784 61.194 65.832 ;
      RECT 0.168 66.168 61.194 66.216 ;
      RECT 0.168 66.552 61.194 66.600 ;
      RECT 0.168 66.936 61.194 66.984 ;
      RECT 0.168 67.320 61.194 67.368 ;
      RECT 0.168 67.704 61.194 67.752 ;
      RECT 0.168 68.088 61.194 68.136 ;
      RECT 0.168 68.472 61.194 68.520 ;
      RECT 0.168 68.856 61.194 68.904 ;
      RECT 0.168 69.240 61.194 69.288 ;
      RECT 0.168 69.624 61.194 69.672 ;
      RECT 0.168 70.008 61.194 70.056 ;
      RECT 0.168 70.392 61.194 70.440 ;
      RECT 0.168 70.776 61.194 70.824 ;
      RECT 0.168 71.160 61.194 71.208 ;
      RECT 0.168 71.544 61.194 71.592 ;
      RECT 0.168 71.928 61.194 71.976 ;
      RECT 0.168 72.312 61.194 72.360 ;
      RECT 0.168 72.696 61.194 72.744 ;
      RECT 0.168 73.080 61.194 73.128 ;
      RECT 0.168 73.464 61.194 73.512 ;
      RECT 0.168 73.848 61.194 73.896 ;
      RECT 0.168 74.232 61.194 74.280 ;
      RECT 0.168 74.616 61.194 74.664 ;
      RECT 0.168 75.000 61.194 75.048 ;
      RECT 0.168 75.384 61.194 75.432 ;
      RECT 0.168 75.768 61.194 75.816 ;
      RECT 0.168 76.152 61.194 76.200 ;
      RECT 0.168 76.536 61.194 76.584 ;
    END
  END VSS
  PIN VDD
    DIRECTION INOUT ;
    USE POWER ;
    PORT
      LAYER M4 ;
      RECT 0.168 0.312 61.194 0.360 ;
      RECT 0.168 0.696 61.194 0.744 ;
      RECT 0.168 1.080 61.194 1.128 ;
      RECT 0.168 1.464 61.194 1.512 ;
      RECT 0.168 1.848 61.194 1.896 ;
      RECT 0.168 2.232 61.194 2.280 ;
      RECT 0.168 2.616 61.194 2.664 ;
      RECT 0.168 3.000 61.194 3.048 ;
      RECT 0.168 3.384 61.194 3.432 ;
      RECT 0.168 3.768 61.194 3.816 ;
      RECT 0.168 4.152 61.194 4.200 ;
      RECT 0.168 4.536 61.194 4.584 ;
      RECT 0.168 4.920 61.194 4.968 ;
      RECT 0.168 5.304 61.194 5.352 ;
      RECT 0.168 5.688 61.194 5.736 ;
      RECT 0.168 6.072 61.194 6.120 ;
      RECT 0.168 6.456 61.194 6.504 ;
      RECT 0.168 6.840 61.194 6.888 ;
      RECT 0.168 7.224 61.194 7.272 ;
      RECT 0.168 7.608 61.194 7.656 ;
      RECT 0.168 7.992 61.194 8.040 ;
      RECT 0.168 8.376 61.194 8.424 ;
      RECT 0.168 8.760 61.194 8.808 ;
      RECT 0.168 9.144 61.194 9.192 ;
      RECT 0.168 9.528 61.194 9.576 ;
      RECT 0.168 9.912 61.194 9.960 ;
      RECT 0.168 10.296 61.194 10.344 ;
      RECT 0.168 10.680 61.194 10.728 ;
      RECT 0.168 11.064 61.194 11.112 ;
      RECT 0.168 11.448 61.194 11.496 ;
      RECT 0.168 11.832 61.194 11.880 ;
      RECT 0.168 12.216 61.194 12.264 ;
      RECT 0.168 12.600 61.194 12.648 ;
      RECT 0.168 12.984 61.194 13.032 ;
      RECT 0.168 13.368 61.194 13.416 ;
      RECT 0.168 13.752 61.194 13.800 ;
      RECT 0.168 14.136 61.194 14.184 ;
      RECT 0.168 14.520 61.194 14.568 ;
      RECT 0.168 14.904 61.194 14.952 ;
      RECT 0.168 15.288 61.194 15.336 ;
      RECT 0.168 15.672 61.194 15.720 ;
      RECT 0.168 16.056 61.194 16.104 ;
      RECT 0.168 16.440 61.194 16.488 ;
      RECT 0.168 16.824 61.194 16.872 ;
      RECT 0.168 17.208 61.194 17.256 ;
      RECT 0.168 17.592 61.194 17.640 ;
      RECT 0.168 17.976 61.194 18.024 ;
      RECT 0.168 18.360 61.194 18.408 ;
      RECT 0.168 18.744 61.194 18.792 ;
      RECT 0.168 19.128 61.194 19.176 ;
      RECT 0.168 19.512 61.194 19.560 ;
      RECT 0.168 19.896 61.194 19.944 ;
      RECT 0.168 20.280 61.194 20.328 ;
      RECT 0.168 20.664 61.194 20.712 ;
      RECT 0.168 21.048 61.194 21.096 ;
      RECT 0.168 21.432 61.194 21.480 ;
      RECT 0.168 21.816 61.194 21.864 ;
      RECT 0.168 22.200 61.194 22.248 ;
      RECT 0.168 22.584 61.194 22.632 ;
      RECT 0.168 22.968 61.194 23.016 ;
      RECT 0.168 23.352 61.194 23.400 ;
      RECT 0.168 23.736 61.194 23.784 ;
      RECT 0.168 24.120 61.194 24.168 ;
      RECT 0.168 24.504 61.194 24.552 ;
      RECT 0.168 24.888 61.194 24.936 ;
      RECT 0.168 25.272 61.194 25.320 ;
      RECT 0.168 25.656 61.194 25.704 ;
      RECT 0.168 26.040 61.194 26.088 ;
      RECT 0.168 26.424 61.194 26.472 ;
      RECT 0.168 26.808 61.194 26.856 ;
      RECT 0.168 27.192 61.194 27.240 ;
      RECT 0.168 27.576 61.194 27.624 ;
      RECT 0.168 27.960 61.194 28.008 ;
      RECT 0.168 28.344 61.194 28.392 ;
      RECT 0.168 28.728 61.194 28.776 ;
      RECT 0.168 29.112 61.194 29.160 ;
      RECT 0.168 29.496 61.194 29.544 ;
      RECT 0.168 29.880 61.194 29.928 ;
      RECT 0.168 30.264 61.194 30.312 ;
      RECT 0.168 30.648 61.194 30.696 ;
      RECT 0.168 31.032 61.194 31.080 ;
      RECT 0.168 31.416 61.194 31.464 ;
      RECT 0.168 31.800 61.194 31.848 ;
      RECT 0.168 32.184 61.194 32.232 ;
      RECT 0.168 32.568 61.194 32.616 ;
      RECT 0.168 32.952 61.194 33.000 ;
      RECT 0.168 33.336 61.194 33.384 ;
      RECT 0.168 33.720 61.194 33.768 ;
      RECT 0.168 34.104 61.194 34.152 ;
      RECT 0.168 34.488 61.194 34.536 ;
      RECT 0.168 34.872 61.194 34.920 ;
      RECT 0.168 35.256 61.194 35.304 ;
      RECT 0.168 35.640 61.194 35.688 ;
      RECT 0.168 36.024 61.194 36.072 ;
      RECT 0.168 36.408 61.194 36.456 ;
      RECT 0.168 36.792 61.194 36.840 ;
      RECT 0.168 37.176 61.194 37.224 ;
      RECT 0.168 37.560 61.194 37.608 ;
      RECT 0.168 37.944 61.194 37.992 ;
      RECT 0.168 38.328 61.194 38.376 ;
      RECT 0.168 38.712 61.194 38.760 ;
      RECT 0.168 39.096 61.194 39.144 ;
      RECT 0.168 39.480 61.194 39.528 ;
      RECT 0.168 39.864 61.194 39.912 ;
      RECT 0.168 40.248 61.194 40.296 ;
      RECT 0.168 40.632 61.194 40.680 ;
      RECT 0.168 41.016 61.194 41.064 ;
      RECT 0.168 41.400 61.194 41.448 ;
      RECT 0.168 41.784 61.194 41.832 ;
      RECT 0.168 42.168 61.194 42.216 ;
      RECT 0.168 42.552 61.194 42.600 ;
      RECT 0.168 42.936 61.194 42.984 ;
      RECT 0.168 43.320 61.194 43.368 ;
      RECT 0.168 43.704 61.194 43.752 ;
      RECT 0.168 44.088 61.194 44.136 ;
      RECT 0.168 44.472 61.194 44.520 ;
      RECT 0.168 44.856 61.194 44.904 ;
      RECT 0.168 45.240 61.194 45.288 ;
      RECT 0.168 45.624 61.194 45.672 ;
      RECT 0.168 46.008 61.194 46.056 ;
      RECT 0.168 46.392 61.194 46.440 ;
      RECT 0.168 46.776 61.194 46.824 ;
      RECT 0.168 47.160 61.194 47.208 ;
      RECT 0.168 47.544 61.194 47.592 ;
      RECT 0.168 47.928 61.194 47.976 ;
      RECT 0.168 48.312 61.194 48.360 ;
      RECT 0.168 48.696 61.194 48.744 ;
      RECT 0.168 49.080 61.194 49.128 ;
      RECT 0.168 49.464 61.194 49.512 ;
      RECT 0.168 49.848 61.194 49.896 ;
      RECT 0.168 50.232 61.194 50.280 ;
      RECT 0.168 50.616 61.194 50.664 ;
      RECT 0.168 51.000 61.194 51.048 ;
      RECT 0.168 51.384 61.194 51.432 ;
      RECT 0.168 51.768 61.194 51.816 ;
      RECT 0.168 52.152 61.194 52.200 ;
      RECT 0.168 52.536 61.194 52.584 ;
      RECT 0.168 52.920 61.194 52.968 ;
      RECT 0.168 53.304 61.194 53.352 ;
      RECT 0.168 53.688 61.194 53.736 ;
      RECT 0.168 54.072 61.194 54.120 ;
      RECT 0.168 54.456 61.194 54.504 ;
      RECT 0.168 54.840 61.194 54.888 ;
      RECT 0.168 55.224 61.194 55.272 ;
      RECT 0.168 55.608 61.194 55.656 ;
      RECT 0.168 55.992 61.194 56.040 ;
      RECT 0.168 56.376 61.194 56.424 ;
      RECT 0.168 56.760 61.194 56.808 ;
      RECT 0.168 57.144 61.194 57.192 ;
      RECT 0.168 57.528 61.194 57.576 ;
      RECT 0.168 57.912 61.194 57.960 ;
      RECT 0.168 58.296 61.194 58.344 ;
      RECT 0.168 58.680 61.194 58.728 ;
      RECT 0.168 59.064 61.194 59.112 ;
      RECT 0.168 59.448 61.194 59.496 ;
      RECT 0.168 59.832 61.194 59.880 ;
      RECT 0.168 60.216 61.194 60.264 ;
      RECT 0.168 60.600 61.194 60.648 ;
      RECT 0.168 60.984 61.194 61.032 ;
      RECT 0.168 61.368 61.194 61.416 ;
      RECT 0.168 61.752 61.194 61.800 ;
      RECT 0.168 62.136 61.194 62.184 ;
      RECT 0.168 62.520 61.194 62.568 ;
      RECT 0.168 62.904 61.194 62.952 ;
      RECT 0.168 63.288 61.194 63.336 ;
      RECT 0.168 63.672 61.194 63.720 ;
      RECT 0.168 64.056 61.194 64.104 ;
      RECT 0.168 64.440 61.194 64.488 ;
      RECT 0.168 64.824 61.194 64.872 ;
      RECT 0.168 65.208 61.194 65.256 ;
      RECT 0.168 65.592 61.194 65.640 ;
      RECT 0.168 65.976 61.194 66.024 ;
      RECT 0.168 66.360 61.194 66.408 ;
      RECT 0.168 66.744 61.194 66.792 ;
      RECT 0.168 67.128 61.194 67.176 ;
      RECT 0.168 67.512 61.194 67.560 ;
      RECT 0.168 67.896 61.194 67.944 ;
      RECT 0.168 68.280 61.194 68.328 ;
      RECT 0.168 68.664 61.194 68.712 ;
      RECT 0.168 69.048 61.194 69.096 ;
      RECT 0.168 69.432 61.194 69.480 ;
      RECT 0.168 69.816 61.194 69.864 ;
      RECT 0.168 70.200 61.194 70.248 ;
      RECT 0.168 70.584 61.194 70.632 ;
      RECT 0.168 70.968 61.194 71.016 ;
      RECT 0.168 71.352 61.194 71.400 ;
      RECT 0.168 71.736 61.194 71.784 ;
      RECT 0.168 72.120 61.194 72.168 ;
      RECT 0.168 72.504 61.194 72.552 ;
      RECT 0.168 72.888 61.194 72.936 ;
      RECT 0.168 73.272 61.194 73.320 ;
      RECT 0.168 73.656 61.194 73.704 ;
      RECT 0.168 74.040 61.194 74.088 ;
      RECT 0.168 74.424 61.194 74.472 ;
      RECT 0.168 74.808 61.194 74.856 ;
      RECT 0.168 75.192 61.194 75.240 ;
      RECT 0.168 75.576 61.194 75.624 ;
      RECT 0.168 75.960 61.194 76.008 ;
      RECT 0.168 76.344 61.194 76.392 ;
    END
  END VDD
  OBS
    LAYER M1 ;
    RECT 0 0 61.362 76.752 ;
    LAYER M2 ;
    RECT 0 0 61.362 76.752 ;
    LAYER M3 ;
    RECT 0 0 61.362 76.752 ;
    LAYER M4 ;
    RECT 0 0 61.362 76.752 ;
  END
END fakeram_128x256_1rw

END LIBRARY
